VERSION 5.8 ;
BUSBITCHARS "[]" ;
DIVIDERCHAR "/" ;
UNITS
    DATABASE MICRONS 1000 ;
END UNITS

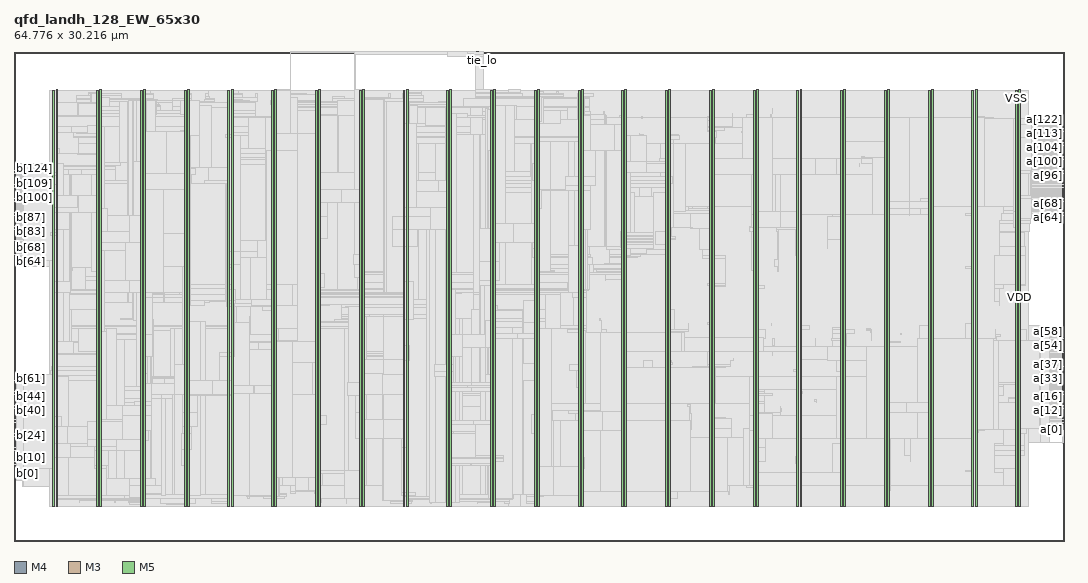
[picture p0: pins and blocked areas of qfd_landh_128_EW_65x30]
MACRO qfd_landh_128_EW_65x30
  FOREIGN qfd_landh_128_EW_65x30 0 0 ;
  CLASS BLOCK ;
  SIZE 64.776 BY 30.216 ;
  PIN a[0]
    DIRECTION INPUT ;
    USE SIGNAL ;
    PORT
      LAYER M4 ;
        RECT  64.692 6.864 64.776 6.888 ;
    END
  END a[0]
  PIN a[100]
    DIRECTION INPUT ;
    USE SIGNAL ;
    PORT
      LAYER M4 ;
        RECT  64.692 23.376 64.776 23.4 ;
    END
  END a[100]
  PIN a[101]
    DIRECTION INPUT ;
    USE SIGNAL ;
    PORT
      LAYER M4 ;
        RECT  64.692 23.472 64.776 23.496 ;
    END
  END a[101]
  PIN a[102]
    DIRECTION INPUT ;
    USE SIGNAL ;
    PORT
      LAYER M4 ;
        RECT  64.692 23.568 64.776 23.592 ;
    END
  END a[102]
  PIN a[103]
    DIRECTION INPUT ;
    USE SIGNAL ;
    PORT
      LAYER M4 ;
        RECT  64.692 23.664 64.776 23.688 ;
    END
  END a[103]
  PIN a[104]
    DIRECTION INPUT ;
    USE SIGNAL ;
    PORT
      LAYER M4 ;
        RECT  64.692 23.76 64.776 23.784 ;
    END
  END a[104]
  PIN a[105]
    DIRECTION INPUT ;
    USE SIGNAL ;
    PORT
      LAYER M4 ;
        RECT  64.692 23.856 64.776 23.88 ;
    END
  END a[105]
  PIN a[106]
    DIRECTION INPUT ;
    USE SIGNAL ;
    PORT
      LAYER M4 ;
        RECT  64.692 23.952 64.776 23.976 ;
    END
  END a[106]
  PIN a[107]
    DIRECTION INPUT ;
    USE SIGNAL ;
    PORT
      LAYER M4 ;
        RECT  64.692 24.048 64.776 24.072 ;
    END
  END a[107]
  PIN a[108]
    DIRECTION INPUT ;
    USE SIGNAL ;
    PORT
      LAYER M4 ;
        RECT  64.692 24.144 64.776 24.168 ;
    END
  END a[108]
  PIN a[109]
    DIRECTION INPUT ;
    USE SIGNAL ;
    PORT
      LAYER M4 ;
        RECT  64.692 24.24 64.776 24.264 ;
    END
  END a[109]
  PIN a[10]
    DIRECTION INPUT ;
    USE SIGNAL ;
    PORT
      LAYER M4 ;
        RECT  64.692 7.824 64.776 7.848 ;
    END
  END a[10]
  PIN a[110]
    DIRECTION INPUT ;
    USE SIGNAL ;
    PORT
      LAYER M4 ;
        RECT  64.692 24.336 64.776 24.36 ;
    END
  END a[110]
  PIN a[111]
    DIRECTION INPUT ;
    USE SIGNAL ;
    PORT
      LAYER M4 ;
        RECT  64.692 24.432 64.776 24.456 ;
    END
  END a[111]
  PIN a[112]
    DIRECTION INPUT ;
    USE SIGNAL ;
    PORT
      LAYER M4 ;
        RECT  64.692 24.528 64.776 24.552 ;
    END
  END a[112]
  PIN a[113]
    DIRECTION INPUT ;
    USE SIGNAL ;
    PORT
      LAYER M4 ;
        RECT  64.692 24.624 64.776 24.648 ;
    END
  END a[113]
  PIN a[114]
    DIRECTION INPUT ;
    USE SIGNAL ;
    PORT
      LAYER M4 ;
        RECT  64.692 24.72 64.776 24.744 ;
    END
  END a[114]
  PIN a[115]
    DIRECTION INPUT ;
    USE SIGNAL ;
    PORT
      LAYER M4 ;
        RECT  64.692 24.816 64.776 24.84 ;
    END
  END a[115]
  PIN a[116]
    DIRECTION INPUT ;
    USE SIGNAL ;
    PORT
      LAYER M4 ;
        RECT  64.692 24.912 64.776 24.936 ;
    END
  END a[116]
  PIN a[117]
    DIRECTION INPUT ;
    USE SIGNAL ;
    PORT
      LAYER M4 ;
        RECT  64.692 25.008 64.776 25.032 ;
    END
  END a[117]
  PIN a[118]
    DIRECTION INPUT ;
    USE SIGNAL ;
    PORT
      LAYER M4 ;
        RECT  64.692 25.104 64.776 25.128 ;
    END
  END a[118]
  PIN a[119]
    DIRECTION INPUT ;
    USE SIGNAL ;
    PORT
      LAYER M4 ;
        RECT  64.692 25.2 64.776 25.224 ;
    END
  END a[119]
  PIN a[11]
    DIRECTION INPUT ;
    USE SIGNAL ;
    PORT
      LAYER M4 ;
        RECT  64.692 7.92 64.776 7.944 ;
    END
  END a[11]
  PIN a[120]
    DIRECTION INPUT ;
    USE SIGNAL ;
    PORT
      LAYER M4 ;
        RECT  64.692 25.296 64.776 25.32 ;
    END
  END a[120]
  PIN a[121]
    DIRECTION INPUT ;
    USE SIGNAL ;
    PORT
      LAYER M4 ;
        RECT  64.692 25.392 64.776 25.416 ;
    END
  END a[121]
  PIN a[122]
    DIRECTION INPUT ;
    USE SIGNAL ;
    PORT
      LAYER M4 ;
        RECT  64.692 25.488 64.776 25.512 ;
    END
  END a[122]
  PIN a[123]
    DIRECTION INPUT ;
    USE SIGNAL ;
    PORT
      LAYER M4 ;
        RECT  64.692 25.584 64.776 25.608 ;
    END
  END a[123]
  PIN a[124]
    DIRECTION INPUT ;
    USE SIGNAL ;
    PORT
      LAYER M4 ;
        RECT  64.692 25.68 64.776 25.704 ;
    END
  END a[124]
  PIN a[125]
    DIRECTION INPUT ;
    USE SIGNAL ;
    PORT
      LAYER M4 ;
        RECT  64.692 25.776 64.776 25.8 ;
    END
  END a[125]
  PIN a[126]
    DIRECTION INPUT ;
    USE SIGNAL ;
    PORT
      LAYER M4 ;
        RECT  64.692 25.872 64.776 25.896 ;
    END
  END a[126]
  PIN a[127]
    DIRECTION INPUT ;
    USE SIGNAL ;
    PORT
      LAYER M4 ;
        RECT  64.692 25.968 64.776 25.992 ;
    END
  END a[127]
  PIN a[12]
    DIRECTION INPUT ;
    USE SIGNAL ;
    PORT
      LAYER M4 ;
        RECT  64.692 8.016 64.776 8.04 ;
    END
  END a[12]
  PIN a[13]
    DIRECTION INPUT ;
    USE SIGNAL ;
    PORT
      LAYER M4 ;
        RECT  64.692 8.112 64.776 8.136 ;
    END
  END a[13]
  PIN a[14]
    DIRECTION INPUT ;
    USE SIGNAL ;
    PORT
      LAYER M4 ;
        RECT  64.692 8.208 64.776 8.232 ;
    END
  END a[14]
  PIN a[15]
    DIRECTION INPUT ;
    USE SIGNAL ;
    PORT
      LAYER M4 ;
        RECT  64.692 8.304 64.776 8.328 ;
    END
  END a[15]
  PIN a[16]
    DIRECTION INPUT ;
    USE SIGNAL ;
    PORT
      LAYER M4 ;
        RECT  64.692 8.4 64.776 8.424 ;
    END
  END a[16]
  PIN a[17]
    DIRECTION INPUT ;
    USE SIGNAL ;
    PORT
      LAYER M4 ;
        RECT  64.692 8.496 64.776 8.52 ;
    END
  END a[17]
  PIN a[18]
    DIRECTION INPUT ;
    USE SIGNAL ;
    PORT
      LAYER M4 ;
        RECT  64.692 8.592 64.776 8.616 ;
    END
  END a[18]
  PIN a[19]
    DIRECTION INPUT ;
    USE SIGNAL ;
    PORT
      LAYER M4 ;
        RECT  64.692 8.688 64.776 8.712 ;
    END
  END a[19]
  PIN a[1]
    DIRECTION INPUT ;
    USE SIGNAL ;
    PORT
      LAYER M4 ;
        RECT  64.692 6.96 64.776 6.984 ;
    END
  END a[1]
  PIN a[20]
    DIRECTION INPUT ;
    USE SIGNAL ;
    PORT
      LAYER M4 ;
        RECT  64.692 8.784 64.776 8.808 ;
    END
  END a[20]
  PIN a[21]
    DIRECTION INPUT ;
    USE SIGNAL ;
    PORT
      LAYER M4 ;
        RECT  64.692 8.88 64.776 8.904 ;
    END
  END a[21]
  PIN a[22]
    DIRECTION INPUT ;
    USE SIGNAL ;
    PORT
      LAYER M4 ;
        RECT  64.692 8.976 64.776 9 ;
    END
  END a[22]
  PIN a[23]
    DIRECTION INPUT ;
    USE SIGNAL ;
    PORT
      LAYER M4 ;
        RECT  64.692 9.072 64.776 9.096 ;
    END
  END a[23]
  PIN a[24]
    DIRECTION INPUT ;
    USE SIGNAL ;
    PORT
      LAYER M4 ;
        RECT  64.692 9.168 64.776 9.192 ;
    END
  END a[24]
  PIN a[25]
    DIRECTION INPUT ;
    USE SIGNAL ;
    PORT
      LAYER M4 ;
        RECT  64.692 9.264 64.776 9.288 ;
    END
  END a[25]
  PIN a[26]
    DIRECTION INPUT ;
    USE SIGNAL ;
    PORT
      LAYER M4 ;
        RECT  64.692 9.36 64.776 9.384 ;
    END
  END a[26]
  PIN a[27]
    DIRECTION INPUT ;
    USE SIGNAL ;
    PORT
      LAYER M4 ;
        RECT  64.692 9.456 64.776 9.48 ;
    END
  END a[27]
  PIN a[28]
    DIRECTION INPUT ;
    USE SIGNAL ;
    PORT
      LAYER M4 ;
        RECT  64.692 9.552 64.776 9.576 ;
    END
  END a[28]
  PIN a[29]
    DIRECTION INPUT ;
    USE SIGNAL ;
    PORT
      LAYER M4 ;
        RECT  64.692 9.648 64.776 9.672 ;
    END
  END a[29]
  PIN a[2]
    DIRECTION INPUT ;
    USE SIGNAL ;
    PORT
      LAYER M4 ;
        RECT  64.692 7.056 64.776 7.08 ;
    END
  END a[2]
  PIN a[30]
    DIRECTION INPUT ;
    USE SIGNAL ;
    PORT
      LAYER M4 ;
        RECT  64.692 9.744 64.776 9.768 ;
    END
  END a[30]
  PIN a[31]
    DIRECTION INPUT ;
    USE SIGNAL ;
    PORT
      LAYER M4 ;
        RECT  64.692 9.84 64.776 9.864 ;
    END
    PORT
      LAYER M4 ;
        RECT  64.716 9.792 64.757 9.912 ;
    END
  END a[31]
  PIN a[32]
    DIRECTION INPUT ;
    USE SIGNAL ;
    PORT
      LAYER M4 ;
        RECT  64.692 9.936 64.776 9.96 ;
    END
  END a[32]
  PIN a[33]
    DIRECTION INPUT ;
    USE SIGNAL ;
    PORT
      LAYER M4 ;
        RECT  64.692 10.032 64.776 10.056 ;
    END
  END a[33]
  PIN a[34]
    DIRECTION INPUT ;
    USE SIGNAL ;
    PORT
      LAYER M4 ;
        RECT  64.692 10.128 64.776 10.152 ;
    END
  END a[34]
  PIN a[35]
    DIRECTION INPUT ;
    USE SIGNAL ;
    PORT
      LAYER M4 ;
        RECT  64.692 10.224 64.776 10.248 ;
    END
  END a[35]
  PIN a[36]
    DIRECTION INPUT ;
    USE SIGNAL ;
    PORT
      LAYER M4 ;
        RECT  64.692 10.32 64.776 10.344 ;
    END
  END a[36]
  PIN a[37]
    DIRECTION INPUT ;
    USE SIGNAL ;
    PORT
      LAYER M4 ;
        RECT  64.692 10.416 64.776 10.44 ;
    END
  END a[37]
  PIN a[38]
    DIRECTION INPUT ;
    USE SIGNAL ;
    PORT
      LAYER M4 ;
        RECT  64.692 10.512 64.776 10.536 ;
    END
  END a[38]
  PIN a[39]
    DIRECTION INPUT ;
    USE SIGNAL ;
    PORT
      LAYER M4 ;
        RECT  64.692 10.608 64.776 10.632 ;
    END
  END a[39]
  PIN a[3]
    DIRECTION INPUT ;
    USE SIGNAL ;
    PORT
      LAYER M4 ;
        RECT  64.692 7.152 64.776 7.176 ;
    END
  END a[3]
  PIN a[40]
    DIRECTION INPUT ;
    USE SIGNAL ;
    PORT
      LAYER M4 ;
        RECT  64.692 10.704 64.776 10.728 ;
    END
  END a[40]
  PIN a[41]
    DIRECTION INPUT ;
    USE SIGNAL ;
    PORT
      LAYER M4 ;
        RECT  64.692 10.8 64.776 10.824 ;
    END
  END a[41]
  PIN a[42]
    DIRECTION INPUT ;
    USE SIGNAL ;
    PORT
      LAYER M4 ;
        RECT  64.692 10.896 64.776 10.92 ;
    END
  END a[42]
  PIN a[43]
    DIRECTION INPUT ;
    USE SIGNAL ;
    PORT
      LAYER M4 ;
        RECT  64.692 10.992 64.776 11.016 ;
    END
  END a[43]
  PIN a[44]
    DIRECTION INPUT ;
    USE SIGNAL ;
    PORT
      LAYER M4 ;
        RECT  64.692 11.088 64.776 11.112 ;
    END
  END a[44]
  PIN a[45]
    DIRECTION INPUT ;
    USE SIGNAL ;
    PORT
      LAYER M4 ;
        RECT  64.692 11.184 64.776 11.208 ;
    END
  END a[45]
  PIN a[46]
    DIRECTION INPUT ;
    USE SIGNAL ;
    PORT
      LAYER M4 ;
        RECT  64.692 11.28 64.776 11.304 ;
    END
  END a[46]
  PIN a[47]
    DIRECTION INPUT ;
    USE SIGNAL ;
    PORT
      LAYER M4 ;
        RECT  64.692 11.376 64.776 11.4 ;
    END
  END a[47]
  PIN a[48]
    DIRECTION INPUT ;
    USE SIGNAL ;
    PORT
      LAYER M4 ;
        RECT  64.692 11.472 64.776 11.496 ;
    END
  END a[48]
  PIN a[49]
    DIRECTION INPUT ;
    USE SIGNAL ;
    PORT
      LAYER M4 ;
        RECT  64.692 11.568 64.776 11.592 ;
    END
  END a[49]
  PIN a[4]
    DIRECTION INPUT ;
    USE SIGNAL ;
    PORT
      LAYER M4 ;
        RECT  64.692 7.248 64.776 7.272 ;
    END
  END a[4]
  PIN a[50]
    DIRECTION INPUT ;
    USE SIGNAL ;
    PORT
      LAYER M4 ;
        RECT  64.692 11.664 64.776 11.688 ;
    END
  END a[50]
  PIN a[51]
    DIRECTION INPUT ;
    USE SIGNAL ;
    PORT
      LAYER M4 ;
        RECT  64.692 11.76 64.776 11.784 ;
    END
  END a[51]
  PIN a[52]
    DIRECTION INPUT ;
    USE SIGNAL ;
    PORT
      LAYER M4 ;
        RECT  64.692 11.856 64.776 11.88 ;
    END
  END a[52]
  PIN a[53]
    DIRECTION INPUT ;
    USE SIGNAL ;
    PORT
      LAYER M4 ;
        RECT  64.692 11.952 64.776 11.976 ;
    END
  END a[53]
  PIN a[54]
    DIRECTION INPUT ;
    USE SIGNAL ;
    PORT
      LAYER M4 ;
        RECT  64.692 12.048 64.776 12.072 ;
    END
  END a[54]
  PIN a[55]
    DIRECTION INPUT ;
    USE SIGNAL ;
    PORT
      LAYER M4 ;
        RECT  64.692 12.144 64.776 12.168 ;
    END
  END a[55]
  PIN a[56]
    DIRECTION INPUT ;
    USE SIGNAL ;
    PORT
      LAYER M4 ;
        RECT  64.692 12.24 64.776 12.264 ;
    END
  END a[56]
  PIN a[57]
    DIRECTION INPUT ;
    USE SIGNAL ;
    PORT
      LAYER M4 ;
        RECT  64.692 12.336 64.776 12.36 ;
    END
  END a[57]
  PIN a[58]
    DIRECTION INPUT ;
    USE SIGNAL ;
    PORT
      LAYER M4 ;
        RECT  64.692 12.432 64.776 12.456 ;
    END
  END a[58]
  PIN a[59]
    DIRECTION INPUT ;
    USE SIGNAL ;
    PORT
      LAYER M4 ;
        RECT  64.692 12.528 64.776 12.552 ;
    END
  END a[59]
  PIN a[5]
    DIRECTION INPUT ;
    USE SIGNAL ;
    PORT
      LAYER M4 ;
        RECT  64.692 7.344 64.776 7.368 ;
    END
  END a[5]
  PIN a[60]
    DIRECTION INPUT ;
    USE SIGNAL ;
    PORT
      LAYER M4 ;
        RECT  64.692 12.624 64.776 12.648 ;
    END
  END a[60]
  PIN a[61]
    DIRECTION INPUT ;
    USE SIGNAL ;
    PORT
      LAYER M4 ;
        RECT  64.692 12.72 64.776 12.744 ;
    END
  END a[61]
  PIN a[62]
    DIRECTION INPUT ;
    USE SIGNAL ;
    PORT
      LAYER M4 ;
        RECT  64.692 12.816 64.776 12.84 ;
    END
  END a[62]
  PIN a[63]
    DIRECTION INPUT ;
    USE SIGNAL ;
    PORT
      LAYER M4 ;
        RECT  64.692 12.912 64.776 12.936 ;
    END
  END a[63]
  PIN a[64]
    DIRECTION INPUT ;
    USE SIGNAL ;
    PORT
      LAYER M4 ;
        RECT  64.692 19.92 64.776 19.944 ;
    END
  END a[64]
  PIN a[65]
    DIRECTION INPUT ;
    USE SIGNAL ;
    PORT
      LAYER M4 ;
        RECT  64.692 20.016 64.776 20.04 ;
    END
  END a[65]
  PIN a[66]
    DIRECTION INPUT ;
    USE SIGNAL ;
    PORT
      LAYER M4 ;
        RECT  64.692 20.112 64.776 20.136 ;
    END
  END a[66]
  PIN a[67]
    DIRECTION INPUT ;
    USE SIGNAL ;
    PORT
      LAYER M4 ;
        RECT  64.692 20.208 64.776 20.232 ;
    END
  END a[67]
  PIN a[68]
    DIRECTION INPUT ;
    USE SIGNAL ;
    PORT
      LAYER M4 ;
        RECT  64.692 20.304 64.776 20.328 ;
    END
  END a[68]
  PIN a[69]
    DIRECTION INPUT ;
    USE SIGNAL ;
    PORT
      LAYER M4 ;
        RECT  64.692 20.4 64.776 20.424 ;
    END
  END a[69]
  PIN a[6]
    DIRECTION INPUT ;
    USE SIGNAL ;
    PORT
      LAYER M4 ;
        RECT  64.692 7.44 64.776 7.464 ;
    END
  END a[6]
  PIN a[70]
    DIRECTION INPUT ;
    USE SIGNAL ;
    PORT
      LAYER M4 ;
        RECT  64.692 20.496 64.776 20.52 ;
    END
  END a[70]
  PIN a[71]
    DIRECTION INPUT ;
    USE SIGNAL ;
    PORT
      LAYER M4 ;
        RECT  64.692 20.592 64.776 20.616 ;
    END
  END a[71]
  PIN a[72]
    DIRECTION INPUT ;
    USE SIGNAL ;
    PORT
      LAYER M4 ;
        RECT  64.692 20.688 64.776 20.712 ;
    END
  END a[72]
  PIN a[73]
    DIRECTION INPUT ;
    USE SIGNAL ;
    PORT
      LAYER M4 ;
        RECT  64.692 20.784 64.776 20.808 ;
    END
  END a[73]
  PIN a[74]
    DIRECTION INPUT ;
    USE SIGNAL ;
    PORT
      LAYER M4 ;
        RECT  64.692 20.88 64.776 20.904 ;
    END
  END a[74]
  PIN a[75]
    DIRECTION INPUT ;
    USE SIGNAL ;
    PORT
      LAYER M4 ;
        RECT  64.692 20.976 64.776 21 ;
    END
  END a[75]
  PIN a[76]
    DIRECTION INPUT ;
    USE SIGNAL ;
    PORT
      LAYER M4 ;
        RECT  64.692 21.072 64.776 21.096 ;
    END
  END a[76]
  PIN a[77]
    DIRECTION INPUT ;
    USE SIGNAL ;
    PORT
      LAYER M4 ;
        RECT  64.692 21.168 64.776 21.192 ;
    END
  END a[77]
  PIN a[78]
    DIRECTION INPUT ;
    USE SIGNAL ;
    PORT
      LAYER M4 ;
        RECT  64.692 21.264 64.776 21.288 ;
    END
  END a[78]
  PIN a[79]
    DIRECTION INPUT ;
    USE SIGNAL ;
    PORT
      LAYER M4 ;
        RECT  64.692 21.36 64.776 21.384 ;
    END
  END a[79]
  PIN a[7]
    DIRECTION INPUT ;
    USE SIGNAL ;
    PORT
      LAYER M4 ;
        RECT  64.692 7.536 64.776 7.56 ;
    END
  END a[7]
  PIN a[80]
    DIRECTION INPUT ;
    USE SIGNAL ;
    PORT
      LAYER M4 ;
        RECT  64.692 21.456 64.776 21.48 ;
    END
  END a[80]
  PIN a[81]
    DIRECTION INPUT ;
    USE SIGNAL ;
    PORT
      LAYER M4 ;
        RECT  64.692 21.552 64.776 21.576 ;
    END
  END a[81]
  PIN a[82]
    DIRECTION INPUT ;
    USE SIGNAL ;
    PORT
      LAYER M4 ;
        RECT  64.692 21.648 64.776 21.672 ;
    END
  END a[82]
  PIN a[83]
    DIRECTION INPUT ;
    USE SIGNAL ;
    PORT
      LAYER M4 ;
        RECT  64.692 21.744 64.776 21.768 ;
    END
  END a[83]
  PIN a[84]
    DIRECTION INPUT ;
    USE SIGNAL ;
    PORT
      LAYER M4 ;
        RECT  64.692 21.84 64.776 21.864 ;
    END
  END a[84]
  PIN a[85]
    DIRECTION INPUT ;
    USE SIGNAL ;
    PORT
      LAYER M4 ;
        RECT  64.692 21.936 64.776 21.96 ;
    END
  END a[85]
  PIN a[86]
    DIRECTION INPUT ;
    USE SIGNAL ;
    PORT
      LAYER M4 ;
        RECT  64.692 22.032 64.776 22.056 ;
    END
  END a[86]
  PIN a[87]
    DIRECTION INPUT ;
    USE SIGNAL ;
    PORT
      LAYER M4 ;
        RECT  64.692 22.128 64.776 22.152 ;
    END
  END a[87]
  PIN a[88]
    DIRECTION INPUT ;
    USE SIGNAL ;
    PORT
      LAYER M4 ;
        RECT  64.692 22.224 64.776 22.248 ;
    END
  END a[88]
  PIN a[89]
    DIRECTION INPUT ;
    USE SIGNAL ;
    PORT
      LAYER M4 ;
        RECT  64.692 22.32 64.776 22.344 ;
    END
  END a[89]
  PIN a[8]
    DIRECTION INPUT ;
    USE SIGNAL ;
    PORT
      LAYER M4 ;
        RECT  64.692 7.632 64.776 7.656 ;
    END
  END a[8]
  PIN a[90]
    DIRECTION INPUT ;
    USE SIGNAL ;
    PORT
      LAYER M4 ;
        RECT  64.692 22.416 64.776 22.44 ;
    END
  END a[90]
  PIN a[91]
    DIRECTION INPUT ;
    USE SIGNAL ;
    PORT
      LAYER M4 ;
        RECT  64.692 22.512 64.776 22.536 ;
    END
  END a[91]
  PIN a[92]
    DIRECTION INPUT ;
    USE SIGNAL ;
    PORT
      LAYER M4 ;
        RECT  64.692 22.608 64.776 22.632 ;
    END
  END a[92]
  PIN a[93]
    DIRECTION INPUT ;
    USE SIGNAL ;
    PORT
      LAYER M4 ;
        RECT  64.692 22.704 64.776 22.728 ;
    END
  END a[93]
  PIN a[94]
    DIRECTION INPUT ;
    USE SIGNAL ;
    PORT
      LAYER M4 ;
        RECT  64.692 22.8 64.776 22.824 ;
    END
  END a[94]
  PIN a[95]
    DIRECTION INPUT ;
    USE SIGNAL ;
    PORT
      LAYER M4 ;
        RECT  64.692 22.896 64.776 22.92 ;
    END
  END a[95]
  PIN a[96]
    DIRECTION INPUT ;
    USE SIGNAL ;
    PORT
      LAYER M4 ;
        RECT  64.692 22.992 64.776 23.016 ;
    END
  END a[96]
  PIN a[97]
    DIRECTION INPUT ;
    USE SIGNAL ;
    PORT
      LAYER M4 ;
        RECT  64.692 23.088 64.776 23.112 ;
    END
  END a[97]
  PIN a[98]
    DIRECTION INPUT ;
    USE SIGNAL ;
    PORT
      LAYER M4 ;
        RECT  64.692 23.184 64.776 23.208 ;
    END
  END a[98]
  PIN a[99]
    DIRECTION INPUT ;
    USE SIGNAL ;
    PORT
      LAYER M4 ;
        RECT  64.692 23.28 64.776 23.304 ;
    END
  END a[99]
  PIN a[9]
    DIRECTION INPUT ;
    USE SIGNAL ;
    PORT
      LAYER M4 ;
        RECT  64.692 7.728 64.776 7.752 ;
    END
  END a[9]
  PIN b[0]
    DIRECTION OUTPUT ;
    USE SIGNAL ;
    PORT
      LAYER M4 ;
        RECT  0 4.176 0.084 4.2 ;
    END
  END b[0]
  PIN b[100]
    DIRECTION OUTPUT ;
    USE SIGNAL ;
    PORT
      LAYER M4 ;
        RECT  0 20.688 0.084 20.712 ;
    END
  END b[100]
  PIN b[101]
    DIRECTION OUTPUT ;
    USE SIGNAL ;
    PORT
      LAYER M4 ;
        RECT  0 20.784 0.084 20.808 ;
    END
  END b[101]
  PIN b[102]
    DIRECTION OUTPUT ;
    USE SIGNAL ;
    PORT
      LAYER M4 ;
        RECT  0 20.88 0.084 20.904 ;
    END
  END b[102]
  PIN b[103]
    DIRECTION OUTPUT ;
    USE SIGNAL ;
    PORT
      LAYER M4 ;
        RECT  0 20.976 0.084 21 ;
    END
  END b[103]
  PIN b[104]
    DIRECTION OUTPUT ;
    USE SIGNAL ;
    PORT
      LAYER M4 ;
        RECT  0 21.072 0.084 21.096 ;
    END
  END b[104]
  PIN b[105]
    DIRECTION OUTPUT ;
    USE SIGNAL ;
    PORT
      LAYER M4 ;
        RECT  0 21.168 0.084 21.192 ;
    END
  END b[105]
  PIN b[106]
    DIRECTION OUTPUT ;
    USE SIGNAL ;
    PORT
      LAYER M4 ;
        RECT  0 21.264 0.084 21.288 ;
    END
  END b[106]
  PIN b[107]
    DIRECTION OUTPUT ;
    USE SIGNAL ;
    PORT
      LAYER M4 ;
        RECT  0 21.36 0.084 21.384 ;
    END
  END b[107]
  PIN b[108]
    DIRECTION OUTPUT ;
    USE SIGNAL ;
    PORT
      LAYER M4 ;
        RECT  0 21.456 0.084 21.48 ;
    END
  END b[108]
  PIN b[109]
    DIRECTION OUTPUT ;
    USE SIGNAL ;
    PORT
      LAYER M4 ;
        RECT  0 21.552 0.084 21.576 ;
    END
  END b[109]
  PIN b[10]
    DIRECTION OUTPUT ;
    USE SIGNAL ;
    PORT
      LAYER M4 ;
        RECT  0 5.136 0.084 5.16 ;
    END
  END b[10]
  PIN b[110]
    DIRECTION OUTPUT ;
    USE SIGNAL ;
    PORT
      LAYER M4 ;
        RECT  0 21.648 0.084 21.672 ;
    END
  END b[110]
  PIN b[111]
    DIRECTION OUTPUT ;
    USE SIGNAL ;
    PORT
      LAYER M4 ;
        RECT  0 21.744 0.084 21.768 ;
    END
  END b[111]
  PIN b[112]
    DIRECTION OUTPUT ;
    USE SIGNAL ;
    PORT
      LAYER M4 ;
        RECT  0 21.84 0.084 21.864 ;
    END
  END b[112]
  PIN b[113]
    DIRECTION OUTPUT ;
    USE SIGNAL ;
    PORT
      LAYER M4 ;
        RECT  0 21.936 0.084 21.96 ;
    END
  END b[113]
  PIN b[114]
    DIRECTION OUTPUT ;
    USE SIGNAL ;
    PORT
      LAYER M4 ;
        RECT  0 22.032 0.084 22.056 ;
    END
  END b[114]
  PIN b[115]
    DIRECTION OUTPUT ;
    USE SIGNAL ;
    PORT
      LAYER M4 ;
        RECT  0 22.128 0.084 22.152 ;
    END
  END b[115]
  PIN b[116]
    DIRECTION OUTPUT ;
    USE SIGNAL ;
    PORT
      LAYER M4 ;
        RECT  0 22.224 0.084 22.248 ;
    END
  END b[116]
  PIN b[117]
    DIRECTION OUTPUT ;
    USE SIGNAL ;
    PORT
      LAYER M4 ;
        RECT  0 22.32 0.084 22.344 ;
    END
  END b[117]
  PIN b[118]
    DIRECTION OUTPUT ;
    USE SIGNAL ;
    PORT
      LAYER M4 ;
        RECT  0 22.416 0.084 22.44 ;
    END
  END b[118]
  PIN b[119]
    DIRECTION OUTPUT ;
    USE SIGNAL ;
    PORT
      LAYER M4 ;
        RECT  0 22.512 0.084 22.536 ;
    END
  END b[119]
  PIN b[11]
    DIRECTION OUTPUT ;
    USE SIGNAL ;
    PORT
      LAYER M4 ;
        RECT  0 5.232 0.084 5.256 ;
    END
  END b[11]
  PIN b[120]
    DIRECTION OUTPUT ;
    USE SIGNAL ;
    PORT
      LAYER M4 ;
        RECT  0 22.608 0.084 22.632 ;
    END
  END b[120]
  PIN b[121]
    DIRECTION OUTPUT ;
    USE SIGNAL ;
    PORT
      LAYER M4 ;
        RECT  0 22.704 0.084 22.728 ;
    END
  END b[121]
  PIN b[122]
    DIRECTION OUTPUT ;
    USE SIGNAL ;
    PORT
      LAYER M4 ;
        RECT  0 22.8 0.084 22.824 ;
    END
  END b[122]
  PIN b[123]
    DIRECTION OUTPUT ;
    USE SIGNAL ;
    PORT
      LAYER M4 ;
        RECT  0 22.896 0.084 22.92 ;
    END
  END b[123]
  PIN b[124]
    DIRECTION OUTPUT ;
    USE SIGNAL ;
    PORT
      LAYER M4 ;
        RECT  0 22.992 0.084 23.016 ;
    END
  END b[124]
  PIN b[125]
    DIRECTION OUTPUT ;
    USE SIGNAL ;
    PORT
      LAYER M4 ;
        RECT  0 23.088 0.084 23.112 ;
    END
  END b[125]
  PIN b[126]
    DIRECTION OUTPUT ;
    USE SIGNAL ;
    PORT
      LAYER M4 ;
        RECT  0 23.184 0.084 23.208 ;
    END
  END b[126]
  PIN b[127]
    DIRECTION OUTPUT ;
    USE SIGNAL ;
    PORT
      LAYER M4 ;
        RECT  0 23.28 0.084 23.304 ;
    END
  END b[127]
  PIN b[12]
    DIRECTION OUTPUT ;
    USE SIGNAL ;
    PORT
      LAYER M4 ;
        RECT  0 5.328 0.084 5.352 ;
    END
  END b[12]
  PIN b[13]
    DIRECTION OUTPUT ;
    USE SIGNAL ;
    PORT
      LAYER M4 ;
        RECT  0 5.424 0.084 5.448 ;
    END
  END b[13]
  PIN b[14]
    DIRECTION OUTPUT ;
    USE SIGNAL ;
    PORT
      LAYER M4 ;
        RECT  0 5.52 0.084 5.544 ;
    END
  END b[14]
  PIN b[15]
    DIRECTION OUTPUT ;
    USE SIGNAL ;
    PORT
      LAYER M4 ;
        RECT  0 5.616 0.084 5.64 ;
    END
  END b[15]
  PIN b[16]
    DIRECTION OUTPUT ;
    USE SIGNAL ;
    PORT
      LAYER M4 ;
        RECT  0 5.712 0.084 5.736 ;
    END
  END b[16]
  PIN b[17]
    DIRECTION OUTPUT ;
    USE SIGNAL ;
    PORT
      LAYER M4 ;
        RECT  0 5.808 0.084 5.832 ;
    END
  END b[17]
  PIN b[18]
    DIRECTION OUTPUT ;
    USE SIGNAL ;
    PORT
      LAYER M4 ;
        RECT  0 5.904 0.084 5.928 ;
    END
  END b[18]
  PIN b[19]
    DIRECTION OUTPUT ;
    USE SIGNAL ;
    PORT
      LAYER M4 ;
        RECT  0 6 0.084 6.024 ;
    END
  END b[19]
  PIN b[1]
    DIRECTION OUTPUT ;
    USE SIGNAL ;
    PORT
      LAYER M4 ;
        RECT  0 4.272 0.084 4.296 ;
    END
  END b[1]
  PIN b[20]
    DIRECTION OUTPUT ;
    USE SIGNAL ;
    PORT
      LAYER M4 ;
        RECT  0 6.096 0.084 6.12 ;
    END
  END b[20]
  PIN b[21]
    DIRECTION OUTPUT ;
    USE SIGNAL ;
    PORT
      LAYER M4 ;
        RECT  0 6.192 0.084 6.216 ;
    END
  END b[21]
  PIN b[22]
    DIRECTION OUTPUT ;
    USE SIGNAL ;
    PORT
      LAYER M4 ;
        RECT  0 6.288 0.084 6.312 ;
    END
  END b[22]
  PIN b[23]
    DIRECTION OUTPUT ;
    USE SIGNAL ;
    PORT
      LAYER M4 ;
        RECT  0 6.384 0.084 6.408 ;
    END
  END b[23]
  PIN b[24]
    DIRECTION OUTPUT ;
    USE SIGNAL ;
    PORT
      LAYER M4 ;
        RECT  0 6.48 0.084 6.504 ;
    END
  END b[24]
  PIN b[25]
    DIRECTION OUTPUT ;
    USE SIGNAL ;
    PORT
      LAYER M4 ;
        RECT  0 6.576 0.084 6.6 ;
    END
  END b[25]
  PIN b[26]
    DIRECTION OUTPUT ;
    USE SIGNAL ;
    PORT
      LAYER M4 ;
        RECT  0 6.672 0.084 6.696 ;
    END
  END b[26]
  PIN b[27]
    DIRECTION OUTPUT ;
    USE SIGNAL ;
    PORT
      LAYER M4 ;
        RECT  0 6.768 0.084 6.792 ;
    END
  END b[27]
  PIN b[28]
    DIRECTION OUTPUT ;
    USE SIGNAL ;
    PORT
      LAYER M4 ;
        RECT  0 6.864 0.084 6.888 ;
    END
  END b[28]
  PIN b[29]
    DIRECTION OUTPUT ;
    USE SIGNAL ;
    PORT
      LAYER M4 ;
        RECT  0 6.96 0.084 6.984 ;
    END
  END b[29]
  PIN b[2]
    DIRECTION OUTPUT ;
    USE SIGNAL ;
    PORT
      LAYER M4 ;
        RECT  0 4.368 0.084 4.392 ;
    END
  END b[2]
  PIN b[30]
    DIRECTION OUTPUT ;
    USE SIGNAL ;
    PORT
      LAYER M4 ;
        RECT  0 7.056 0.084 7.08 ;
    END
  END b[30]
  PIN b[31]
    DIRECTION OUTPUT ;
    USE SIGNAL ;
    PORT
      LAYER M4 ;
        RECT  0 7.152 0.084 7.176 ;
    END
  END b[31]
  PIN b[32]
    DIRECTION OUTPUT ;
    USE SIGNAL ;
    PORT
      LAYER M4 ;
        RECT  0 7.248 0.084 7.272 ;
    END
  END b[32]
  PIN b[33]
    DIRECTION OUTPUT ;
    USE SIGNAL ;
    PORT
      LAYER M4 ;
        RECT  0 7.344 0.084 7.368 ;
    END
  END b[33]
  PIN b[34]
    DIRECTION OUTPUT ;
    USE SIGNAL ;
    PORT
      LAYER M4 ;
        RECT  0 7.44 0.084 7.464 ;
    END
  END b[34]
  PIN b[35]
    DIRECTION OUTPUT ;
    USE SIGNAL ;
    PORT
      LAYER M4 ;
        RECT  0 7.536 0.084 7.56 ;
    END
  END b[35]
  PIN b[36]
    DIRECTION OUTPUT ;
    USE SIGNAL ;
    PORT
      LAYER M4 ;
        RECT  0 7.632 0.084 7.656 ;
    END
  END b[36]
  PIN b[37]
    DIRECTION OUTPUT ;
    USE SIGNAL ;
    PORT
      LAYER M4 ;
        RECT  0 7.728 0.084 7.752 ;
    END
  END b[37]
  PIN b[38]
    DIRECTION OUTPUT ;
    USE SIGNAL ;
    PORT
      LAYER M4 ;
        RECT  0 7.824 0.084 7.848 ;
    END
  END b[38]
  PIN b[39]
    DIRECTION OUTPUT ;
    USE SIGNAL ;
    PORT
      LAYER M4 ;
        RECT  0 7.92 0.084 7.944 ;
    END
  END b[39]
  PIN b[3]
    DIRECTION OUTPUT ;
    USE SIGNAL ;
    PORT
      LAYER M4 ;
        RECT  0 4.464 0.084 4.488 ;
    END
  END b[3]
  PIN b[40]
    DIRECTION OUTPUT ;
    USE SIGNAL ;
    PORT
      LAYER M4 ;
        RECT  0 8.016 0.084 8.04 ;
    END
  END b[40]
  PIN b[41]
    DIRECTION OUTPUT ;
    USE SIGNAL ;
    PORT
      LAYER M4 ;
        RECT  0 8.112 0.084 8.136 ;
    END
  END b[41]
  PIN b[42]
    DIRECTION OUTPUT ;
    USE SIGNAL ;
    PORT
      LAYER M4 ;
        RECT  0 8.208 0.084 8.232 ;
    END
  END b[42]
  PIN b[43]
    DIRECTION OUTPUT ;
    USE SIGNAL ;
    PORT
      LAYER M4 ;
        RECT  0 8.304 0.084 8.328 ;
    END
  END b[43]
  PIN b[44]
    DIRECTION OUTPUT ;
    USE SIGNAL ;
    PORT
      LAYER M4 ;
        RECT  0 8.4 0.084 8.424 ;
    END
  END b[44]
  PIN b[45]
    DIRECTION OUTPUT ;
    USE SIGNAL ;
    PORT
      LAYER M4 ;
        RECT  0 8.496 0.084 8.52 ;
    END
  END b[45]
  PIN b[46]
    DIRECTION OUTPUT ;
    USE SIGNAL ;
    PORT
      LAYER M4 ;
        RECT  0 8.592 0.084 8.616 ;
    END
  END b[46]
  PIN b[47]
    DIRECTION OUTPUT ;
    USE SIGNAL ;
    PORT
      LAYER M4 ;
        RECT  0 8.688 0.084 8.712 ;
    END
  END b[47]
  PIN b[48]
    DIRECTION OUTPUT ;
    USE SIGNAL ;
    PORT
      LAYER M4 ;
        RECT  0 8.784 0.084 8.808 ;
    END
  END b[48]
  PIN b[49]
    DIRECTION OUTPUT ;
    USE SIGNAL ;
    PORT
      LAYER M4 ;
        RECT  0 8.88 0.084 8.904 ;
    END
  END b[49]
  PIN b[4]
    DIRECTION OUTPUT ;
    USE SIGNAL ;
    PORT
      LAYER M4 ;
        RECT  0 4.56 0.084 4.584 ;
    END
  END b[4]
  PIN b[50]
    DIRECTION OUTPUT ;
    USE SIGNAL ;
    PORT
      LAYER M4 ;
        RECT  0 8.976 0.084 9 ;
    END
  END b[50]
  PIN b[51]
    DIRECTION OUTPUT ;
    USE SIGNAL ;
    PORT
      LAYER M4 ;
        RECT  0 9.072 0.084 9.096 ;
    END
  END b[51]
  PIN b[52]
    DIRECTION OUTPUT ;
    USE SIGNAL ;
    PORT
      LAYER M4 ;
        RECT  0 9.168 0.084 9.192 ;
    END
  END b[52]
  PIN b[53]
    DIRECTION OUTPUT ;
    USE SIGNAL ;
    PORT
      LAYER M4 ;
        RECT  0 9.264 0.084 9.288 ;
    END
  END b[53]
  PIN b[54]
    DIRECTION OUTPUT ;
    USE SIGNAL ;
    PORT
      LAYER M4 ;
        RECT  0 9.36 0.084 9.384 ;
    END
  END b[54]
  PIN b[55]
    DIRECTION OUTPUT ;
    USE SIGNAL ;
    PORT
      LAYER M4 ;
        RECT  0 9.456 0.084 9.48 ;
    END
  END b[55]
  PIN b[56]
    DIRECTION OUTPUT ;
    USE SIGNAL ;
    PORT
      LAYER M4 ;
        RECT  0 9.552 0.084 9.576 ;
    END
  END b[56]
  PIN b[57]
    DIRECTION OUTPUT ;
    USE SIGNAL ;
    PORT
      LAYER M4 ;
        RECT  0 9.648 0.084 9.672 ;
    END
  END b[57]
  PIN b[58]
    DIRECTION OUTPUT ;
    USE SIGNAL ;
    PORT
      LAYER M4 ;
        RECT  0 9.744 0.084 9.768 ;
    END
  END b[58]
  PIN b[59]
    DIRECTION OUTPUT ;
    USE SIGNAL ;
    PORT
      LAYER M4 ;
        RECT  0 9.84 0.084 9.864 ;
    END
  END b[59]
  PIN b[5]
    DIRECTION OUTPUT ;
    USE SIGNAL ;
    PORT
      LAYER M4 ;
        RECT  0 4.656 0.084 4.68 ;
    END
  END b[5]
  PIN b[60]
    DIRECTION OUTPUT ;
    USE SIGNAL ;
    PORT
      LAYER M4 ;
        RECT  0 9.936 0.084 9.96 ;
    END
  END b[60]
  PIN b[61]
    DIRECTION OUTPUT ;
    USE SIGNAL ;
    PORT
      LAYER M4 ;
        RECT  0 10.032 0.084 10.056 ;
    END
  END b[61]
  PIN b[62]
    DIRECTION OUTPUT ;
    USE SIGNAL ;
    PORT
      LAYER M4 ;
        RECT  0 10.128 0.084 10.152 ;
    END
  END b[62]
  PIN b[63]
    DIRECTION OUTPUT ;
    USE SIGNAL ;
    PORT
      LAYER M4 ;
        RECT  0 10.224 0.084 10.248 ;
    END
  END b[63]
  PIN b[64]
    DIRECTION OUTPUT ;
    USE SIGNAL ;
    PORT
      LAYER M4 ;
        RECT  0 17.232 0.084 17.256 ;
    END
  END b[64]
  PIN b[65]
    DIRECTION OUTPUT ;
    USE SIGNAL ;
    PORT
      LAYER M4 ;
        RECT  0 17.328 0.084 17.352 ;
    END
  END b[65]
  PIN b[66]
    DIRECTION OUTPUT ;
    USE SIGNAL ;
    PORT
      LAYER M4 ;
        RECT  0 17.424 0.084 17.448 ;
    END
  END b[66]
  PIN b[67]
    DIRECTION OUTPUT ;
    USE SIGNAL ;
    PORT
      LAYER M4 ;
        RECT  0 17.52 0.084 17.544 ;
    END
  END b[67]
  PIN b[68]
    DIRECTION OUTPUT ;
    USE SIGNAL ;
    PORT
      LAYER M4 ;
        RECT  0 17.616 0.084 17.64 ;
    END
  END b[68]
  PIN b[69]
    DIRECTION OUTPUT ;
    USE SIGNAL ;
    PORT
      LAYER M4 ;
        RECT  0 17.712 0.084 17.736 ;
    END
  END b[69]
  PIN b[6]
    DIRECTION OUTPUT ;
    USE SIGNAL ;
    PORT
      LAYER M4 ;
        RECT  0 4.752 0.084 4.776 ;
    END
  END b[6]
  PIN b[70]
    DIRECTION OUTPUT ;
    USE SIGNAL ;
    PORT
      LAYER M4 ;
        RECT  0 17.808 0.084 17.832 ;
    END
  END b[70]
  PIN b[71]
    DIRECTION OUTPUT ;
    USE SIGNAL ;
    PORT
      LAYER M4 ;
        RECT  0 17.904 0.084 17.928 ;
    END
  END b[71]
  PIN b[72]
    DIRECTION OUTPUT ;
    USE SIGNAL ;
    PORT
      LAYER M4 ;
        RECT  0 18 0.084 18.024 ;
    END
  END b[72]
  PIN b[73]
    DIRECTION OUTPUT ;
    USE SIGNAL ;
    PORT
      LAYER M4 ;
        RECT  0 18.096 0.084 18.12 ;
    END
  END b[73]
  PIN b[74]
    DIRECTION OUTPUT ;
    USE SIGNAL ;
    PORT
      LAYER M4 ;
        RECT  0 18.192 0.084 18.216 ;
    END
  END b[74]
  PIN b[75]
    DIRECTION OUTPUT ;
    USE SIGNAL ;
    PORT
      LAYER M4 ;
        RECT  0 18.288 0.084 18.312 ;
    END
  END b[75]
  PIN b[76]
    DIRECTION OUTPUT ;
    USE SIGNAL ;
    PORT
      LAYER M4 ;
        RECT  0 18.384 0.084 18.408 ;
    END
  END b[76]
  PIN b[77]
    DIRECTION OUTPUT ;
    USE SIGNAL ;
    PORT
      LAYER M4 ;
        RECT  0 18.48 0.084 18.504 ;
    END
  END b[77]
  PIN b[78]
    DIRECTION OUTPUT ;
    USE SIGNAL ;
    PORT
      LAYER M4 ;
        RECT  0 18.576 0.084 18.6 ;
    END
  END b[78]
  PIN b[79]
    DIRECTION OUTPUT ;
    USE SIGNAL ;
    PORT
      LAYER M4 ;
        RECT  0 18.672 0.084 18.696 ;
    END
  END b[79]
  PIN b[7]
    DIRECTION OUTPUT ;
    USE SIGNAL ;
    PORT
      LAYER M4 ;
        RECT  0 4.848 0.084 4.872 ;
    END
  END b[7]
  PIN b[80]
    DIRECTION OUTPUT ;
    USE SIGNAL ;
    PORT
      LAYER M4 ;
        RECT  0 18.768 0.084 18.792 ;
    END
  END b[80]
  PIN b[81]
    DIRECTION OUTPUT ;
    USE SIGNAL ;
    PORT
      LAYER M4 ;
        RECT  0 18.864 0.084 18.888 ;
    END
  END b[81]
  PIN b[82]
    DIRECTION OUTPUT ;
    USE SIGNAL ;
    PORT
      LAYER M4 ;
        RECT  0 18.96 0.084 18.984 ;
    END
  END b[82]
  PIN b[83]
    DIRECTION OUTPUT ;
    USE SIGNAL ;
    PORT
      LAYER M4 ;
        RECT  0 19.056 0.084 19.08 ;
    END
  END b[83]
  PIN b[84]
    DIRECTION OUTPUT ;
    USE SIGNAL ;
    PORT
      LAYER M4 ;
        RECT  0 19.152 0.084 19.176 ;
    END
  END b[84]
  PIN b[85]
    DIRECTION OUTPUT ;
    USE SIGNAL ;
    PORT
      LAYER M4 ;
        RECT  0 19.248 0.084 19.272 ;
    END
  END b[85]
  PIN b[86]
    DIRECTION OUTPUT ;
    USE SIGNAL ;
    PORT
      LAYER M4 ;
        RECT  0 19.344 0.084 19.368 ;
    END
  END b[86]
  PIN b[87]
    DIRECTION OUTPUT ;
    USE SIGNAL ;
    PORT
      LAYER M4 ;
        RECT  0 19.44 0.084 19.464 ;
    END
  END b[87]
  PIN b[88]
    DIRECTION OUTPUT ;
    USE SIGNAL ;
    PORT
      LAYER M4 ;
        RECT  0 19.536 0.084 19.56 ;
    END
  END b[88]
  PIN b[89]
    DIRECTION OUTPUT ;
    USE SIGNAL ;
    PORT
      LAYER M4 ;
        RECT  0 19.632 0.084 19.656 ;
    END
  END b[89]
  PIN b[8]
    DIRECTION OUTPUT ;
    USE SIGNAL ;
    PORT
      LAYER M4 ;
        RECT  0 4.944 0.084 4.968 ;
    END
  END b[8]
  PIN b[90]
    DIRECTION OUTPUT ;
    USE SIGNAL ;
    PORT
      LAYER M4 ;
        RECT  0 19.728 0.084 19.752 ;
    END
  END b[90]
  PIN b[91]
    DIRECTION OUTPUT ;
    USE SIGNAL ;
    PORT
      LAYER M4 ;
        RECT  0 19.824 0.084 19.848 ;
    END
  END b[91]
  PIN b[92]
    DIRECTION OUTPUT ;
    USE SIGNAL ;
    PORT
      LAYER M4 ;
        RECT  0 19.92 0.084 19.944 ;
    END
  END b[92]
  PIN b[93]
    DIRECTION OUTPUT ;
    USE SIGNAL ;
    PORT
      LAYER M4 ;
        RECT  0 20.016 0.084 20.04 ;
    END
  END b[93]
  PIN b[94]
    DIRECTION OUTPUT ;
    USE SIGNAL ;
    PORT
      LAYER M4 ;
        RECT  0 20.112 0.084 20.136 ;
    END
  END b[94]
  PIN b[95]
    DIRECTION OUTPUT ;
    USE SIGNAL ;
    PORT
      LAYER M4 ;
        RECT  0 20.208 0.084 20.232 ;
    END
  END b[95]
  PIN b[96]
    DIRECTION OUTPUT ;
    USE SIGNAL ;
    PORT
      LAYER M4 ;
        RECT  0 20.304 0.084 20.328 ;
    END
  END b[96]
  PIN b[97]
    DIRECTION OUTPUT ;
    USE SIGNAL ;
    PORT
      LAYER M4 ;
        RECT  0 20.4 0.084 20.424 ;
    END
  END b[97]
  PIN b[98]
    DIRECTION OUTPUT ;
    USE SIGNAL ;
    PORT
      LAYER M4 ;
        RECT  0 20.496 0.084 20.52 ;
    END
  END b[98]
  PIN b[99]
    DIRECTION OUTPUT ;
    USE SIGNAL ;
    PORT
      LAYER M4 ;
        RECT  0 20.592 0.084 20.616 ;
    END
  END b[99]
  PIN b[9]
    DIRECTION OUTPUT ;
    USE SIGNAL ;
    PORT
      LAYER M4 ;
        RECT  0 5.04 0.084 5.064 ;
    END
  END b[9]
  PIN ck
    DIRECTION INPUT ;
    USE SIGNAL ;
    PORT
      LAYER M3 ;
        RECT  28.332 30.179 28.35 30.216 ;
    END
  END ck
  PIN ckf
    DIRECTION INPUT ;
    USE SIGNAL ;
    PORT
      LAYER M3 ;
        RECT  28.404 30.179 28.422 30.216 ;
    END
  END ckf
  PIN ea
    DIRECTION INPUT ;
    USE SIGNAL ;
    PORT
      LAYER M4 ;
        RECT  64.692 13.008 64.776 13.032 ;
    END
  END ea
  PIN fault
    DIRECTION OUTPUT ;
    USE SIGNAL ;
    PORT
      LAYER M3 ;
        RECT  28.476 30.179 28.494 30.216 ;
    END
  END fault
  PIN k0
    DIRECTION INPUT ;
    USE SIGNAL ;
    PORT
      LAYER M3 ;
        RECT  28.548 30.179 28.566 30.216 ;
    END
  END k0
  PIN k1
    DIRECTION INPUT ;
    USE SIGNAL ;
    PORT
      LAYER M3 ;
        RECT  28.62 30.179 28.638 30.216 ;
    END
  END k1
  PIN k2
    DIRECTION INPUT ;
    USE SIGNAL ;
    PORT
      LAYER M3 ;
        RECT  28.692 30.179 28.71 30.216 ;
    END
  END k2
  PIN rs
    DIRECTION INPUT ;
    USE SIGNAL ;
    PORT
      LAYER M3 ;
        RECT  28.764 30.179 28.782 30.216 ;
    END
  END rs
  PIN tie_hi
    DIRECTION OUTPUT ;
    USE SIGNAL ;
    PORT
      LAYER M3 ;
        RECT  28.836 30.179 28.854 30.216 ;
    END
  END tie_hi
  PIN tie_lo
    DIRECTION OUTPUT ;
    USE SIGNAL ;
    PORT
      LAYER M3 ;
        RECT  28.908 30.179 28.926 30.216 ;
    END
  END tie_lo
  PIN VDD
    DIRECTION INOUT ;
    USE POWER ;
    PORT
      LAYER M5 ;
        RECT  61.992 2.151 62.112 27.833 ;
        RECT  59.292 2.151 59.412 27.833 ;
        RECT  56.592 2.151 56.712 27.833 ;
        RECT  53.892 2.151 54.012 27.833 ;
        RECT  51.192 2.151 51.312 27.833 ;
        RECT  48.492 2.151 48.612 27.833 ;
        RECT  45.792 2.151 45.912 27.833 ;
        RECT  43.092 2.151 43.212 27.833 ;
        RECT  40.392 2.151 40.512 27.833 ;
        RECT  37.692 2.151 37.812 27.833 ;
        RECT  34.992 2.151 35.112 27.833 ;
        RECT  32.292 2.151 32.412 27.833 ;
        RECT  29.592 2.151 29.712 27.833 ;
        RECT  26.892 2.151 27.012 27.833 ;
        RECT  24.192 2.151 24.312 27.833 ;
        RECT  21.492 2.151 21.612 27.833 ;
        RECT  18.792 2.151 18.912 27.833 ;
        RECT  16.092 2.151 16.212 27.833 ;
        RECT  13.392 2.151 13.512 27.833 ;
        RECT  10.692 2.151 10.812 27.833 ;
        RECT  7.992 2.151 8.112 27.833 ;
        RECT  5.292 2.151 5.412 27.833 ;
        RECT  2.592 2.151 2.712 27.833 ;
    END
  END VDD
  PIN VSS
    DIRECTION INOUT ;
    USE GROUND ;
    PORT
      LAYER M5 ;
        RECT  61.8 2.137 61.92 27.819 ;
        RECT  59.1 2.137 59.22 27.819 ;
        RECT  56.4 2.137 56.52 27.819 ;
        RECT  53.7 2.137 53.82 27.819 ;
        RECT  51 2.137 51.12 27.819 ;
        RECT  48.3 2.137 48.42 27.819 ;
        RECT  45.6 2.137 45.72 27.819 ;
        RECT  42.9 2.137 43.02 27.819 ;
        RECT  40.2 2.137 40.32 27.819 ;
        RECT  37.5 2.137 37.62 27.819 ;
        RECT  34.8 2.137 34.92 27.819 ;
        RECT  32.1 2.137 32.22 27.819 ;
        RECT  29.4 2.137 29.52 27.819 ;
        RECT  26.7 2.137 26.82 27.819 ;
        RECT  24 2.137 24.12 27.819 ;
        RECT  21.3 2.137 21.42 27.819 ;
        RECT  18.6 2.137 18.72 27.819 ;
        RECT  15.9 2.137 16.02 27.819 ;
        RECT  13.2 2.137 13.32 27.819 ;
        RECT  10.5 2.137 10.62 27.819 ;
        RECT  7.8 2.137 7.92 27.819 ;
        RECT  5.1 2.137 5.22 27.819 ;
        RECT  2.4 2.137 2.52 27.819 ;
    END
  END VSS
  # OT_OBS_CLOSED layer=M5 d_um=1.536 added=97
  OBS
    LAYER RVTN ;
     RECT  2.16 2.16 62.586 2.295 ;
     RECT  2.16 2.565 62.586 2.835 ;
     RECT  2.16 3.105 62.586 3.375 ;
     RECT  2.16 3.645 62.586 3.915 ;
     RECT  2.16 4.185 62.586 4.455 ;
     RECT  2.16 4.725 62.586 4.995 ;
     RECT  2.16 5.265 62.586 5.535 ;
     RECT  2.16 5.805 62.586 6.075 ;
     RECT  2.16 6.345 62.586 6.615 ;
     RECT  2.16 6.885 62.586 7.155 ;
     RECT  2.16 7.425 62.586 7.695 ;
     RECT  2.16 7.965 62.586 8.235 ;
     RECT  2.16 8.505 62.586 8.775 ;
     RECT  2.16 9.045 62.586 9.315 ;
     RECT  2.16 9.585 62.586 9.855 ;
     RECT  2.16 10.125 62.586 10.395 ;
     RECT  2.16 10.665 62.586 10.935 ;
     RECT  2.16 11.205 62.586 11.475 ;
     RECT  2.16 11.745 62.586 12.015 ;
     RECT  2.16 12.285 62.586 12.555 ;
     RECT  2.16 12.825 62.586 13.095 ;
     RECT  2.16 13.365 62.586 13.635 ;
     RECT  2.16 13.905 62.586 14.175 ;
     RECT  2.16 14.445 62.586 14.715 ;
     RECT  2.16 14.985 62.586 15.255 ;
     RECT  2.16 15.525 62.586 15.795 ;
     RECT  2.16 16.065 62.586 16.335 ;
     RECT  2.16 16.605 62.586 16.875 ;
     RECT  2.16 17.145 62.586 17.415 ;
     RECT  2.16 17.685 62.586 17.955 ;
     RECT  2.16 18.225 62.586 18.495 ;
     RECT  2.16 18.765 62.586 19.035 ;
     RECT  2.16 19.305 62.586 19.575 ;
     RECT  2.16 19.845 62.586 20.115 ;
     RECT  2.16 20.385 62.586 20.655 ;
     RECT  2.16 20.925 62.586 21.195 ;
     RECT  2.16 21.465 62.586 21.735 ;
     RECT  2.16 22.005 62.586 22.275 ;
     RECT  2.16 22.545 62.586 22.815 ;
     RECT  2.16 23.085 62.586 23.355 ;
     RECT  2.16 23.625 62.586 23.895 ;
     RECT  2.16 24.165 62.586 24.435 ;
     RECT  2.16 24.705 62.586 24.975 ;
     RECT  2.16 25.245 62.586 25.515 ;
     RECT  2.16 25.785 62.586 26.055 ;
     RECT  2.16 26.325 62.586 26.595 ;
     RECT  2.16 26.865 62.586 27.135 ;
     RECT  2.16 27.405 62.586 27.675 ;
    LAYER RVTP ;
     RECT  2.16 2.295 62.586 2.565 ;
     RECT  2.16 2.835 62.586 3.105 ;
     RECT  2.16 3.375 62.586 3.645 ;
     RECT  2.16 3.915 62.586 4.185 ;
     RECT  2.16 4.455 62.586 4.725 ;
     RECT  2.16 4.995 62.586 5.265 ;
     RECT  2.16 5.535 62.586 5.805 ;
     RECT  2.16 6.075 62.586 6.345 ;
     RECT  2.16 6.615 62.586 6.885 ;
     RECT  2.16 7.155 62.586 7.425 ;
     RECT  2.16 7.695 62.586 7.965 ;
     RECT  2.16 8.235 62.586 8.505 ;
     RECT  2.16 8.775 62.586 9.045 ;
     RECT  2.16 9.315 62.586 9.585 ;
     RECT  2.16 9.855 62.586 10.125 ;
     RECT  2.16 10.395 62.586 10.665 ;
     RECT  2.16 10.935 62.586 11.205 ;
     RECT  2.16 11.475 62.586 11.745 ;
     RECT  2.16 12.015 62.586 12.285 ;
     RECT  2.16 12.555 62.586 12.825 ;
     RECT  2.16 13.095 62.586 13.365 ;
     RECT  2.16 13.635 62.586 13.905 ;
     RECT  2.16 14.175 62.586 14.445 ;
     RECT  2.16 14.715 62.586 14.985 ;
     RECT  2.16 15.255 62.586 15.525 ;
     RECT  2.16 15.795 62.586 16.065 ;
     RECT  2.16 16.335 62.586 16.605 ;
     RECT  2.16 16.875 62.586 17.145 ;
     RECT  2.16 17.415 62.586 17.685 ;
     RECT  2.16 17.955 62.586 18.225 ;
     RECT  2.16 18.495 62.586 18.765 ;
     RECT  2.16 19.035 62.586 19.305 ;
     RECT  2.16 19.575 62.586 19.845 ;
     RECT  2.16 20.115 62.586 20.385 ;
     RECT  2.16 20.655 62.586 20.925 ;
     RECT  2.16 21.195 62.586 21.465 ;
     RECT  2.16 21.735 62.586 22.005 ;
     RECT  2.16 22.275 62.586 22.545 ;
     RECT  2.16 22.815 62.586 23.085 ;
     RECT  2.16 23.355 62.586 23.625 ;
     RECT  2.16 23.895 62.586 24.165 ;
     RECT  2.16 24.435 62.586 24.705 ;
     RECT  2.16 24.975 62.586 25.245 ;
     RECT  2.16 25.515 62.586 25.785 ;
     RECT  2.16 26.055 62.586 26.325 ;
     RECT  2.16 26.595 62.586 26.865 ;
     RECT  2.16 27.135 62.586 27.405 ;
     RECT  2.16 27.675 62.586 27.81 ;
    LAYER M1 ;
     RECT  2.16 2.151 62.586 27.819 ;
    LAYER M2 ;
     RECT  0.103 3.96 0.139 4.284 ;
     RECT  0.103 6.588 0.203 6.84 ;
     RECT  0.103 19.548 0.203 19.566 ;
     RECT  0.139 3.726 0.535 4.482 ;
     RECT  0.499 17.046 0.535 17.064 ;
     RECT  0.103 20.934 0.535 20.952 ;
     RECT  0.535 16.956 0.635 19.332 ;
     RECT  0.535 7.938 0.679 7.956 ;
     RECT  0.679 7.938 0.779 8.154 ;
     RECT  0.535 22.626 2.155 22.644 ;
     RECT  0.535 3.384 2.16 5.094 ;
     RECT  0.203 6.786 2.16 6.804 ;
     RECT  0.779 7.938 2.16 7.956 ;
     RECT  0.635 16.956 2.16 17.982 ;
     RECT  0.635 18.774 2.16 19.332 ;
     RECT  0.535 20.466 2.16 21.222 ;
     RECT  2.155 22.176 2.16 22.644 ;
     RECT  28.615 30.15 28.967 30.168 ;
     RECT  2.16 2.151 30.487 27.819 ;
     RECT  30.487 2.151 31.271 27.864 ;
     RECT  31.271 2.151 62.586 27.819 ;
     RECT  62.586 19.08 62.663 25.848 ;
     RECT  62.663 19.62 62.699 25.848 ;
     RECT  62.699 19.89 62.807 25.848 ;
     RECT  62.807 19.89 63.311 22.032 ;
     RECT  62.807 22.788 63.311 25.848 ;
     RECT  62.586 6.048 63.347 13.32 ;
     RECT  63.311 19.89 63.347 21.186 ;
     RECT  63.311 22.788 63.347 25.776 ;
     RECT  63.347 6.048 63.887 9.378 ;
     RECT  63.347 10.638 63.887 13.086 ;
     RECT  63.347 19.89 63.887 20.376 ;
     RECT  63.347 21.168 63.887 21.186 ;
     RECT  63.311 22.014 63.887 22.032 ;
     RECT  63.347 22.788 63.887 25.542 ;
     RECT  63.887 6.858 63.923 9.342 ;
     RECT  63.887 11.448 63.923 13.014 ;
     RECT  63.887 22.788 63.923 23.346 ;
     RECT  63.887 25.524 63.923 25.542 ;
     RECT  63.923 7.938 63.959 7.956 ;
     RECT  63.923 9.324 63.959 9.342 ;
     RECT  63.923 11.718 63.959 12.348 ;
     RECT  63.887 20.088 63.959 20.376 ;
     RECT  63.959 20.088 63.995 20.106 ;
     RECT  63.887 6.048 64.679 6.102 ;
     RECT  63.923 6.858 64.679 6.948 ;
     RECT  64.679 6.084 64.751 6.102 ;
     RECT  64.679 6.93 64.751 6.948 ;
     RECT  64.651 8.172 64.751 8.19 ;
     RECT  64.651 9.792 64.751 9.918 ;
     RECT  64.651 11.106 64.751 11.124 ;
     RECT  64.651 22.446 64.751 22.464 ;
     RECT  64.651 24.102 64.751 24.804 ;
    LAYER M3 ;
     RECT  7.815 2.143 7.905 2.191 ;
     RECT  7.776 2.191 7.905 2.227 ;
     RECT  10.515 2.143 10.605 2.227 ;
     RECT  9.9 2.227 10.605 2.263 ;
     RECT  9.432 2.263 10.605 2.299 ;
     RECT  24.015 2.143 24.105 2.299 ;
     RECT  32.115 2.143 32.205 2.299 ;
     RECT  9.324 2.299 11.214 2.335 ;
     RECT  12.204 2.299 12.222 2.335 ;
     RECT  13.215 2.143 13.305 2.335 ;
     RECT  24.015 2.299 24.534 2.335 ;
     RECT  26.715 2.143 26.805 2.347 ;
     RECT  7.128 2.227 7.905 2.371 ;
     RECT  18.615 2.143 18.705 2.371 ;
     RECT  28.584 2.335 28.602 2.371 ;
     RECT  29.415 2.143 29.505 2.371 ;
     RECT  2.415 2.143 2.505 2.413 ;
     RECT  5.115 2.143 5.205 2.413 ;
     RECT  7.056 2.371 7.905 2.413 ;
     RECT  12.204 2.335 13.305 2.413 ;
     RECT  15.915 2.143 16.005 2.413 ;
     RECT  21.315 2.143 21.405 2.413 ;
     RECT  28.584 2.371 29.505 2.413 ;
     RECT  30.24 2.335 30.546 2.413 ;
     RECT  31.644 2.299 32.205 2.413 ;
     RECT  34.815 2.143 34.905 2.413 ;
     RECT  37.515 2.143 37.605 2.413 ;
     RECT  40.215 2.143 40.305 2.413 ;
     RECT  42.915 2.143 43.005 2.413 ;
     RECT  45.615 2.143 45.705 2.413 ;
     RECT  48.315 2.143 48.405 2.413 ;
     RECT  51.015 2.143 51.105 2.413 ;
     RECT  53.715 2.143 53.805 2.413 ;
     RECT  56.415 2.143 56.505 2.413 ;
     RECT  59.115 2.143 59.205 2.413 ;
     RECT  61.815 2.143 61.905 2.413 ;
     RECT  23.256 2.335 24.534 2.461 ;
     RECT  26.715 2.347 27.486 2.461 ;
     RECT  28.584 2.413 30.546 2.461 ;
     RECT  23.256 2.461 24.57 2.488 ;
     RECT  4.032 2.371 4.05 2.497 ;
     RECT  5.115 2.413 5.397 2.497 ;
     RECT  6.228 2.371 6.246 2.497 ;
     RECT  7.056 2.413 8.097 2.497 ;
     RECT  22.716 2.488 24.57 2.525 ;
     RECT  22.896 2.525 24.57 2.533 ;
     RECT  25.668 2.335 25.758 2.533 ;
     RECT  26.715 2.461 30.546 2.533 ;
     RECT  2.415 2.413 2.697 2.569 ;
     RECT  4.032 2.497 8.097 2.569 ;
     RECT  22.896 2.533 30.546 2.587 ;
     RECT  2.415 2.569 8.097 2.605 ;
     RECT  9.036 2.335 11.214 2.605 ;
     RECT  15.915 2.413 16.197 2.605 ;
     RECT  20.52 2.335 20.538 2.605 ;
     RECT  22.896 2.587 30.726 2.605 ;
     RECT  20.448 2.605 20.538 2.635 ;
     RECT  21.315 2.413 21.597 2.635 ;
     RECT  2.415 2.605 11.394 2.641 ;
     RECT  12.204 2.413 13.497 2.641 ;
     RECT  14.4 2.605 14.418 2.641 ;
     RECT  15.588 2.605 16.197 2.641 ;
     RECT  20.448 2.635 21.597 2.641 ;
     RECT  40.215 2.413 40.497 2.641 ;
     RECT  15.372 2.641 16.686 2.731 ;
     RECT  14.4 2.641 14.526 2.767 ;
     RECT  15.372 2.731 16.794 2.767 ;
     RECT  31.644 2.413 32.397 2.767 ;
     RECT  18.615 2.371 18.954 2.803 ;
     RECT  19.692 2.641 21.597 2.803 ;
     RECT  2.415 2.641 13.497 2.839 ;
     RECT  14.328 2.767 16.794 2.839 ;
     RECT  18.615 2.803 21.597 2.875 ;
     RECT  2.415 2.839 16.794 2.903 ;
     RECT  18.612 2.875 21.597 2.911 ;
     RECT  31.644 2.767 32.67 2.911 ;
     RECT  33.66 2.869 33.678 2.911 ;
     RECT  22.896 2.605 30.798 3.001 ;
     RECT  31.644 2.911 32.814 3.001 ;
     RECT  17.064 2.911 17.37 3.037 ;
     RECT  22.896 3.001 32.814 3.037 ;
     RECT  33.588 2.911 33.678 3.037 ;
     RECT  44.1 2.875 44.118 3.067 ;
     RECT  17.064 3.037 17.586 3.073 ;
     RECT  18.54 2.911 21.597 3.073 ;
     RECT  37.515 2.413 37.797 3.073 ;
     RECT  53.715 2.413 53.997 3.145 ;
     RECT  37.515 3.073 38.286 3.271 ;
     RECT  22.896 3.037 33.678 3.293 ;
     RECT  37.515 3.271 38.79 3.299 ;
     RECT  34.815 2.413 35.097 3.307 ;
     RECT  45.615 2.413 45.897 3.307 ;
     RECT  22.896 3.293 33.642 3.335 ;
     RECT  38.772 3.299 38.79 3.371 ;
     RECT  34.488 3.307 35.097 3.379 ;
     RECT  22.896 3.335 30.51 3.415 ;
     RECT  34.452 3.379 35.097 3.415 ;
     RECT  22.572 3.415 30.51 3.451 ;
     RECT  36.072 3.181 36.09 3.451 ;
     RECT  35.928 3.451 36.09 3.569 ;
     RECT  31.32 3.335 33.642 3.605 ;
     RECT  22.5 3.451 30.51 3.613 ;
     RECT  51.015 2.413 51.297 3.613 ;
     RECT  45.18 3.307 45.897 3.649 ;
     RECT  2.415 2.903 16.254 3.713 ;
     RECT  0.54 3.379 0.558 3.721 ;
     RECT  6.228 3.713 16.254 3.721 ;
     RECT  17.064 3.073 21.597 3.721 ;
     RECT  35.928 3.569 35.982 3.725 ;
     RECT  35.928 3.725 35.946 3.749 ;
     RECT  31.716 3.605 33.642 3.839 ;
     RECT  31.788 3.839 33.642 3.875 ;
     RECT  0.144 3.721 0.558 3.955 ;
     RECT  46.944 3.955 46.962 4.109 ;
     RECT  22.356 3.613 30.51 4.117 ;
     RECT  31.824 3.875 33.642 4.117 ;
     RECT  34.452 3.415 35.19 4.117 ;
     RECT  61.02 3.403 61.038 4.225 ;
     RECT  59.115 2.413 59.397 4.261 ;
     RECT  58.716 4.261 59.397 4.379 ;
     RECT  44.964 3.649 45.897 4.415 ;
     RECT  37.515 3.299 37.797 4.423 ;
     RECT  2.415 3.713 5.454 4.495 ;
     RECT  6.228 3.721 21.597 4.495 ;
     RECT  37.44 4.423 37.797 4.495 ;
     RECT  60.516 4.225 61.038 4.495 ;
     RECT  61.815 2.413 62.097 4.495 ;
     RECT  2.415 4.495 21.597 4.523 ;
     RECT  22.356 4.117 30.582 4.531 ;
     RECT  31.824 4.117 35.19 4.531 ;
     RECT  2.415 4.523 16.218 4.541 ;
     RECT  17.064 4.523 21.597 4.559 ;
     RECT  0.108 3.955 0.558 4.589 ;
     RECT  31.824 4.531 35.946 4.621 ;
     RECT  37.188 4.495 37.797 4.621 ;
     RECT  37.188 4.621 37.89 4.765 ;
     RECT  48.315 2.413 48.597 4.765 ;
     RECT  2.415 4.541 3.006 4.801 ;
     RECT  3.852 4.541 16.218 4.919 ;
     RECT  22.356 4.531 30.942 4.927 ;
     RECT  31.68 4.621 35.946 4.927 ;
     RECT  36.864 4.765 37.89 4.927 ;
     RECT  45.18 4.415 45.897 4.927 ;
     RECT  10.152 4.919 16.218 4.991 ;
     RECT  10.26 4.991 16.218 5.027 ;
     RECT  0.144 4.589 0.558 5.069 ;
     RECT  40.215 2.641 40.914 5.071 ;
     RECT  22.356 4.927 37.89 5.099 ;
     RECT  38.736 4.963 38.754 5.099 ;
     RECT  0.54 5.069 0.558 5.165 ;
     RECT  33.84 5.099 37.89 5.189 ;
     RECT  48.204 4.765 48.597 5.189 ;
     RECT  60.516 4.495 62.097 5.269 ;
     RECT  2.304 4.801 3.006 5.305 ;
     RECT  3.852 4.919 9.378 5.305 ;
     RECT  37.476 5.189 37.89 5.305 ;
     RECT  55.296 4.927 55.314 5.305 ;
     RECT  17.1 4.559 21.597 5.333 ;
     RECT  43.992 3.067 44.118 5.341 ;
     RECT  43.992 5.341 44.442 5.495 ;
     RECT  39.888 5.071 40.914 5.575 ;
     RECT  60.516 5.269 62.334 5.575 ;
     RECT  22.356 5.099 33.102 5.603 ;
     RECT  17.676 5.333 21.597 5.701 ;
     RECT  45.18 4.927 46.386 5.755 ;
     RECT  39.78 5.575 40.914 5.773 ;
     RECT  10.26 5.027 16.197 5.845 ;
     RECT  33.84 5.189 36.342 5.873 ;
     RECT  2.304 5.305 9.378 5.881 ;
     RECT  10.116 5.845 16.197 5.881 ;
     RECT  39.78 5.773 41.634 5.881 ;
     RECT  60.516 5.575 62.37 5.909 ;
     RECT  33.912 5.873 36.342 5.971 ;
     RECT  39.096 5.881 41.634 5.999 ;
     RECT  50.472 3.613 51.297 5.999 ;
     RECT  60.516 5.909 61.074 5.999 ;
     RECT  64.656 6.043 64.674 6.079 ;
     RECT  37.476 5.305 38.214 6.151 ;
     RECT  17.676 5.701 21.87 6.277 ;
     RECT  2.304 5.881 16.197 6.313 ;
     RECT  17.532 6.277 21.87 6.331 ;
     RECT  22.68 5.603 33.102 6.331 ;
     RECT  33.912 5.971 36.486 6.349 ;
     RECT  37.476 6.151 38.322 6.349 ;
     RECT  0.18 6.331 0.198 6.379 ;
     RECT  2.304 6.313 16.65 6.421 ;
     RECT  17.532 6.331 33.102 6.421 ;
     RECT  39.78 5.999 40.497 6.449 ;
     RECT  2.304 6.421 33.102 6.509 ;
     RECT  33.912 6.349 38.322 6.511 ;
     RECT  41.616 5.999 41.634 6.539 ;
     RECT  52.38 6.421 52.398 6.539 ;
     RECT  54.936 5.305 55.314 6.539 ;
     RECT  61.02 5.999 61.074 6.539 ;
     RECT  53.715 3.145 54.054 6.583 ;
     RECT  58.14 6.331 58.158 6.583 ;
     RECT  59.115 4.379 59.397 6.583 ;
     RECT  45.144 5.755 46.386 6.655 ;
     RECT  61.815 5.909 62.37 6.655 ;
     RECT  53.64 6.583 54.054 6.691 ;
     RECT  54.936 6.539 54.954 6.691 ;
     RECT  58.14 6.583 59.397 6.691 ;
     RECT  4.032 6.509 33.102 6.719 ;
     RECT  0.108 6.379 0.198 6.781 ;
     RECT  4.032 6.719 16.686 6.809 ;
     RECT  17.532 6.719 33.102 6.809 ;
     RECT  33.912 6.511 39.042 6.809 ;
     RECT  58.14 6.691 59.49 6.809 ;
     RECT  58.716 6.809 59.49 6.817 ;
     RECT  41.688 6.619 41.706 6.853 ;
     RECT  63.864 6.385 63.882 6.853 ;
     RECT  64.656 6.079 64.746 6.853 ;
     RECT  33.912 6.809 38.934 6.881 ;
     RECT  0.108 6.781 0.558 6.893 ;
     RECT  53.64 6.691 54.954 6.893 ;
     RECT  45 6.655 46.386 6.941 ;
     RECT  52.236 6.655 52.254 6.941 ;
     RECT  63.864 6.853 64.746 6.953 ;
     RECT  42.915 2.413 43.197 6.961 ;
     RECT  44.244 5.495 44.262 6.961 ;
     RECT  45.615 6.941 46.386 7.051 ;
     RECT  4.032 6.809 16.65 7.079 ;
     RECT  33.912 6.881 38.142 7.079 ;
     RECT  0.108 6.893 0.198 7.085 ;
     RECT  33.912 7.079 33.93 7.115 ;
     RECT  0.18 7.085 0.198 7.133 ;
     RECT  53.64 6.893 54.846 7.181 ;
     RECT  51.015 5.999 51.297 7.195 ;
     RECT  63.864 6.953 64.638 7.195 ;
     RECT  2.304 6.509 3.258 7.231 ;
     RECT  4.032 7.079 8.298 7.231 ;
     RECT  38.916 6.881 38.934 7.259 ;
     RECT  51.015 7.195 51.966 7.349 ;
     RECT  54.72 7.181 54.846 7.373 ;
     RECT  51.015 7.349 51.822 7.385 ;
     RECT  45.615 7.051 46.782 7.393 ;
     RECT  34.668 7.079 38.142 7.421 ;
     RECT  61.02 6.539 61.038 7.429 ;
     RECT  61.815 6.655 62.442 7.429 ;
     RECT  18.144 6.809 33.102 7.465 ;
     RECT  42.915 6.961 44.262 7.529 ;
     RECT  2.304 7.231 8.298 7.565 ;
     RECT  18.144 7.465 33.246 7.619 ;
     RECT  42.915 7.529 43.902 7.619 ;
     RECT  2.34 7.565 8.298 7.661 ;
     RECT  55.044 7.723 55.206 7.735 ;
     RECT  9.144 7.079 16.65 7.765 ;
     RECT  17.46 7.723 17.694 7.765 ;
     RECT  61.02 7.429 62.442 7.771 ;
     RECT  63.288 7.195 64.638 7.771 ;
     RECT  34.668 7.421 37.797 7.861 ;
     RECT  41.688 6.853 41.778 7.889 ;
     RECT  61.02 7.771 64.638 7.889 ;
     RECT  45.615 7.393 47.286 7.925 ;
     RECT  55.044 7.735 55.422 7.949 ;
     RECT  58.716 6.817 59.85 7.961 ;
     RECT  2.412 7.661 8.298 7.963 ;
     RECT  47.268 7.925 47.286 8.005 ;
     RECT  0.54 7.933 0.558 8.011 ;
     RECT  18.432 7.619 33.246 8.041 ;
     RECT  34.236 7.861 37.797 8.041 ;
     RECT  53.64 7.181 53.997 8.041 ;
     RECT  0.54 8.011 0.666 8.107 ;
     RECT  0.54 8.107 0.702 8.131 ;
     RECT  2.412 7.963 8.334 8.131 ;
     RECT  9.144 7.765 17.694 8.131 ;
     RECT  59.115 7.961 59.85 8.131 ;
     RECT  61.38 7.889 64.638 8.155 ;
     RECT  2.412 8.131 17.694 8.159 ;
     RECT  47.268 8.005 47.322 8.159 ;
     RECT  55.26 7.949 55.422 8.159 ;
     RECT  0.54 8.131 0.774 8.189 ;
     RECT  59.115 8.131 60.174 8.195 ;
     RECT  61.38 8.155 64.746 8.195 ;
     RECT  51.015 7.385 51.297 8.203 ;
     RECT  0.54 8.189 0.666 8.237 ;
     RECT  60.156 8.195 60.174 8.237 ;
     RECT  61.38 8.195 64.674 8.237 ;
     RECT  55.26 8.159 55.278 8.24 ;
     RECT  47.268 8.159 47.286 8.303 ;
     RECT  41.688 7.889 41.706 8.311 ;
     RECT  53.604 8.041 53.997 8.311 ;
     RECT  2.412 8.159 2.697 8.395 ;
     RECT  3.42 8.159 17.694 8.429 ;
     RECT  41.544 8.311 41.706 8.429 ;
     RECT  50.868 8.203 51.297 8.443 ;
     RECT  57.744 8.437 57.762 8.443 ;
     RECT  41.544 8.429 41.562 8.465 ;
     RECT  57.564 8.443 57.762 8.477 ;
     RECT  45.615 7.925 46.278 8.491 ;
     RECT  4.248 8.429 17.694 8.537 ;
     RECT  57.564 8.477 57.582 8.537 ;
     RECT  4.248 8.537 8.334 8.573 ;
     RECT  50.724 8.443 51.297 8.573 ;
     RECT  45.144 8.491 46.278 8.581 ;
     RECT  49.5 8.545 49.518 8.581 ;
     RECT  2.376 8.395 2.697 8.683 ;
     RECT  49.392 8.581 49.518 8.699 ;
     RECT  9.072 8.537 17.694 8.735 ;
     RECT  49.392 8.699 49.41 8.735 ;
     RECT  0.144 8.587 0.162 8.765 ;
     RECT  4.248 8.573 8.298 8.813 ;
     RECT  61.38 8.237 64.638 8.813 ;
     RECT  61.38 8.813 63.954 8.843 ;
     RECT  18.432 8.041 37.797 8.969 ;
     RECT  44.496 8.581 46.278 8.969 ;
     RECT  54.792 8.743 54.81 8.969 ;
     RECT  44.964 8.969 46.278 8.977 ;
     RECT  60.624 8.473 60.642 8.977 ;
     RECT  9.072 8.735 17.118 9.041 ;
     RECT  2.304 8.683 2.697 9.067 ;
     RECT  3.42 8.429 3.474 9.067 ;
     RECT  44.964 8.977 46.782 9.077 ;
     RECT  18.432 8.969 33.138 9.113 ;
     RECT  48.315 5.189 48.597 9.121 ;
     RECT  44.964 9.077 46.278 9.239 ;
     RECT  48.315 9.121 48.654 9.239 ;
     RECT  53.28 8.311 53.997 9.239 ;
     RECT  2.304 9.067 3.474 9.259 ;
     RECT  4.248 8.813 8.154 9.259 ;
     RECT  38.772 9.211 38.79 9.341 ;
     RECT  18.432 9.113 33.03 9.391 ;
     RECT  60.624 8.977 61.074 9.509 ;
     RECT  61.815 8.843 63.954 9.581 ;
     RECT  2.304 9.259 8.154 9.589 ;
     RECT  9.288 9.041 17.118 9.661 ;
     RECT  17.856 9.391 33.03 9.661 ;
     RECT  60.696 9.509 61.074 9.661 ;
     RECT  61.815 9.581 63.342 9.661 ;
     RECT  9.288 9.661 33.03 9.689 ;
     RECT  64.656 9.739 64.674 9.787 ;
     RECT  45.108 9.239 46.278 9.821 ;
     RECT  34.236 8.969 37.797 9.895 ;
     RECT  0.144 9.499 0.162 9.917 ;
     RECT  2.304 9.589 8.514 9.923 ;
     RECT  64.656 9.787 64.746 9.923 ;
     RECT  64.656 9.923 64.674 9.965 ;
     RECT  7.416 9.923 8.514 10.021 ;
     RECT  9.288 9.689 17.334 10.021 ;
     RECT  45.615 9.821 46.278 10.049 ;
     RECT  60.696 9.661 63.342 10.049 ;
     RECT  18.324 9.689 33.03 10.057 ;
     RECT  33.984 9.895 37.797 10.057 ;
     RECT  59.115 8.195 59.397 10.057 ;
     RECT  7.416 10.021 17.334 10.109 ;
     RECT  0.324 10.027 0.342 10.157 ;
     RECT  46.764 10.057 46.782 10.157 ;
     RECT  42.915 7.619 43.197 10.171 ;
     RECT  2.304 9.923 6.642 10.193 ;
     RECT  2.304 10.193 6.354 10.219 ;
     RECT  58.716 10.057 59.397 10.229 ;
     RECT  7.416 10.109 17.118 10.319 ;
     RECT  61.272 10.049 63.342 10.319 ;
     RECT  48.315 9.239 48.597 10.471 ;
     RECT  51.015 8.573 51.297 10.471 ;
     RECT  53.715 9.239 53.997 10.471 ;
     RECT  2.268 10.219 6.354 10.499 ;
     RECT  61.38 10.319 63.342 10.507 ;
     RECT  42.915 10.171 43.254 10.561 ;
     RECT  48.06 10.471 48.597 10.589 ;
     RECT  61.38 10.507 63.882 10.589 ;
     RECT  42.3 10.561 43.254 10.597 ;
     RECT  53.64 10.471 53.997 10.597 ;
     RECT  38.772 10.561 38.79 10.661 ;
     RECT  53.424 10.597 53.997 10.669 ;
     RECT  18.324 10.057 37.797 10.685 ;
     RECT  61.56 10.589 63.882 10.685 ;
     RECT  53.352 10.669 53.997 10.699 ;
     RECT  41.832 10.597 43.254 10.705 ;
     RECT  41.832 10.705 43.902 10.741 ;
     RECT  2.304 10.499 6.354 10.769 ;
     RECT  29.088 10.685 37.797 10.769 ;
     RECT  41.832 10.741 44.226 10.769 ;
     RECT  42.804 10.769 44.226 10.859 ;
     RECT  52.632 10.699 53.997 10.859 ;
     RECT  40.215 6.449 40.497 10.867 ;
     RECT  52.632 10.859 52.65 10.895 ;
     RECT  40.215 10.867 40.626 11.003 ;
     RECT  59.112 10.229 59.397 11.101 ;
     RECT  64.656 11.083 64.674 11.101 ;
     RECT  7.416 10.319 17.046 11.129 ;
     RECT  38.808 10.669 39.366 11.129 ;
     RECT  64.656 11.101 64.746 11.129 ;
     RECT  50.724 10.471 51.297 11.131 ;
     RECT  44.208 10.859 44.226 11.137 ;
     RECT  40.215 11.003 40.554 11.165 ;
     RECT  44.208 11.137 44.406 11.165 ;
     RECT  55.116 11.011 55.134 11.165 ;
     RECT  64.728 11.129 64.746 11.165 ;
     RECT  54.756 11.173 54.774 11.179 ;
     RECT  15.876 11.129 17.046 11.209 ;
     RECT  44.388 11.165 44.406 11.237 ;
     RECT  54.72 11.179 54.774 11.273 ;
     RECT  58.716 11.101 59.742 11.273 ;
     RECT  61.56 10.685 62.334 11.399 ;
     RECT  18.324 10.685 28.35 11.407 ;
     RECT  15.876 11.209 17.082 11.419 ;
     RECT  18.324 11.407 28.674 11.419 ;
     RECT  48.276 10.589 48.597 11.435 ;
     RECT  50.184 11.131 51.297 11.435 ;
     RECT  63.288 10.685 63.882 11.443 ;
     RECT  2.415 10.769 6.354 11.479 ;
     RECT  7.416 11.129 15.066 11.479 ;
     RECT  15.876 11.419 28.674 11.551 ;
     RECT  29.415 10.769 37.797 11.551 ;
     RECT  2.415 11.479 15.066 11.579 ;
     RECT  15.876 11.551 37.797 11.669 ;
     RECT  34.632 11.669 37.797 11.705 ;
     RECT  63.288 11.443 63.918 11.713 ;
     RECT  49.32 11.515 49.338 11.749 ;
     RECT  61.815 11.399 62.334 11.755 ;
     RECT  63.288 11.713 63.954 11.755 ;
     RECT  46.764 11.443 46.782 11.785 ;
     RECT  50.472 11.435 51.297 11.785 ;
     RECT  40.215 11.165 40.497 11.821 ;
     RECT  52.344 11.785 52.362 11.821 ;
     RECT  54.72 11.273 54.738 11.837 ;
     RECT  61.815 11.755 63.954 11.885 ;
     RECT  37.515 11.705 37.797 11.911 ;
     RECT  15.876 11.669 33.894 11.939 ;
     RECT  34.632 11.705 36.306 11.939 ;
     RECT  49.32 11.749 49.482 11.939 ;
     RECT  42.804 10.859 43.197 11.947 ;
     RECT  49.32 11.939 49.446 11.975 ;
     RECT  52.344 11.821 52.506 11.975 ;
     RECT  46.764 11.785 46.818 12.091 ;
     RECT  53.715 10.859 53.997 12.217 ;
     RECT  39.924 11.821 40.497 12.245 ;
     RECT  42.588 11.947 43.197 12.245 ;
     RECT  3.672 11.579 15.066 12.253 ;
     RECT  15.876 11.939 17.118 12.253 ;
     RECT  61.815 11.885 62.514 12.281 ;
     RECT  42.696 12.245 43.197 12.317 ;
     RECT  53.715 12.217 54.666 12.317 ;
     RECT  56.415 2.413 56.697 12.325 ;
     RECT  3.672 12.253 17.118 12.331 ;
     RECT  60.624 11.707 60.642 12.331 ;
     RECT  50.472 11.785 51.354 12.361 ;
     RECT  40.215 12.245 40.497 12.451 ;
     RECT  55.872 12.325 56.697 12.475 ;
     RECT  18.108 11.939 33.894 12.479 ;
     RECT  42.768 12.317 43.197 12.479 ;
     RECT  46.764 12.091 46.926 12.479 ;
     RECT  50.436 12.361 51.354 12.479 ;
     RECT  22.788 12.479 33.894 12.487 ;
     RECT  34.632 11.939 36.234 12.487 ;
     RECT  46.764 12.479 46.818 12.515 ;
     RECT  49.428 11.975 49.446 12.515 ;
     RECT  55.764 12.475 56.697 12.515 ;
     RECT  60.3 12.331 60.642 12.515 ;
     RECT  37.515 11.911 37.818 12.523 ;
     RECT  45.615 10.049 45.897 12.523 ;
     RECT  22.788 12.487 36.234 12.551 ;
     RECT  63.288 11.885 63.954 12.557 ;
     RECT  60.552 12.515 60.642 12.631 ;
     RECT  37.515 12.523 37.89 12.653 ;
     RECT  38.772 11.707 38.79 12.653 ;
     RECT  40.215 12.451 41.022 12.721 ;
     RECT  60.552 12.631 60.858 12.749 ;
     RECT  3.42 12.331 17.118 12.757 ;
     RECT  18.108 12.479 22.05 12.757 ;
     RECT  23.148 12.551 36.234 12.785 ;
     RECT  50.472 12.479 51.354 12.785 ;
     RECT  3.42 12.757 22.05 12.821 ;
     RECT  54.72 12.721 54.738 12.821 ;
     RECT  36.216 12.785 36.234 12.829 ;
     RECT  50.508 12.785 51.354 12.829 ;
     RECT  52.884 12.361 52.902 12.865 ;
     RECT  40.215 12.721 41.382 12.901 ;
     RECT  52.848 12.865 52.902 12.991 ;
     RECT  36.216 12.829 36.558 13.019 ;
     RECT  50.508 12.829 51.858 13.019 ;
     RECT  60.552 12.749 60.57 13.019 ;
     RECT  61.815 12.281 62.442 13.019 ;
     RECT  63.288 12.557 63.918 13.019 ;
     RECT  36.216 13.019 36.45 13.055 ;
     RECT  40.215 12.901 41.634 13.055 ;
     RECT  45.615 12.523 46.35 13.055 ;
     RECT  52.596 12.991 52.902 13.055 ;
     RECT  63.288 13.019 63.882 13.055 ;
     RECT  48.315 11.435 48.597 13.063 ;
     RECT  23.328 12.785 35.334 13.085 ;
     RECT  33.66 13.085 35.334 13.091 ;
     RECT  52.596 13.055 52.866 13.091 ;
     RECT  63.324 13.055 63.882 13.091 ;
     RECT  52.848 13.091 52.866 13.127 ;
     RECT  50.508 13.019 51.297 13.199 ;
     RECT  3.42 12.821 21.597 13.229 ;
     RECT  55.872 12.515 56.697 13.289 ;
     RECT  2.415 11.579 2.697 13.297 ;
     RECT  3.42 13.229 13.698 13.297 ;
     RECT  33.696 13.091 35.298 13.325 ;
     RECT  48.315 13.063 49.05 13.325 ;
     RECT  63.324 13.091 63.342 13.325 ;
     RECT  42.915 12.479 43.197 13.369 ;
     RECT  41.616 13.055 41.634 13.397 ;
     RECT  46.728 13.297 46.746 13.397 ;
     RECT  58.716 11.273 59.397 13.433 ;
     RECT  14.472 13.229 21.597 13.469 ;
     RECT  42.768 13.369 43.197 13.469 ;
     RECT  14.508 13.469 21.597 13.559 ;
     RECT  23.328 13.085 32.814 13.567 ;
     RECT  14.508 13.559 18.897 13.595 ;
     RECT  36.216 13.055 36.234 13.595 ;
     RECT  19.764 13.559 21.597 13.667 ;
     RECT  20.196 13.667 21.597 13.711 ;
     RECT  14.508 13.595 17.694 13.739 ;
     RECT  22.824 13.567 32.814 13.739 ;
     RECT  36.144 13.603 36.162 13.739 ;
     RECT  14.508 13.739 17.226 13.865 ;
     RECT  20.196 13.711 21.906 13.865 ;
     RECT  14.652 13.865 17.226 13.937 ;
     RECT  20.232 13.865 21.906 13.981 ;
     RECT  22.824 13.739 27.234 13.981 ;
     RECT  14.868 13.937 17.226 14.009 ;
     RECT  14.976 14.009 17.226 14.099 ;
     RECT  15.228 14.099 17.226 14.252 ;
     RECT  40.215 13.055 40.77 14.279 ;
     RECT  28.224 13.739 32.814 14.285 ;
     RECT  20.232 13.981 27.234 14.429 ;
     RECT  15.372 14.252 17.226 14.491 ;
     RECT  18.432 13.595 18.897 14.521 ;
     RECT  18.324 14.521 19.494 14.611 ;
     RECT  20.232 14.429 27.198 14.611 ;
     RECT  15.372 14.491 17.262 14.755 ;
     RECT  60.804 14.521 60.822 14.755 ;
     RECT  15.372 14.755 17.514 15.025 ;
     RECT  18.324 14.611 27.198 15.025 ;
     RECT  34.488 13.325 35.298 15.025 ;
     RECT  14.616 14.875 14.634 15.061 ;
     RECT  15.372 15.025 27.198 15.061 ;
     RECT  2.415 13.297 13.698 15.179 ;
     RECT  14.616 15.061 27.198 15.187 ;
     RECT  28.332 14.285 32.814 15.187 ;
     RECT  33.696 13.325 33.714 15.187 ;
     RECT  2.415 15.179 9.27 15.215 ;
     RECT  3.456 15.215 9.27 15.287 ;
     RECT  14.616 15.187 27.234 15.295 ;
     RECT  14.616 15.295 27.594 15.307 ;
     RECT  28.332 15.187 33.714 15.307 ;
     RECT  14.616 15.307 33.714 15.331 ;
     RECT  34.452 15.025 35.298 15.331 ;
     RECT  9.252 15.287 9.27 15.389 ;
     RECT  14.616 15.331 35.298 15.457 ;
     RECT  3.456 15.287 8.514 15.485 ;
     RECT  14.616 15.457 35.442 15.499 ;
     RECT  14.616 15.499 35.514 15.529 ;
     RECT  10.188 15.179 13.698 15.601 ;
     RECT  14.508 15.529 35.514 15.601 ;
     RECT  45.615 13.055 45.897 15.601 ;
     RECT  60.516 14.755 60.822 15.601 ;
     RECT  42.915 13.469 43.197 15.727 ;
     RECT  45.615 15.601 46.314 15.755 ;
     RECT  42.915 15.727 43.902 15.763 ;
     RECT  61.815 13.019 62.097 15.763 ;
     RECT  60.516 15.601 61.074 15.799 ;
     RECT  61.815 15.763 62.406 15.799 ;
     RECT  42.804 15.763 43.902 15.863 ;
     RECT  10.188 15.601 35.514 15.961 ;
     RECT  3.492 15.485 3.51 16.025 ;
     RECT  4.428 15.485 8.514 16.061 ;
     RECT  36.468 16.069 36.486 16.141 ;
     RECT  37.515 12.653 37.797 16.141 ;
     RECT  4.428 16.061 8.406 16.295 ;
     RECT  9.54 15.961 35.514 16.411 ;
     RECT  36.468 16.141 37.797 16.411 ;
     RECT  9.288 16.411 37.797 16.589 ;
     RECT  45.615 15.755 45.897 16.681 ;
     RECT  28.476 16.589 37.797 16.799 ;
     RECT  59.115 13.433 59.397 16.807 ;
     RECT  47.124 16.645 47.142 16.843 ;
     RECT  3.6 16.681 3.618 16.891 ;
     RECT  58.716 16.807 59.397 16.907 ;
     RECT  3.42 16.891 3.618 16.915 ;
     RECT  4.428 16.295 6.858 16.915 ;
     RECT  47.088 16.843 47.142 16.915 ;
     RECT  2.415 15.215 2.697 16.951 ;
     RECT  3.42 16.915 6.858 16.951 ;
     RECT  7.815 16.295 8.406 16.987 ;
     RECT  9.288 16.589 27.666 16.987 ;
     RECT  0.54 16.951 0.558 17.041 ;
     RECT  28.512 16.799 37.797 17.069 ;
     RECT  36.432 17.069 37.797 17.105 ;
     RECT  7.815 16.987 27.666 17.117 ;
     RECT  2.415 16.951 6.858 17.311 ;
     RECT  46.944 16.915 47.142 17.375 ;
     RECT  42.915 15.863 43.902 17.455 ;
     RECT  2.304 17.311 6.858 17.467 ;
     RECT  28.512 17.069 35.694 17.483 ;
     RECT  36.72 17.105 37.797 17.491 ;
     RECT  9.144 17.117 27.666 17.519 ;
     RECT  28.512 17.483 35.586 17.549 ;
     RECT  36.72 17.491 38.466 17.581 ;
     RECT  42.444 17.455 43.902 17.609 ;
     RECT  60.516 15.799 62.406 17.609 ;
     RECT  48.315 13.325 48.597 17.617 ;
     RECT  0.504 17.041 0.558 17.645 ;
     RECT  2.304 17.467 7.038 17.653 ;
     RECT  7.815 17.117 8.406 17.653 ;
     RECT  15.84 17.519 27.666 17.681 ;
     RECT  29.415 17.549 35.586 17.681 ;
     RECT  36.72 17.581 38.646 17.689 ;
     RECT  40.215 14.279 40.497 17.689 ;
     RECT  15.915 17.681 27.666 17.761 ;
     RECT  28.512 17.549 28.638 17.761 ;
     RECT  2.304 17.653 8.406 17.851 ;
     RECT  9.144 17.519 14.994 17.851 ;
     RECT  15.915 17.761 28.638 17.879 ;
     RECT  42.444 17.609 43.197 17.959 ;
     RECT  36.72 17.689 40.497 17.995 ;
     RECT  60.768 17.609 62.406 18.149 ;
     RECT  20.592 17.879 28.638 18.301 ;
     RECT  29.415 17.681 35.514 18.301 ;
     RECT  36.54 17.995 40.497 18.301 ;
     RECT  36.432 18.301 40.497 18.427 ;
     RECT  20.592 18.301 35.514 18.499 ;
     RECT  36.252 18.427 40.497 18.499 ;
     RECT  0.54 17.645 0.558 18.523 ;
     RECT  20.592 18.499 40.497 18.571 ;
     RECT  50.184 18.031 50.202 18.571 ;
     RECT  51.015 13.199 51.297 18.571 ;
     RECT  0.54 18.523 0.63 18.599 ;
     RECT  2.304 17.851 14.994 18.661 ;
     RECT  15.915 17.879 19.782 18.661 ;
     RECT  20.592 18.571 40.806 18.661 ;
     RECT  2.304 18.661 40.806 18.689 ;
     RECT  2.304 18.689 8.262 18.725 ;
     RECT  9.108 18.689 40.806 18.797 ;
     RECT  9.108 18.797 40.59 18.869 ;
     RECT  60.768 18.149 62.334 19.003 ;
     RECT  9.504 18.869 40.59 19.031 ;
     RECT  45.504 16.681 45.897 19.075 ;
     RECT  47.124 17.375 47.142 19.075 ;
     RECT  60.768 19.003 62.37 19.075 ;
     RECT  47.016 19.075 47.142 19.201 ;
     RECT  48.204 17.617 48.597 19.201 ;
     RECT  0.54 18.599 0.558 19.243 ;
     RECT  42.3 17.959 43.197 19.273 ;
     RECT  2.304 18.725 8.19 19.288 ;
     RECT  2.304 19.288 2.826 19.301 ;
     RECT  9.648 19.031 40.59 19.301 ;
     RECT  45.396 19.075 45.897 19.373 ;
     RECT  47.016 19.201 48.597 19.373 ;
     RECT  9.648 19.301 17.694 19.499 ;
     RECT  18.615 19.301 40.59 19.543 ;
     RECT  0.108 19.243 0.558 19.565 ;
     RECT  3.852 19.288 8.19 19.579 ;
     RECT  0.108 19.565 0.234 19.58 ;
     RECT  60.768 19.075 62.658 19.615 ;
     RECT  18.615 19.543 40.626 19.643 ;
     RECT  48.204 19.373 48.597 19.643 ;
     RECT  3.852 19.579 8.226 19.769 ;
     RECT  60.768 19.615 62.694 19.769 ;
     RECT  6.768 19.769 8.226 19.885 ;
     RECT  6.768 19.885 8.298 19.913 ;
     RECT  50.184 18.571 51.297 20.039 ;
     RECT  9.936 19.499 17.694 20.047 ;
     RECT  2.304 19.301 2.697 20.048 ;
     RECT  9.936 20.047 17.766 20.075 ;
     RECT  18.615 19.643 28.602 20.075 ;
     RECT  18.615 20.075 28.53 20.083 ;
     RECT  59.115 16.907 59.397 20.083 ;
     RECT  63.864 19.885 63.882 20.083 ;
     RECT  18.54 20.083 28.53 20.147 ;
     RECT  55.224 20.107 55.242 20.149 ;
     RECT  56.415 13.289 56.697 20.149 ;
     RECT  12.78 20.075 17.766 20.155 ;
     RECT  55.224 20.149 56.697 20.155 ;
     RECT  58.716 20.083 59.397 20.183 ;
     RECT  3.852 19.769 5.994 20.191 ;
     RECT  29.376 19.643 40.626 20.191 ;
     RECT  41.724 19.273 43.197 20.191 ;
     RECT  60.948 19.769 62.694 20.219 ;
     RECT  2.412 20.048 2.697 20.281 ;
     RECT  50.472 20.039 51.297 20.309 ;
     RECT  45.615 19.373 45.897 20.317 ;
     RECT  46.656 20.011 46.782 20.317 ;
     RECT  55.116 20.155 56.697 20.333 ;
     RECT  2.412 20.281 2.862 20.347 ;
     RECT  6.84 19.913 8.298 20.395 ;
     RECT  61.02 20.219 62.694 20.395 ;
     RECT  63.864 20.083 63.99 20.395 ;
     RECT  9.936 20.075 11.862 20.417 ;
     RECT  29.376 20.191 43.197 20.417 ;
     RECT  9.144 19.849 9.162 20.425 ;
     RECT  9.936 20.417 11.682 20.425 ;
     RECT  12.78 20.155 17.802 20.453 ;
     RECT  0.144 19.58 0.234 20.461 ;
     RECT  41.616 20.417 43.197 20.489 ;
     RECT  55.116 20.333 55.674 20.525 ;
     RECT  2.412 20.347 2.97 20.539 ;
     RECT  3.744 20.191 5.994 20.539 ;
     RECT  15.408 20.453 17.802 20.623 ;
     RECT  18.54 20.147 27.774 20.623 ;
     RECT  2.412 20.539 5.994 20.731 ;
     RECT  6.84 20.395 8.334 20.731 ;
     RECT  9.144 20.425 11.682 20.849 ;
     RECT  29.376 20.417 40.77 20.849 ;
     RECT  45.615 20.317 46.782 20.849 ;
     RECT  15.408 20.623 27.774 20.893 ;
     RECT  28.512 20.147 28.53 20.893 ;
     RECT  0.144 20.461 0.558 20.929 ;
     RECT  46.764 20.849 46.782 20.957 ;
     RECT  2.412 20.731 8.334 20.971 ;
     RECT  2.304 20.971 8.334 21.091 ;
     RECT  9.144 20.849 11.322 21.091 ;
     RECT  53.715 12.317 53.997 21.091 ;
     RECT  15.408 20.893 28.53 21.119 ;
     RECT  41.616 20.489 41.85 21.119 ;
     RECT  55.656 20.525 55.674 21.119 ;
     RECT  39.348 20.849 40.77 21.163 ;
     RECT  41.616 21.119 41.742 21.163 ;
     RECT  53.352 21.091 53.997 21.163 ;
     RECT  53.208 21.163 53.997 21.2 ;
     RECT  2.304 21.091 11.322 21.211 ;
     RECT  15.84 21.119 28.53 21.235 ;
     RECT  29.376 20.849 38.61 21.235 ;
     RECT  42.768 20.489 43.197 21.271 ;
     RECT  42.768 21.271 43.686 21.299 ;
     RECT  42.915 21.299 43.686 21.389 ;
     RECT  12.78 20.453 14.67 21.397 ;
     RECT  53.715 21.2 53.997 21.397 ;
     RECT  12.204 21.397 14.67 21.433 ;
     RECT  61.02 20.395 63.99 21.505 ;
     RECT  60.948 21.505 63.99 21.533 ;
     RECT  60.948 21.533 62.838 21.541 ;
     RECT  2.268 21.211 11.322 21.659 ;
     RECT  60.588 21.541 62.838 21.659 ;
     RECT  12.204 21.433 15.066 21.667 ;
     RECT  0.108 20.929 0.558 21.773 ;
     RECT  15.84 21.235 38.61 21.811 ;
     RECT  39.348 21.163 41.742 21.811 ;
     RECT  53.715 21.397 54.27 21.929 ;
     RECT  51.015 20.309 51.297 21.973 ;
     RECT  52.92 21.973 52.938 21.979 ;
     RECT  51.015 21.973 51.822 22.027 ;
     RECT  52.668 21.979 52.938 22.027 ;
     RECT  63.864 21.533 63.99 22.037 ;
     RECT  11.736 21.667 15.066 22.045 ;
     RECT  15.84 21.811 41.742 22.045 ;
     RECT  51.015 22.027 52.938 22.073 ;
     RECT  2.268 21.659 3.366 22.123 ;
     RECT  60.732 21.659 62.838 22.157 ;
     RECT  2.16 22.123 3.366 22.199 ;
     RECT  51.015 22.073 51.75 22.199 ;
     RECT  4.14 21.659 8.37 22.235 ;
     RECT  11.736 22.045 41.742 22.235 ;
     RECT  28.44 22.235 41.742 22.253 ;
     RECT  51.015 22.199 51.606 22.349 ;
     RECT  42.915 21.389 43.197 22.351 ;
     RECT  52.668 22.073 52.938 22.351 ;
     RECT  60.732 22.157 62.802 22.379 ;
     RECT  63.972 22.037 63.99 22.411 ;
     RECT  63.972 22.411 64.674 22.441 ;
     RECT  49.608 20.389 49.626 22.469 ;
     RECT  63.972 22.441 64.746 22.469 ;
     RECT  64.728 22.469 64.746 22.493 ;
     RECT  28.584 22.253 41.742 22.505 ;
     RECT  52.668 22.351 52.974 22.505 ;
     RECT  7.02 22.235 8.37 22.513 ;
     RECT  51.015 22.349 51.297 22.513 ;
     RECT  7.02 22.513 8.406 22.549 ;
     RECT  9.144 21.659 10.962 22.549 ;
     RECT  45.615 20.849 45.897 22.549 ;
     RECT  46.764 22.507 46.782 22.549 ;
     RECT  52.956 22.505 52.974 22.585 ;
     RECT  53.715 21.929 53.997 22.585 ;
     RECT  7.02 22.549 10.962 22.621 ;
     RECT  59.115 20.183 59.397 22.621 ;
     RECT  45.615 22.549 46.782 22.637 ;
     RECT  63.972 22.469 63.99 22.783 ;
     RECT  28.728 22.505 41.742 22.855 ;
     RECT  2.304 22.199 3.366 22.891 ;
     RECT  4.14 22.235 6.246 22.891 ;
     RECT  28.728 22.855 41.922 22.891 ;
     RECT  42.768 22.351 43.197 22.891 ;
     RECT  0.54 21.773 0.558 22.925 ;
     RECT  52.956 22.585 53.997 22.987 ;
     RECT  54.72 22.507 54.738 22.987 ;
     RECT  7.02 22.621 11.178 23.009 ;
     RECT  28.728 22.891 43.197 23.009 ;
     RECT  42.588 23.009 43.197 23.081 ;
     RECT  2.304 22.891 6.246 23.117 ;
     RECT  58.716 22.621 59.397 23.131 ;
     RECT  28.728 23.009 41.454 23.153 ;
     RECT  2.415 23.117 6.246 23.161 ;
     RECT  7.416 23.009 11.178 23.161 ;
     RECT  12.024 22.235 27.63 23.161 ;
     RECT  61.815 22.379 62.802 23.161 ;
     RECT  63.9 22.783 63.99 23.161 ;
     RECT  52.956 22.987 54.738 23.165 ;
     RECT  58.716 23.131 59.454 23.189 ;
     RECT  45.615 22.637 46.206 23.279 ;
     RECT  52.164 23.089 52.182 23.279 ;
     RECT  52.956 23.165 54.702 23.279 ;
     RECT  60.732 22.379 60.75 23.279 ;
     RECT  52.956 23.279 52.974 23.287 ;
     RECT  0.324 23.179 0.342 23.309 ;
     RECT  61.815 23.161 63.99 23.309 ;
     RECT  61.815 23.309 63.918 23.351 ;
     RECT  42.624 23.081 43.197 23.459 ;
     RECT  7.416 23.161 27.63 23.521 ;
     RECT  52.308 23.287 52.974 23.597 ;
     RECT  7.416 23.521 27.918 23.629 ;
     RECT  28.728 23.153 40.698 23.629 ;
     RECT  53.712 23.279 54.702 23.645 ;
     RECT  45.615 23.279 45.897 23.665 ;
     RECT  52.308 23.597 52.47 23.693 ;
     RECT  56.415 20.333 56.697 23.701 ;
     RECT  52.452 23.693 52.47 23.729 ;
     RECT  41.436 23.153 41.454 23.819 ;
     RECT  56.052 23.701 56.697 23.819 ;
     RECT  58.716 23.189 59.418 23.819 ;
     RECT  45.324 23.665 45.897 23.855 ;
     RECT  2.415 23.161 6.57 23.891 ;
     RECT  3.96 23.891 6.57 23.899 ;
     RECT  7.416 23.629 40.698 23.899 ;
     RECT  58.716 23.819 59.397 23.899 ;
     RECT  42.768 23.459 43.197 23.927 ;
     RECT  45.54 23.855 45.897 23.927 ;
     RECT  50.724 22.513 51.297 23.927 ;
     RECT  53.715 23.645 54.702 23.927 ;
     RECT  61.815 23.351 63.882 24.061 ;
     RECT  61.488 24.061 63.882 24.088 ;
     RECT  58.14 23.899 59.397 24.097 ;
     RECT  60.408 24.061 60.426 24.097 ;
     RECT  64.728 24.088 64.746 24.097 ;
     RECT  61.38 24.088 63.882 24.125 ;
     RECT  57.924 24.097 59.397 24.173 ;
     RECT  61.488 24.125 63.882 24.173 ;
     RECT  46.764 24.169 46.782 24.205 ;
     RECT  2.415 23.891 2.826 24.233 ;
     RECT  46.656 24.205 46.782 24.241 ;
     RECT  60.3 24.097 60.426 24.269 ;
     RECT  46.656 24.241 46.818 24.359 ;
     RECT  58.14 24.173 59.397 24.359 ;
     RECT  61.815 24.173 63.882 24.431 ;
     RECT  3.96 23.899 40.698 24.503 ;
     RECT  63.288 24.431 63.882 24.503 ;
     RECT  42.915 23.927 43.197 24.511 ;
     RECT  56.415 23.819 56.697 24.571 ;
     RECT  55.872 24.571 56.697 24.619 ;
     RECT  46.656 24.359 46.782 24.664 ;
     RECT  55.692 24.619 56.697 24.665 ;
     RECT  53.715 23.927 53.997 24.667 ;
     RECT  54.72 24.097 54.738 24.667 ;
     RECT  46.62 24.664 46.782 24.701 ;
     RECT  49.428 22.585 49.446 24.701 ;
     RECT  53.715 24.667 54.846 24.701 ;
     RECT  40.215 24.503 40.698 24.781 ;
     RECT  54.828 24.701 54.846 24.797 ;
     RECT  64.656 24.097 64.746 24.809 ;
     RECT  64.656 24.809 64.674 24.845 ;
     RECT  42.915 24.511 43.254 24.871 ;
     RECT  3.96 24.503 37.797 24.907 ;
     RECT  3.672 24.907 37.797 24.971 ;
     RECT  38.592 24.503 39.006 25.037 ;
     RECT  40.215 24.781 41.058 25.043 ;
     RECT  45.615 23.927 45.897 25.051 ;
     RECT  38.592 25.037 38.862 25.079 ;
     RECT  40.215 25.043 41.022 25.079 ;
     RECT  54.9 25.003 54.918 25.141 ;
     RECT  38.592 25.079 38.61 25.169 ;
     RECT  45.072 25.051 45.897 25.177 ;
     RECT  51.015 23.927 51.297 25.177 ;
     RECT  3.672 24.971 28.134 25.195 ;
     RECT  63.324 24.503 63.882 25.195 ;
     RECT  54.9 25.141 55.026 25.205 ;
     RECT  46.764 24.701 46.782 25.213 ;
     RECT  55.008 25.205 55.026 25.229 ;
     RECT  44.892 25.177 45.897 25.277 ;
     RECT  42.915 24.871 43.326 25.285 ;
     RECT  61.815 24.431 62.442 25.291 ;
     RECT  63.324 25.195 63.918 25.291 ;
     RECT  46.764 25.213 47.214 25.313 ;
     RECT  50.652 25.177 51.297 25.313 ;
     RECT  42.804 25.285 43.326 25.321 ;
     RECT  53.715 24.701 54.054 25.435 ;
     RECT  42.804 25.321 43.83 25.483 ;
     RECT  55.296 25.435 55.494 25.519 ;
     RECT  56.415 24.665 56.697 25.519 ;
     RECT  58.716 24.359 59.397 25.547 ;
     RECT  61.815 25.291 63.918 25.547 ;
     RECT  2.415 24.233 2.697 25.555 ;
     RECT  3.564 25.195 28.134 25.555 ;
     RECT  45.216 25.277 45.897 25.555 ;
     RECT  46.764 25.313 46.782 25.555 ;
     RECT  2.415 25.555 28.134 25.583 ;
     RECT  42.804 25.483 44.442 25.583 ;
     RECT  45.216 25.555 46.782 25.613 ;
     RECT  53.715 25.435 54.09 25.613 ;
     RECT  50.724 25.313 51.297 25.619 ;
     RECT  55.296 25.519 56.697 25.619 ;
     RECT  58.752 25.547 59.397 25.619 ;
     RECT  53.715 25.613 54.054 25.709 ;
     RECT  55.656 25.619 56.697 25.717 ;
     RECT  55.656 25.717 57.006 25.745 ;
     RECT  55.764 25.745 57.006 25.753 ;
     RECT  45.216 25.613 46.71 25.757 ;
     RECT  55.764 25.753 57.078 25.757 ;
     RECT  48.315 19.643 48.597 25.816 ;
     RECT  56.415 25.757 57.078 25.819 ;
     RECT  48.315 25.816 49.23 25.853 ;
     RECT  56.415 25.819 57.15 25.889 ;
     RECT  42.804 25.583 43.197 25.951 ;
     RECT  44.316 25.583 44.442 25.979 ;
     RECT  61.815 25.547 63.342 25.997 ;
     RECT  28.872 24.971 37.797 26.015 ;
     RECT  61.815 25.997 62.73 26.093 ;
     RECT  59.115 25.619 59.397 26.107 ;
     RECT  60.408 24.269 60.426 26.107 ;
     RECT  49.356 25.861 49.374 26.123 ;
     RECT  59.115 26.107 60.426 26.123 ;
     RECT  2.415 25.583 21.597 26.159 ;
     RECT  38.736 26.059 38.754 26.159 ;
     RECT  42.768 25.951 43.197 26.159 ;
     RECT  59.115 26.123 59.886 26.159 ;
     RECT  28.872 26.015 36.558 26.249 ;
     RECT  37.332 26.015 37.797 26.249 ;
     RECT  45.216 25.757 45.897 26.285 ;
     RECT  46.692 25.757 46.71 26.285 ;
     RECT  36.396 26.249 36.45 26.333 ;
     RECT  2.415 26.159 14.886 26.357 ;
     RECT  44.316 25.979 44.334 26.393 ;
     RECT  28.872 26.249 35.586 26.519 ;
     RECT  36.396 26.333 36.414 26.519 ;
     RECT  3.672 26.357 14.886 26.555 ;
     RECT  46.8 26.401 46.818 26.699 ;
     RECT  15.915 26.159 21.597 26.761 ;
     RECT  22.392 25.583 28.134 26.761 ;
     RECT  28.872 26.519 35.478 26.761 ;
     RECT  2.415 26.357 2.862 26.789 ;
     RECT  3.672 26.555 9.054 26.789 ;
     RECT  15.915 26.761 35.478 26.789 ;
     RECT  3.672 26.789 9.018 26.861 ;
     RECT  15.915 26.789 26.997 26.905 ;
     RECT  3.672 26.861 8.946 26.933 ;
     RECT  3.672 26.933 8.91 27.059 ;
     RECT  9.792 26.555 14.886 27.059 ;
     RECT  15.804 26.905 26.997 27.059 ;
     RECT  13.176 27.059 14.886 27.067 ;
     RECT  9.792 27.059 12.366 27.095 ;
     RECT  13.176 27.067 14.922 27.095 ;
     RECT  15.804 27.059 25.254 27.095 ;
     RECT  26.208 27.059 26.997 27.095 ;
     RECT  13.215 27.095 14.922 27.139 ;
     RECT  15.804 27.095 18.897 27.203 ;
     RECT  3.852 27.059 8.874 27.239 ;
     RECT  11.736 27.095 12.366 27.239 ;
     RECT  3.852 27.239 8.586 27.329 ;
     RECT  9.792 27.095 10.962 27.329 ;
     RECT  11.808 27.239 12.366 27.329 ;
     RECT  19.656 27.095 25.254 27.329 ;
     RECT  27.756 26.789 35.478 27.329 ;
     RECT  13.215 27.139 15.03 27.365 ;
     RECT  21.204 27.329 23.238 27.365 ;
     RECT  28.476 27.329 35.478 27.365 ;
     RECT  28.476 27.365 33.93 27.401 ;
     RECT  11.808 27.329 12.078 27.437 ;
     RECT  19.656 27.329 20.394 27.437 ;
     RECT  34.776 27.365 35.478 27.445 ;
     RECT  3.852 27.329 6.642 27.473 ;
     RECT  23.976 27.329 25.254 27.509 ;
     RECT  2.415 26.789 2.697 27.557 ;
     RECT  7.815 27.329 8.586 27.557 ;
     RECT  10.515 27.329 10.962 27.557 ;
     RECT  13.215 27.365 14.094 27.557 ;
     RECT  15.915 27.203 18.897 27.557 ;
     RECT  21.315 27.365 21.597 27.557 ;
     RECT  26.715 27.095 26.997 27.557 ;
     RECT  32.115 27.401 33.93 27.557 ;
     RECT  37.515 26.249 37.797 27.557 ;
     RECT  40.215 25.079 40.497 27.557 ;
     RECT  42.915 26.159 43.197 27.557 ;
     RECT  45.615 26.285 45.897 27.557 ;
     RECT  48.315 25.853 48.597 27.557 ;
     RECT  51.015 25.619 51.297 27.557 ;
     RECT  53.715 25.709 53.997 27.557 ;
     RECT  56.415 25.889 56.697 27.557 ;
     RECT  59.115 26.159 59.397 27.557 ;
     RECT  61.815 26.093 62.097 27.557 ;
     RECT  4.572 27.473 6.642 27.599 ;
     RECT  10.707 27.557 10.962 27.599 ;
     RECT  11.808 27.437 12.006 27.599 ;
     RECT  14.868 27.365 15.03 27.599 ;
     RECT  16.056 27.557 18.018 27.599 ;
     RECT  23.076 27.365 23.238 27.599 ;
     RECT  23.976 27.509 25.146 27.599 ;
     RECT  28.476 27.401 31.374 27.599 ;
     RECT  32.307 27.557 33.93 27.599 ;
     RECT  34.776 27.445 35.73 27.599 ;
     RECT  4.608 27.599 5.886 27.635 ;
     RECT  8.007 27.557 8.586 27.635 ;
     RECT  10.707 27.599 10.854 27.635 ;
     RECT  13.407 27.557 14.094 27.635 ;
     RECT  14.868 27.599 14.886 27.635 ;
     RECT  17.46 27.599 17.478 27.635 ;
     RECT  23.076 27.599 23.094 27.635 ;
     RECT  4.608 27.635 5.397 27.671 ;
     RECT  24.207 27.599 25.146 27.671 ;
     RECT  28.476 27.599 31.266 27.671 ;
     RECT  33.48 27.599 33.606 27.707 ;
     RECT  11.988 27.599 12.006 27.743 ;
     RECT  16.056 27.599 16.197 27.743 ;
     RECT  32.307 27.599 32.67 27.743 ;
     RECT  33.48 27.707 33.498 27.743 ;
     RECT  8.007 27.635 8.406 27.779 ;
     RECT  13.407 27.635 13.842 27.779 ;
     RECT  25.128 27.671 25.146 27.779 ;
     RECT  2.607 27.557 2.697 27.827 ;
     RECT  5.307 27.671 5.397 27.827 ;
     RECT  8.007 27.779 8.097 27.827 ;
     RECT  10.707 27.635 10.797 27.827 ;
     RECT  13.407 27.779 13.497 27.827 ;
     RECT  16.107 27.743 16.197 27.827 ;
     RECT  18.807 27.557 18.897 27.827 ;
     RECT  21.507 27.557 21.597 27.827 ;
     RECT  24.207 27.671 24.297 27.827 ;
     RECT  26.907 27.557 26.997 27.827 ;
     RECT  28.476 27.671 29.697 27.827 ;
     RECT  32.307 27.743 32.397 27.827 ;
     RECT  35.007 27.599 35.097 27.827 ;
     RECT  37.707 27.557 37.797 27.827 ;
     RECT  40.407 27.557 40.497 27.827 ;
     RECT  43.107 27.557 43.197 27.827 ;
     RECT  45.807 27.557 45.897 27.827 ;
     RECT  48.507 27.557 48.597 27.827 ;
     RECT  51.207 27.557 51.297 27.827 ;
     RECT  53.907 27.557 53.997 27.827 ;
     RECT  56.607 27.557 56.697 27.827 ;
     RECT  59.307 27.557 59.397 27.827 ;
     RECT  62.007 27.557 62.097 27.827 ;
     RECT  30.492 27.671 30.51 27.869 ;
     RECT  31.248 27.671 31.266 27.869 ;
     RECT  28.476 27.827 28.962 29.899 ;
     RECT  26.784 29.899 26.802 30.029 ;
     RECT  28.404 29.899 28.962 30.043 ;
     RECT  27.936 30.043 28.962 30.173 ;
     RECT  28.332 30.173 28.962 30.179 ;
     RECT  28.35 30.179 28.404 30.18 ;
     RECT  28.422 30.179 28.476 30.18 ;
     RECT  28.494 30.179 28.548 30.18 ;
     RECT  28.566 30.179 28.62 30.18 ;
     RECT  28.638 30.179 28.692 30.18 ;
     RECT  28.71 30.179 28.764 30.18 ;
     RECT  28.782 30.179 28.836 30.18 ;
     RECT  28.854 30.179 28.908 30.18 ;
     RECT  28.926 30.179 28.962 30.18 ;
     RECT  28.35 30.18 28.404 30.204 ;
     RECT  28.422 30.18 28.476 30.204 ;
     RECT  28.494 30.18 28.548 30.204 ;
     RECT  28.566 30.18 28.62 30.204 ;
     RECT  28.638 30.18 28.692 30.204 ;
     RECT  28.71 30.18 28.764 30.204 ;
     RECT  28.782 30.18 28.836 30.204 ;
     RECT  28.854 30.18 28.908 30.204 ;
    LAYER M4 ;
     RECT  0.084 4.176 0.137 4.2 ;
     RECT  0.06 4.2 0.137 4.272 ;
     RECT  0.084 4.272 0.137 4.296 ;
     RECT  0.06 4.296 0.137 4.368 ;
     RECT  0.084 4.368 0.137 4.392 ;
     RECT  0.06 4.392 0.137 4.464 ;
     RECT  0.084 4.464 0.137 4.488 ;
     RECT  0.06 4.488 0.137 4.56 ;
     RECT  0.084 4.56 0.137 4.584 ;
     RECT  0.06 4.584 0.137 4.656 ;
     RECT  0.084 4.656 0.137 4.68 ;
     RECT  0.06 4.68 0.137 4.752 ;
     RECT  0.084 4.752 0.137 4.776 ;
     RECT  0.06 4.776 0.137 4.848 ;
     RECT  0.084 4.848 0.137 4.872 ;
     RECT  0.06 4.872 0.137 4.944 ;
     RECT  0.084 4.944 0.137 4.968 ;
     RECT  0.06 4.968 0.137 5.04 ;
     RECT  0.084 5.04 0.137 5.064 ;
     RECT  0.06 5.064 0.137 5.136 ;
     RECT  0.084 5.136 0.137 5.16 ;
     RECT  0.06 5.16 0.137 5.232 ;
     RECT  0.084 5.232 0.137 5.256 ;
     RECT  0.06 5.256 0.137 5.328 ;
     RECT  0.084 5.328 0.137 5.352 ;
     RECT  0.06 5.352 0.137 5.424 ;
     RECT  0.084 5.424 0.137 5.448 ;
     RECT  0.06 5.448 0.137 5.52 ;
     RECT  0.084 5.52 0.137 5.544 ;
     RECT  0.06 5.544 0.137 5.616 ;
     RECT  0.084 5.616 0.137 5.64 ;
     RECT  0.06 5.64 0.137 5.712 ;
     RECT  0.084 5.712 0.137 5.736 ;
     RECT  0.06 5.736 0.137 5.808 ;
     RECT  0.084 5.808 0.137 5.832 ;
     RECT  0.06 5.832 0.137 5.904 ;
     RECT  0.084 5.904 0.137 5.928 ;
     RECT  0.06 5.928 0.137 6 ;
     RECT  0.084 6 0.137 6.024 ;
     RECT  0.06 6.024 0.137 6.096 ;
     RECT  0.084 6.096 0.137 6.12 ;
     RECT  0.06 6.12 0.137 6.192 ;
     RECT  0.084 6.192 0.137 6.216 ;
     RECT  0.06 6.216 0.137 6.288 ;
     RECT  0.084 6.288 0.137 6.312 ;
     RECT  0.06 6.312 0.137 6.384 ;
     RECT  0.084 6.384 0.137 6.408 ;
     RECT  0.06 6.408 0.137 6.48 ;
     RECT  0.084 6.48 0.137 6.504 ;
     RECT  0.06 6.504 0.137 6.576 ;
     RECT  0.084 6.576 0.137 6.6 ;
     RECT  0.06 6.6 0.137 6.672 ;
     RECT  0.084 6.672 0.137 6.696 ;
     RECT  0.06 6.696 0.137 6.768 ;
     RECT  0.084 6.768 0.137 6.792 ;
     RECT  0.06 6.792 0.137 6.864 ;
     RECT  0.084 6.864 0.137 6.888 ;
     RECT  0.06 6.888 0.137 6.96 ;
     RECT  0.084 6.96 0.137 6.984 ;
     RECT  0.06 6.984 0.137 7.056 ;
     RECT  0.084 7.056 0.137 7.08 ;
     RECT  0.06 7.08 0.137 7.152 ;
     RECT  0.084 7.152 0.137 7.176 ;
     RECT  0.06 7.176 0.137 7.248 ;
     RECT  0.084 7.248 0.137 7.272 ;
     RECT  0.06 7.272 0.137 7.344 ;
     RECT  0.084 7.344 0.137 7.368 ;
     RECT  0.06 7.368 0.137 7.44 ;
     RECT  0.084 7.44 0.137 7.464 ;
     RECT  0.06 7.464 0.137 7.536 ;
     RECT  0.084 7.536 0.137 7.56 ;
     RECT  0.06 7.56 0.137 7.632 ;
     RECT  0.084 7.632 0.137 7.656 ;
     RECT  0.06 7.656 0.137 7.728 ;
     RECT  0.084 7.728 0.137 7.752 ;
     RECT  0.06 7.752 0.137 7.824 ;
     RECT  0.084 7.824 0.137 7.848 ;
     RECT  0.06 7.848 0.137 7.92 ;
     RECT  0.084 7.92 0.137 7.944 ;
     RECT  0.06 7.944 0.137 8.016 ;
     RECT  0.084 8.016 0.137 8.04 ;
     RECT  0.06 8.04 0.137 8.112 ;
     RECT  0.084 8.112 0.137 8.136 ;
     RECT  0.06 8.136 0.137 8.208 ;
     RECT  0.084 8.208 0.137 8.232 ;
     RECT  0.06 8.232 0.137 8.304 ;
     RECT  0.084 8.304 0.137 8.328 ;
     RECT  0.06 8.328 0.137 8.4 ;
     RECT  0.084 8.4 0.137 8.424 ;
     RECT  0.06 8.424 0.137 8.496 ;
     RECT  0.084 8.496 0.137 8.52 ;
     RECT  0.06 8.52 0.137 8.592 ;
     RECT  0.084 8.592 0.137 8.616 ;
     RECT  0.06 8.616 0.137 8.688 ;
     RECT  0.084 8.688 0.137 8.712 ;
     RECT  0.06 8.712 0.137 8.784 ;
     RECT  0.084 8.784 0.137 8.808 ;
     RECT  0.06 8.808 0.137 8.88 ;
     RECT  0.084 8.88 0.137 8.904 ;
     RECT  0.06 8.904 0.137 8.976 ;
     RECT  0.084 8.976 0.137 9 ;
     RECT  0.06 9 0.137 9.072 ;
     RECT  0.084 9.072 0.137 9.096 ;
     RECT  0.06 9.096 0.137 9.168 ;
     RECT  0.084 9.168 0.137 9.192 ;
     RECT  0.06 9.192 0.137 9.264 ;
     RECT  0.084 9.264 0.137 9.288 ;
     RECT  0.06 9.288 0.137 9.36 ;
     RECT  0.084 9.36 0.137 9.384 ;
     RECT  0.06 9.384 0.137 9.456 ;
     RECT  0.084 9.456 0.137 9.48 ;
     RECT  0.06 9.48 0.137 9.552 ;
     RECT  0.084 9.552 0.137 9.576 ;
     RECT  0.06 9.576 0.137 9.648 ;
     RECT  0.084 9.648 0.137 9.672 ;
     RECT  0.06 9.672 0.137 9.744 ;
     RECT  0.084 9.744 0.137 9.768 ;
     RECT  0.06 9.768 0.137 9.84 ;
     RECT  0.084 9.84 0.137 9.864 ;
     RECT  0.06 9.864 0.137 9.936 ;
     RECT  0.084 9.936 0.137 9.96 ;
     RECT  0.06 9.96 0.137 10.032 ;
     RECT  0.084 10.032 0.137 10.056 ;
     RECT  0.06 10.056 0.137 10.128 ;
     RECT  0.084 10.128 0.137 10.152 ;
     RECT  0.06 10.152 0.137 10.224 ;
     RECT  0.084 10.224 0.137 10.248 ;
     RECT  0.137 4.272 0.569 10.248 ;
     RECT  0.084 17.232 0.569 17.256 ;
     RECT  0.06 17.256 0.569 17.328 ;
     RECT  0.084 17.328 0.569 17.352 ;
     RECT  0.06 17.352 0.569 17.424 ;
     RECT  0.084 17.424 0.569 17.448 ;
     RECT  0.06 17.448 0.569 17.52 ;
     RECT  0.084 17.52 0.569 17.544 ;
     RECT  0.06 17.544 0.569 17.616 ;
     RECT  0.084 17.616 0.569 17.64 ;
     RECT  0.06 17.64 0.569 17.712 ;
     RECT  0.084 17.712 0.569 17.736 ;
     RECT  0.06 17.736 0.569 17.808 ;
     RECT  0.084 17.808 0.569 17.832 ;
     RECT  0.06 17.832 0.569 17.904 ;
     RECT  0.084 17.904 0.569 17.928 ;
     RECT  0.06 17.928 0.569 18 ;
     RECT  0.084 18 0.569 18.024 ;
     RECT  0.06 18.024 0.569 18.096 ;
     RECT  0.084 18.096 0.569 18.12 ;
     RECT  0.06 18.12 0.569 18.192 ;
     RECT  0.084 18.192 0.569 18.216 ;
     RECT  0.06 18.216 0.569 18.288 ;
     RECT  0.084 18.288 0.569 18.312 ;
     RECT  0.06 18.312 0.569 18.384 ;
     RECT  0.084 18.384 0.569 18.408 ;
     RECT  0.06 18.408 0.569 18.48 ;
     RECT  0.084 18.48 0.569 18.504 ;
     RECT  0.06 18.504 0.569 18.576 ;
     RECT  0.084 18.576 0.569 18.6 ;
     RECT  0.06 18.6 0.569 18.672 ;
     RECT  0.084 18.672 0.569 18.696 ;
     RECT  0.06 18.696 0.569 18.768 ;
     RECT  0.084 18.768 0.569 18.792 ;
     RECT  0.06 18.792 0.569 18.864 ;
     RECT  0.084 18.864 0.569 18.888 ;
     RECT  0.06 18.888 0.569 18.96 ;
     RECT  0.084 18.96 0.569 18.984 ;
     RECT  0.06 18.984 0.569 19.056 ;
     RECT  0.084 19.056 0.569 19.08 ;
     RECT  0.06 19.08 0.569 19.152 ;
     RECT  0.084 19.152 0.569 19.176 ;
     RECT  0.06 19.176 0.569 19.248 ;
     RECT  0.084 19.248 0.569 19.272 ;
     RECT  0.06 19.272 0.569 19.344 ;
     RECT  0.084 19.344 0.569 19.368 ;
     RECT  0.06 19.368 0.569 19.44 ;
     RECT  0.084 19.44 0.569 19.464 ;
     RECT  0.06 19.464 0.569 19.536 ;
     RECT  0.084 19.536 0.569 19.56 ;
     RECT  0.06 19.56 0.569 19.632 ;
     RECT  0.084 19.632 0.569 19.656 ;
     RECT  0.06 19.656 0.569 19.728 ;
     RECT  0.084 19.728 0.569 19.752 ;
     RECT  0.06 19.752 0.569 19.824 ;
     RECT  0.084 19.824 0.569 19.848 ;
     RECT  0.06 19.848 0.569 19.92 ;
     RECT  0.084 19.92 0.569 19.944 ;
     RECT  0.06 19.944 0.569 20.016 ;
     RECT  0.084 20.016 0.569 20.04 ;
     RECT  0.06 20.04 0.569 20.112 ;
     RECT  0.084 20.112 0.569 20.136 ;
     RECT  0.06 20.136 0.569 20.208 ;
     RECT  0.084 20.208 0.569 20.232 ;
     RECT  0.06 20.232 0.569 20.304 ;
     RECT  0.084 20.304 0.569 20.328 ;
     RECT  0.06 20.328 0.569 20.4 ;
     RECT  0.084 20.4 0.569 20.424 ;
     RECT  0.06 20.424 0.569 20.496 ;
     RECT  0.084 20.496 0.569 20.52 ;
     RECT  0.06 20.52 0.569 20.592 ;
     RECT  0.084 20.592 0.569 20.616 ;
     RECT  0.06 20.616 0.569 20.688 ;
     RECT  0.084 20.688 0.569 20.712 ;
     RECT  0.06 20.712 0.569 20.784 ;
     RECT  0.084 20.784 0.569 20.808 ;
     RECT  0.06 20.808 0.569 20.88 ;
     RECT  0.084 20.88 0.569 20.904 ;
     RECT  0.06 20.904 0.569 20.976 ;
     RECT  0.084 20.976 0.569 21 ;
     RECT  0.06 21 0.569 21.072 ;
     RECT  0.084 21.072 0.569 21.096 ;
     RECT  0.06 21.096 0.569 21.168 ;
     RECT  0.084 21.168 0.569 21.192 ;
     RECT  0.06 21.192 0.569 21.264 ;
     RECT  0.084 21.264 0.569 21.288 ;
     RECT  0.06 21.288 0.569 21.36 ;
     RECT  0.084 21.36 0.569 21.384 ;
     RECT  0.06 21.384 0.569 21.456 ;
     RECT  0.084 21.456 0.569 21.48 ;
     RECT  0.06 21.48 0.569 21.552 ;
     RECT  0.084 21.552 0.569 21.576 ;
     RECT  0.06 21.576 0.569 21.648 ;
     RECT  0.084 21.648 0.569 21.672 ;
     RECT  0.06 21.672 0.569 21.744 ;
     RECT  0.084 21.744 0.569 21.768 ;
     RECT  0.06 21.768 0.569 21.84 ;
     RECT  0.084 21.84 0.569 21.864 ;
     RECT  0.06 21.864 0.569 21.936 ;
     RECT  0.084 21.936 0.569 21.96 ;
     RECT  0.06 21.96 0.569 22.032 ;
     RECT  0.084 22.032 0.569 22.056 ;
     RECT  0.06 22.056 0.569 22.128 ;
     RECT  0.084 22.128 0.569 22.152 ;
     RECT  0.06 22.152 0.569 22.224 ;
     RECT  0.084 22.224 0.569 22.248 ;
     RECT  0.06 22.248 0.569 22.32 ;
     RECT  0.084 22.32 0.569 22.344 ;
     RECT  0.06 22.344 0.569 22.416 ;
     RECT  0.084 22.416 0.569 22.44 ;
     RECT  0.06 22.44 0.569 22.512 ;
     RECT  0.084 22.512 0.569 22.536 ;
     RECT  0.06 22.536 0.569 22.608 ;
     RECT  0.084 22.608 0.569 22.632 ;
     RECT  0.06 22.632 0.569 22.704 ;
     RECT  0.084 22.704 0.569 22.728 ;
     RECT  0.06 22.728 0.569 22.8 ;
     RECT  0.084 22.8 0.569 22.824 ;
     RECT  0.06 22.824 0.569 22.896 ;
     RECT  0.084 22.896 0.569 22.92 ;
     RECT  0.06 22.92 0.569 22.992 ;
     RECT  0.084 22.992 0.569 23.016 ;
     RECT  0.06 23.016 0.569 23.088 ;
     RECT  0.084 23.088 0.569 23.112 ;
     RECT  0.06 23.112 0.569 23.184 ;
     RECT  0.084 23.184 0.569 23.208 ;
     RECT  0.06 23.208 0.569 23.28 ;
     RECT  0.084 23.28 0.569 23.304 ;
     RECT  0.569 4.464 2.408 10.248 ;
     RECT  0.569 17.328 2.408 23.304 ;
     RECT  2.408 2.148 2.512 27.552 ;
     RECT  2.512 2.418 2.6 27.552 ;
     RECT  2.6 2.418 2.704 27.822 ;
     RECT  2.704 12.336 3.053 23.304 ;
     RECT  2.704 2.832 3.377 10.152 ;
     RECT  3.053 12.336 3.413 22.584 ;
     RECT  3.413 15.312 3.491 22.584 ;
     RECT  3.413 12.336 3.521 14.28 ;
     RECT  3.491 15.456 3.532 22.584 ;
     RECT  2.704 25.2 3.877 25.224 ;
     RECT  3.521 12.336 3.949 13.08 ;
     RECT  2.704 26.256 4.025 27.048 ;
     RECT  3.877 25.152 4.525 25.224 ;
     RECT  4.025 26.784 4.741 27.048 ;
     RECT  3.532 16.896 4.777 22.584 ;
     RECT  3.377 2.832 5.108 9.912 ;
     RECT  3.949 11.712 5.108 13.08 ;
     RECT  3.521 14.256 5.108 14.28 ;
     RECT  3.532 15.456 5.108 15.48 ;
     RECT  4.777 16.656 5.108 22.584 ;
     RECT  3.913 23.856 5.108 23.88 ;
     RECT  4.525 25.152 5.108 25.656 ;
     RECT  4.741 26.784 5.108 27.624 ;
     RECT  5.108 2.148 5.212 27.624 ;
     RECT  5.212 2.418 5.3 27.624 ;
     RECT  5.3 2.418 5.404 27.822 ;
     RECT  5.404 14.688 5.573 25.56 ;
     RECT  5.404 2.832 5.699 13.08 ;
     RECT  5.404 26.784 5.897 27.384 ;
     RECT  5.699 3.312 6.329 13.08 ;
     RECT  5.573 23.376 6.505 25.56 ;
     RECT  5.897 26.784 6.505 27.096 ;
     RECT  6.329 3.312 6.793 12.456 ;
     RECT  6.793 2.64 6.797 12.456 ;
     RECT  5.573 14.688 7.009 22.056 ;
     RECT  6.505 23.376 7.009 27.096 ;
     RECT  7.009 14.688 7.045 27.096 ;
     RECT  6.577 13.68 7.297 13.704 ;
     RECT  7.045 14.688 7.297 27.192 ;
     RECT  7.297 13.68 7.369 27.192 ;
     RECT  6.797 9.552 7.549 12.456 ;
     RECT  7.369 13.632 7.549 27.192 ;
     RECT  6.797 2.64 7.808 8.568 ;
     RECT  7.549 9.552 7.808 27.192 ;
     RECT  7.808 2.148 7.912 27.552 ;
     RECT  7.912 2.418 8 27.552 ;
     RECT  8 2.418 8.104 27.822 ;
     RECT  8.104 16.608 8.165 27.192 ;
     RECT  8.165 16.608 8.237 22.056 ;
     RECT  8.104 3.408 8.417 15 ;
     RECT  8.417 3.408 8.497 13.656 ;
     RECT  8.497 10.128 8.633 13.656 ;
     RECT  8.165 23.04 8.741 27.192 ;
     RECT  8.741 26.304 8.813 27.192 ;
     RECT  8.497 3.408 9.097 8.808 ;
     RECT  8.417 14.736 9.197 15 ;
     RECT  9.197 14.736 9.281 15.384 ;
     RECT  9.097 2.784 9.353 8.808 ;
     RECT  8.237 20.304 9.356 22.056 ;
     RECT  8.741 23.04 9.356 25.224 ;
     RECT  8.633 10.128 9.673 12.984 ;
     RECT  9.353 2.88 9.781 8.808 ;
     RECT  8.813 27.072 9.781 27.192 ;
     RECT  9.781 2.88 9.877 9.096 ;
     RECT  9.673 10.128 9.877 13.08 ;
     RECT  9.877 2.88 9.925 13.08 ;
     RECT  8.237 16.608 9.925 19.32 ;
     RECT  9.356 20.304 9.925 25.224 ;
     RECT  9.925 16.608 10.249 25.224 ;
     RECT  9.781 26.784 10.285 27.192 ;
     RECT  10.249 16.608 10.501 25.32 ;
     RECT  10.285 26.304 10.501 27.192 ;
     RECT  9.925 2.88 10.508 13.128 ;
     RECT  9.281 14.736 10.508 15 ;
     RECT  10.501 16.608 10.508 27.192 ;
     RECT  10.508 2.148 10.612 27.552 ;
     RECT  10.612 2.418 10.7 27.552 ;
     RECT  10.7 2.418 10.804 27.822 ;
     RECT  10.804 14.544 10.865 27.192 ;
     RECT  10.865 15.84 10.901 27.192 ;
     RECT  10.901 23.04 11.459 27.192 ;
     RECT  10.804 2.784 11.477 13.56 ;
     RECT  10.865 14.544 11.765 14.808 ;
     RECT  11.477 2.88 11.837 13.56 ;
     RECT  11.765 14.736 12.053 14.808 ;
     RECT  11.459 23.04 12.197 26.856 ;
     RECT  12.053 14.784 12.337 14.808 ;
     RECT  12.337 14.784 13.021 14.856 ;
     RECT  10.901 15.84 13.021 22.056 ;
     RECT  13.021 14.784 13.093 22.056 ;
     RECT  11.837 2.88 13.208 13.08 ;
     RECT  13.093 14.496 13.208 22.056 ;
     RECT  12.197 23.04 13.208 26.76 ;
     RECT  13.208 2.148 13.312 27.552 ;
     RECT  13.312 2.418 13.4 27.552 ;
     RECT  13.4 2.418 13.504 27.822 ;
     RECT  13.504 14.496 13.997 25.032 ;
     RECT  13.997 14.496 14.003 23.208 ;
     RECT  13.504 27.168 14.105 27.24 ;
     RECT  13.997 24.192 14.497 25.032 ;
     RECT  13.504 26.112 14.497 26.136 ;
     RECT  13.504 2.784 14.537 13.464 ;
     RECT  14.105 27.168 14.537 27.192 ;
     RECT  14.537 12.768 14.569 13.464 ;
     RECT  14.003 14.496 14.569 17.496 ;
     RECT  14.003 18.528 15.5 23.208 ;
     RECT  14.497 24.192 15.5 26.136 ;
     RECT  14.537 2.784 15.908 11.784 ;
     RECT  14.569 12.768 15.908 17.496 ;
     RECT  15.5 18.528 15.908 26.136 ;
     RECT  15.908 2.148 16.012 27.552 ;
     RECT  16.012 2.418 16.1 27.552 ;
     RECT  16.1 2.418 16.204 27.822 ;
     RECT  16.204 2.784 16.355 14.568 ;
     RECT  16.355 3.408 16.553 14.568 ;
     RECT  16.204 18.528 16.697 27.384 ;
     RECT  16.553 7.728 17.173 14.568 ;
     RECT  16.204 15.552 17.173 17.496 ;
     RECT  17.173 7.728 17.305 17.496 ;
     RECT  16.697 18.528 17.305 19.32 ;
     RECT  16.553 3.408 17.377 6.696 ;
     RECT  16.697 20.304 17.489 27.384 ;
     RECT  17.305 7.728 17.507 19.32 ;
     RECT  17.377 3.12 18.169 6.696 ;
     RECT  17.507 7.728 18.169 13.656 ;
     RECT  18.169 3.12 18.608 13.656 ;
     RECT  17.507 15.36 18.608 19.32 ;
     RECT  17.489 20.304 18.608 26.568 ;
     RECT  18.608 2.148 18.712 27.552 ;
     RECT  18.712 2.418 18.8 27.552 ;
     RECT  18.8 2.418 18.904 27.822 ;
     RECT  18.904 15.504 19.969 26.328 ;
     RECT  18.904 2.832 20.389 13.08 ;
     RECT  20.389 2.64 20.653 13.08 ;
     RECT  20.473 14.448 20.653 14.472 ;
     RECT  17.029 30.144 21.013 30.168 ;
     RECT  20.653 2.64 21.308 14.472 ;
     RECT  19.969 15.504 21.308 27.192 ;
     RECT  21.308 2.148 21.412 27.552 ;
     RECT  21.412 2.418 21.5 27.552 ;
     RECT  21.5 2.418 21.604 27.822 ;
     RECT  21.604 3.408 21.737 13.848 ;
     RECT  21.737 3.408 22.705 10.728 ;
     RECT  22.705 2.496 22.777 10.728 ;
     RECT  21.737 11.712 22.777 13.848 ;
     RECT  21.604 15.312 22.813 15.528 ;
     RECT  21.604 16.608 22.813 27.24 ;
     RECT  22.813 15.312 22.853 27.24 ;
     RECT  22.853 15.312 22.994 27.144 ;
     RECT  22.777 2.496 24.008 13.848 ;
     RECT  22.994 15.312 24.008 27.096 ;
     RECT  24.008 2.148 24.112 27.552 ;
     RECT  24.112 2.418 24.2 27.552 ;
     RECT  24.2 2.418 24.304 27.822 ;
     RECT  24.304 25.728 24.401 27.096 ;
     RECT  24.401 25.728 24.869 26.856 ;
     RECT  24.304 14.88 24.977 24.504 ;
     RECT  24.869 25.728 25.405 26.76 ;
     RECT  24.304 2.736 25.477 13.704 ;
     RECT  24.977 14.88 25.477 21.528 ;
     RECT  25.477 2.736 25.657 21.528 ;
     RECT  25.657 2.352 25.981 21.528 ;
     RECT  24.977 22.704 25.981 24.504 ;
     RECT  25.981 2.352 26.593 24.504 ;
     RECT  25.405 25.632 26.593 26.76 ;
     RECT  26.593 2.352 26.708 26.76 ;
     RECT  21.013 30 26.773 30.168 ;
     RECT  26.708 2.148 26.812 27.552 ;
     RECT  26.812 2.352 26.9 27.552 ;
     RECT  26.9 2.352 27.004 27.822 ;
     RECT  27.004 2.352 27.245 15.528 ;
     RECT  27.004 16.56 27.317 26.376 ;
     RECT  27.245 2.352 27.497 13.704 ;
     RECT  27.497 2.88 27.677 13.704 ;
     RECT  26.773 29.904 27.965 30.168 ;
     RECT  27.317 26.112 28.001 26.376 ;
     RECT  27.677 9.264 28.213 13.704 ;
     RECT  27.245 15.312 28.321 15.528 ;
     RECT  27.317 16.56 28.321 25.08 ;
     RECT  27.965 29.904 28.361 30.072 ;
     RECT  28.361 29.904 28.433 29.928 ;
     RECT  28.213 9.264 28.717 14.28 ;
     RECT  28.321 15.312 28.717 25.08 ;
     RECT  27.677 2.88 28.789 8.28 ;
     RECT  28.717 9.264 28.789 25.08 ;
     RECT  28.789 2.88 29.077 25.08 ;
     RECT  28.001 26.112 29.077 26.232 ;
     RECT  29.077 2.88 29.113 26.568 ;
     RECT  29.113 2.88 29.185 26.664 ;
     RECT  29.185 2.88 29.293 26.808 ;
     RECT  29.293 2.592 29.408 26.808 ;
     RECT  29.408 2.148 29.512 27.552 ;
     RECT  29.512 2.418 29.6 27.552 ;
     RECT  29.6 2.418 29.704 27.822 ;
     RECT  29.704 14.208 29.837 14.52 ;
     RECT  29.704 15.84 30.305 26.856 ;
     RECT  29.704 2.592 30.737 13.176 ;
     RECT  30.305 22.8 30.881 26.856 ;
     RECT  30.881 26.016 31.025 26.856 ;
     RECT  30.737 2.88 31.388 13.176 ;
     RECT  29.837 14.208 31.388 14.232 ;
     RECT  31.388 2.88 31.429 14.232 ;
     RECT  30.881 22.8 31.849 24.504 ;
     RECT  30.305 15.84 31.921 21.528 ;
     RECT  31.849 22.56 31.921 24.504 ;
     RECT  31.429 2.88 32.108 14.856 ;
     RECT  31.921 15.84 32.108 24.504 ;
     RECT  31.025 26.016 32.108 26.808 ;
     RECT  32.108 2.148 32.212 27.552 ;
     RECT  32.212 2.418 32.3 27.552 ;
     RECT  32.3 2.418 32.404 27.822 ;
     RECT  32.404 25.776 32.681 27.384 ;
     RECT  32.404 16.656 33.113 24.648 ;
     RECT  32.404 2.832 33.149 13.08 ;
     RECT  33.149 2.832 33.299 7.416 ;
     RECT  33.113 16.656 33.329 16.68 ;
     RECT  33.299 2.88 33.689 7.416 ;
     RECT  32.681 25.776 33.689 26.568 ;
     RECT  33.689 26.016 34.153 26.568 ;
     RECT  34.153 15.456 34.213 15.864 ;
     RECT  33.113 17.664 34.213 24.648 ;
     RECT  34.213 15.36 34.585 15.864 ;
     RECT  34.213 16.944 34.585 24.648 ;
     RECT  34.153 26.016 34.765 26.76 ;
     RECT  33.149 8.496 34.801 13.08 ;
     RECT  33.689 3.072 34.808 7.416 ;
     RECT  34.801 8.496 34.808 13.32 ;
     RECT  34.585 15.36 34.808 24.648 ;
     RECT  34.765 26.016 34.808 27.384 ;
     RECT  34.808 2.148 34.912 27.552 ;
     RECT  34.912 2.418 35 27.552 ;
     RECT  35 2.418 35.104 27.822 ;
     RECT  35.104 27.36 35.219 27.384 ;
     RECT  35.104 8.496 35.237 12.984 ;
     RECT  35.104 15.504 35.26 26.328 ;
     RECT  35.26 15.504 35.381 25.032 ;
     RECT  35.381 15.504 35.489 17.064 ;
     RECT  35.489 15.504 35.525 15.528 ;
     RECT  35.489 16.56 35.777 17.064 ;
     RECT  35.777 16.56 35.921 16.728 ;
     RECT  35.104 3.072 36.205 7.416 ;
     RECT  35.237 8.496 36.205 12.888 ;
     RECT  35.381 18.144 36.457 25.032 ;
     RECT  35.26 26.016 36.457 26.328 ;
     RECT  36.457 18.144 36.461 26.328 ;
     RECT  36.461 18.144 36.533 26.232 ;
     RECT  35.921 16.608 37.465 16.728 ;
     RECT  36.533 18.144 37.465 26.136 ;
     RECT  36.205 3.072 37.508 12.888 ;
     RECT  37.465 16.608 37.508 26.136 ;
     RECT  37.508 2.148 37.612 27.552 ;
     RECT  37.612 2.418 37.7 27.552 ;
     RECT  37.7 2.418 37.804 27.822 ;
     RECT  37.804 17.616 38.009 18.024 ;
     RECT  37.804 19.056 38.009 25.032 ;
     RECT  38.009 22.512 38.045 25.032 ;
     RECT  38.009 19.056 38.261 21.528 ;
     RECT  38.261 19.056 38.297 21.432 ;
     RECT  38.045 22.8 39.013 25.032 ;
     RECT  38.009 17.712 39.017 18.024 ;
     RECT  39.013 22.752 39.017 25.032 ;
     RECT  39.017 18 39.445 18.024 ;
     RECT  38.297 19.056 39.445 21.24 ;
     RECT  39.017 22.752 39.877 24.504 ;
     RECT  37.804 3.072 40.208 7.416 ;
     RECT  37.804 8.496 40.208 10.68 ;
     RECT  37.804 11.712 40.208 12.888 ;
     RECT  39.445 18 40.208 21.528 ;
     RECT  39.877 22.512 40.208 24.504 ;
     RECT  37.804 26.112 40.208 26.136 ;
     RECT  40.208 2.148 40.312 27.552 ;
     RECT  40.312 2.418 40.4 27.552 ;
     RECT  40.4 2.418 40.504 27.822 ;
     RECT  40.504 19.344 40.709 24.504 ;
     RECT  40.504 11.712 41.177 12.888 ;
     RECT  41.177 11.712 41.393 12.84 ;
     RECT  40.709 20.352 41.429 24.504 ;
     RECT  40.504 3.072 41.717 7.416 ;
     RECT  40.709 19.344 41.861 19.368 ;
     RECT  41.717 3.072 42.908 6.36 ;
     RECT  40.504 8.496 42.908 10.68 ;
     RECT  41.393 11.712 42.908 12.552 ;
     RECT  41.429 20.64 42.908 24.504 ;
     RECT  40.504 26.112 42.908 26.136 ;
     RECT  42.908 2.148 43.012 27.552 ;
     RECT  43.012 2.418 43.1 27.552 ;
     RECT  43.1 2.418 43.204 27.822 ;
     RECT  43.204 8.496 43.265 10.2 ;
     RECT  43.204 3.072 44.021 6.36 ;
     RECT  43.204 26.112 44.305 26.136 ;
     RECT  43.204 23.568 44.953 24.504 ;
     RECT  44.305 25.488 44.953 26.136 ;
     RECT  44.021 3.408 44.989 6.36 ;
     RECT  44.989 3.408 45.349 6.936 ;
     RECT  43.265 8.496 45.349 10.152 ;
     RECT  45.385 19.344 45.493 19.368 ;
     RECT  43.204 20.64 45.493 22.584 ;
     RECT  45.349 3.408 45.608 10.152 ;
     RECT  43.204 11.712 45.608 12.552 ;
     RECT  45.493 19.344 45.608 22.584 ;
     RECT  44.953 23.568 45.608 26.136 ;
     RECT  45.608 2.148 45.712 27.552 ;
     RECT  45.712 2.418 45.8 27.552 ;
     RECT  45.8 2.418 45.904 27.822 ;
     RECT  45.904 11.712 46.217 12.552 ;
     RECT  45.904 6.336 46.793 7.896 ;
     RECT  45.904 20.016 46.793 26.136 ;
     RECT  46.793 20.016 47.005 22.584 ;
     RECT  47.005 19.344 47.315 22.584 ;
     RECT  46.217 11.712 48.265 11.976 ;
     RECT  45.904 3.408 48.308 4.248 ;
     RECT  46.793 6.336 48.308 7.752 ;
     RECT  45.904 9.36 48.308 10.152 ;
     RECT  48.265 11.184 48.308 11.976 ;
     RECT  47.315 20.112 48.308 22.584 ;
     RECT  46.793 23.568 48.308 26.136 ;
     RECT  48.308 2.148 48.412 27.552 ;
     RECT  48.412 2.418 48.5 27.552 ;
     RECT  48.5 2.418 48.604 27.822 ;
     RECT  48.604 11.184 50.173 11.976 ;
     RECT  48.604 6.336 50.713 7.752 ;
     RECT  48.604 9.36 50.713 10.152 ;
     RECT  48.604 3.408 51.008 4.248 ;
     RECT  50.713 6.336 51.008 10.152 ;
     RECT  50.173 11.136 51.008 11.976 ;
     RECT  48.604 20.112 51.008 22.584 ;
     RECT  48.604 23.568 51.008 26.136 ;
     RECT  51.008 2.148 51.112 27.552 ;
     RECT  51.112 2.418 51.2 27.552 ;
     RECT  51.2 2.418 51.304 27.822 ;
     RECT  51.304 23.568 52.297 23.592 ;
     RECT  51.304 6.336 52.621 10.152 ;
     RECT  51.304 11.136 52.621 11.976 ;
     RECT  51.304 20.112 52.981 22.584 ;
     RECT  52.297 23.568 52.981 23.688 ;
     RECT  51.304 3.408 53.708 3.432 ;
     RECT  52.621 6.336 53.708 11.976 ;
     RECT  52.981 20.112 53.708 23.688 ;
     RECT  51.304 24.672 53.708 26.136 ;
     RECT  53.708 2.148 53.812 27.552 ;
     RECT  53.812 2.418 53.9 27.552 ;
     RECT  53.9 2.418 54.004 27.822 ;
     RECT  54.004 20.112 55.253 26.136 ;
     RECT  54.004 6.336 55.753 11.976 ;
     RECT  54.004 3.408 56.408 3.432 ;
     RECT  55.753 6.336 56.408 12.504 ;
     RECT  55.253 20.16 56.408 26.136 ;
     RECT  56.408 2.148 56.512 27.552 ;
     RECT  56.512 2.418 56.6 27.552 ;
     RECT  56.6 2.418 56.704 27.822 ;
     RECT  56.704 3.408 59.108 3.432 ;
     RECT  56.704 6.336 59.108 12.504 ;
     RECT  56.704 20.64 59.108 26.136 ;
     RECT  59.108 2.148 59.212 27.552 ;
     RECT  59.212 2.418 59.3 27.552 ;
     RECT  59.3 2.418 59.404 27.822 ;
     RECT  59.404 20.64 59.897 26.136 ;
     RECT  59.404 6.864 60.437 12.504 ;
     RECT  60.437 6.864 60.725 12.36 ;
     RECT  59.897 20.64 61.669 26.088 ;
     RECT  59.404 3.408 61.808 3.432 ;
     RECT  60.725 6.864 61.808 8.52 ;
     RECT  60.725 9.792 61.808 12.36 ;
     RECT  61.669 19.344 61.808 26.088 ;
     RECT  61.808 2.148 61.912 27.552 ;
     RECT  61.912 2.418 62 27.552 ;
     RECT  62 2.418 62.104 27.822 ;
     RECT  62.104 19.92 62.741 26.088 ;
     RECT  62.104 6.96 63.277 12.36 ;
     RECT  63.277 6.96 63.313 12.936 ;
     RECT  63.313 6.96 63.853 13.032 ;
     RECT  63.853 6.864 64.692 6.888 ;
     RECT  63.853 6.888 64.716 6.96 ;
     RECT  63.853 6.96 64.692 6.984 ;
     RECT  63.853 6.984 64.716 7.056 ;
     RECT  63.853 7.056 64.692 7.08 ;
     RECT  63.853 7.08 64.716 7.152 ;
     RECT  63.853 7.152 64.692 7.176 ;
     RECT  63.853 7.176 64.716 7.248 ;
     RECT  63.853 7.248 64.692 7.272 ;
     RECT  63.853 7.272 64.716 7.344 ;
     RECT  63.853 7.344 64.692 7.368 ;
     RECT  63.853 7.368 64.716 7.44 ;
     RECT  63.853 7.44 64.692 7.464 ;
     RECT  63.853 7.464 64.716 7.536 ;
     RECT  63.853 7.536 64.692 7.56 ;
     RECT  63.853 7.56 64.716 7.632 ;
     RECT  63.853 7.632 64.692 7.656 ;
     RECT  63.853 7.656 64.716 7.728 ;
     RECT  63.853 7.728 64.692 7.752 ;
     RECT  63.853 7.752 64.716 7.824 ;
     RECT  63.853 7.824 64.692 7.848 ;
     RECT  63.853 7.848 64.716 7.92 ;
     RECT  63.853 7.92 64.692 7.944 ;
     RECT  63.853 7.944 64.716 8.016 ;
     RECT  63.853 8.016 64.692 8.04 ;
     RECT  63.853 8.04 64.716 8.112 ;
     RECT  63.853 8.112 64.692 8.136 ;
     RECT  63.853 8.136 64.716 8.208 ;
     RECT  63.853 8.208 64.692 8.232 ;
     RECT  63.853 8.232 64.716 8.304 ;
     RECT  63.853 8.304 64.692 8.328 ;
     RECT  63.853 8.328 64.716 8.4 ;
     RECT  63.853 8.4 64.692 8.424 ;
     RECT  63.853 8.424 64.716 8.496 ;
     RECT  63.853 8.496 64.692 8.52 ;
     RECT  63.853 8.52 64.716 8.592 ;
     RECT  63.853 8.592 64.692 8.616 ;
     RECT  63.853 8.616 64.716 8.688 ;
     RECT  63.853 8.688 64.692 8.712 ;
     RECT  63.853 8.712 64.716 8.784 ;
     RECT  63.853 8.784 64.692 8.808 ;
     RECT  63.853 8.808 64.716 8.88 ;
     RECT  63.853 8.88 64.692 8.904 ;
     RECT  63.853 8.904 64.716 8.976 ;
     RECT  63.853 8.976 64.692 9 ;
     RECT  63.853 9 64.716 9.072 ;
     RECT  63.853 9.072 64.692 9.096 ;
     RECT  63.853 9.096 64.716 9.168 ;
     RECT  63.853 9.168 64.692 9.192 ;
     RECT  63.853 9.192 64.716 9.264 ;
     RECT  63.853 9.264 64.692 9.288 ;
     RECT  63.853 9.288 64.716 9.36 ;
     RECT  63.853 9.36 64.692 9.384 ;
     RECT  63.853 9.384 64.716 9.456 ;
     RECT  63.853 9.456 64.692 9.48 ;
     RECT  63.853 9.48 64.716 9.552 ;
     RECT  63.853 9.552 64.692 9.576 ;
     RECT  63.853 9.576 64.716 9.648 ;
     RECT  63.853 9.648 64.692 9.672 ;
     RECT  63.853 9.672 64.716 9.744 ;
     RECT  63.853 9.744 64.692 9.768 ;
     RECT  63.853 9.768 64.716 9.84 ;
     RECT  63.853 9.84 64.692 9.864 ;
     RECT  63.853 9.864 64.716 9.936 ;
     RECT  63.853 9.936 64.692 9.96 ;
     RECT  63.853 9.96 64.716 10.032 ;
     RECT  63.853 10.032 64.692 10.056 ;
     RECT  63.853 10.056 64.716 10.128 ;
     RECT  63.853 10.128 64.692 10.152 ;
     RECT  63.853 10.152 64.716 10.224 ;
     RECT  63.853 10.224 64.692 10.248 ;
     RECT  63.853 10.248 64.716 10.32 ;
     RECT  63.853 10.32 64.692 10.344 ;
     RECT  63.853 10.344 64.716 10.416 ;
     RECT  63.853 10.416 64.692 10.44 ;
     RECT  63.853 10.44 64.716 10.512 ;
     RECT  63.853 10.512 64.692 10.536 ;
     RECT  63.853 10.536 64.716 10.608 ;
     RECT  63.853 10.608 64.692 10.632 ;
     RECT  63.853 10.632 64.716 10.704 ;
     RECT  63.853 10.704 64.692 10.728 ;
     RECT  63.853 10.728 64.716 10.8 ;
     RECT  63.853 10.8 64.692 10.824 ;
     RECT  63.853 10.824 64.716 10.896 ;
     RECT  63.853 10.896 64.692 10.92 ;
     RECT  63.853 10.92 64.716 10.992 ;
     RECT  63.853 10.992 64.692 11.016 ;
     RECT  63.853 11.016 64.716 11.088 ;
     RECT  63.853 11.088 64.692 11.112 ;
     RECT  63.853 11.112 64.716 11.184 ;
     RECT  63.853 11.184 64.692 11.208 ;
     RECT  63.853 11.208 64.716 11.28 ;
     RECT  63.853 11.28 64.692 11.304 ;
     RECT  63.853 11.304 64.716 11.376 ;
     RECT  63.853 11.376 64.692 11.4 ;
     RECT  63.853 11.4 64.716 11.472 ;
     RECT  63.853 11.472 64.692 11.496 ;
     RECT  63.853 11.496 64.716 11.568 ;
     RECT  63.853 11.568 64.692 11.592 ;
     RECT  63.853 11.592 64.716 11.664 ;
     RECT  63.853 11.664 64.692 11.688 ;
     RECT  63.853 11.688 64.716 11.76 ;
     RECT  63.853 11.76 64.692 11.784 ;
     RECT  63.853 11.784 64.716 11.856 ;
     RECT  63.853 11.856 64.692 11.88 ;
     RECT  63.853 11.88 64.716 11.952 ;
     RECT  63.853 11.952 64.692 11.976 ;
     RECT  63.853 11.976 64.716 12.048 ;
     RECT  63.853 12.048 64.692 12.072 ;
     RECT  63.853 12.072 64.716 12.144 ;
     RECT  63.853 12.144 64.692 12.168 ;
     RECT  63.853 12.168 64.716 12.24 ;
     RECT  63.853 12.24 64.692 12.264 ;
     RECT  63.853 12.264 64.716 12.336 ;
     RECT  63.853 12.336 64.692 12.36 ;
     RECT  63.853 12.36 64.716 12.432 ;
     RECT  63.853 12.432 64.692 12.456 ;
     RECT  63.853 12.456 64.716 12.528 ;
     RECT  63.853 12.528 64.692 12.552 ;
     RECT  63.853 12.552 64.716 12.624 ;
     RECT  63.853 12.624 64.692 12.648 ;
     RECT  63.853 12.648 64.716 12.72 ;
     RECT  63.853 12.72 64.692 12.744 ;
     RECT  63.853 12.744 64.716 12.816 ;
     RECT  63.853 12.816 64.692 12.84 ;
     RECT  63.853 12.84 64.716 12.912 ;
     RECT  63.853 12.912 64.692 12.936 ;
     RECT  63.853 12.936 64.716 13.008 ;
     RECT  63.853 13.008 64.692 13.032 ;
     RECT  62.741 19.92 64.692 19.944 ;
     RECT  62.741 19.944 64.716 20.016 ;
     RECT  62.741 20.016 64.692 20.04 ;
     RECT  62.741 20.04 64.716 20.112 ;
     RECT  62.741 20.112 64.692 20.136 ;
     RECT  62.741 20.136 64.716 20.208 ;
     RECT  62.741 20.208 64.692 20.232 ;
     RECT  62.741 20.232 64.716 20.304 ;
     RECT  62.741 20.304 64.692 20.328 ;
     RECT  62.741 20.328 64.716 20.4 ;
     RECT  62.741 20.4 64.692 20.424 ;
     RECT  62.741 20.424 64.716 20.496 ;
     RECT  62.741 20.496 64.692 20.52 ;
     RECT  62.741 20.52 64.716 20.592 ;
     RECT  62.741 20.592 64.692 20.616 ;
     RECT  62.741 20.616 64.716 20.688 ;
     RECT  62.741 20.688 64.692 20.712 ;
     RECT  62.741 20.712 64.716 20.784 ;
     RECT  62.741 20.784 64.692 20.808 ;
     RECT  62.741 20.808 64.716 20.88 ;
     RECT  62.741 20.88 64.692 20.904 ;
     RECT  62.741 20.904 64.716 20.976 ;
     RECT  62.741 20.976 64.692 21 ;
     RECT  62.741 21 64.716 21.072 ;
     RECT  62.741 21.072 64.692 21.096 ;
     RECT  62.741 21.096 64.716 21.168 ;
     RECT  62.741 21.168 64.692 21.192 ;
     RECT  62.741 21.192 64.716 21.264 ;
     RECT  62.741 21.264 64.692 21.288 ;
     RECT  62.741 21.288 64.716 21.36 ;
     RECT  62.741 21.36 64.692 21.384 ;
     RECT  62.741 21.384 64.716 21.456 ;
     RECT  62.741 21.456 64.692 21.48 ;
     RECT  62.741 21.48 64.716 21.552 ;
     RECT  62.741 21.552 64.692 21.576 ;
     RECT  62.741 21.576 64.716 21.648 ;
     RECT  62.741 21.648 64.692 21.672 ;
     RECT  62.741 21.672 64.716 21.744 ;
     RECT  62.741 21.744 64.692 21.768 ;
     RECT  62.741 21.768 64.716 21.84 ;
     RECT  62.741 21.84 64.692 21.864 ;
     RECT  62.741 21.864 64.716 21.936 ;
     RECT  62.741 21.936 64.692 21.96 ;
     RECT  62.741 21.96 64.716 22.032 ;
     RECT  62.741 22.032 64.692 22.056 ;
     RECT  62.741 22.056 64.716 22.128 ;
     RECT  62.741 22.128 64.692 22.152 ;
     RECT  62.741 22.152 64.716 22.224 ;
     RECT  62.741 22.224 64.692 22.248 ;
     RECT  62.741 22.248 64.716 22.32 ;
     RECT  62.741 22.32 64.692 22.344 ;
     RECT  62.741 22.344 64.716 22.416 ;
     RECT  62.741 22.416 64.692 22.44 ;
     RECT  62.741 22.44 64.716 22.512 ;
     RECT  62.741 22.512 64.692 22.536 ;
     RECT  62.741 22.536 64.716 22.608 ;
     RECT  62.741 22.608 64.692 22.632 ;
     RECT  62.741 22.632 64.716 22.704 ;
     RECT  62.741 22.704 64.692 22.728 ;
     RECT  62.741 22.728 64.716 22.8 ;
     RECT  62.741 22.8 64.692 22.824 ;
     RECT  62.741 22.824 64.716 22.896 ;
     RECT  62.741 22.896 64.692 22.92 ;
     RECT  62.741 22.92 64.716 22.992 ;
     RECT  62.741 22.992 64.692 23.016 ;
     RECT  62.741 23.016 64.716 23.088 ;
     RECT  62.741 23.088 64.692 23.112 ;
     RECT  62.741 23.112 64.716 23.184 ;
     RECT  62.741 23.184 64.692 23.208 ;
     RECT  62.741 23.208 64.716 23.28 ;
     RECT  62.741 23.28 64.692 23.304 ;
     RECT  62.741 23.304 64.716 23.376 ;
     RECT  62.741 23.376 64.692 23.4 ;
     RECT  62.741 23.4 64.716 23.472 ;
     RECT  62.741 23.472 64.692 23.496 ;
     RECT  62.741 23.496 64.716 23.568 ;
     RECT  62.741 23.568 64.692 23.592 ;
     RECT  62.741 23.592 64.716 23.664 ;
     RECT  62.741 23.664 64.692 23.688 ;
     RECT  62.741 23.688 64.716 23.76 ;
     RECT  62.741 23.76 64.692 23.784 ;
     RECT  62.741 23.784 64.716 23.856 ;
     RECT  62.741 23.856 64.692 23.88 ;
     RECT  62.741 23.88 64.716 23.952 ;
     RECT  62.741 23.952 64.692 23.976 ;
     RECT  62.741 23.976 64.716 24.048 ;
     RECT  62.741 24.048 64.692 24.072 ;
     RECT  62.741 24.072 64.716 24.144 ;
     RECT  62.741 24.144 64.692 24.168 ;
     RECT  62.741 24.168 64.716 24.24 ;
     RECT  62.741 24.24 64.692 24.264 ;
     RECT  62.741 24.264 64.716 24.336 ;
     RECT  62.741 24.336 64.692 24.36 ;
     RECT  62.741 24.36 64.716 24.432 ;
     RECT  62.741 24.432 64.692 24.456 ;
     RECT  62.741 24.456 64.716 24.528 ;
     RECT  62.741 24.528 64.692 24.552 ;
     RECT  62.741 24.552 64.716 24.624 ;
     RECT  62.741 24.624 64.692 24.648 ;
     RECT  62.741 24.648 64.716 24.72 ;
     RECT  62.741 24.72 64.692 24.744 ;
     RECT  62.741 24.744 64.716 24.816 ;
     RECT  62.741 24.816 64.692 24.84 ;
     RECT  62.741 24.84 64.716 24.912 ;
     RECT  62.741 24.912 64.692 24.936 ;
     RECT  62.741 24.936 64.716 25.008 ;
     RECT  62.741 25.008 64.692 25.032 ;
     RECT  62.741 25.032 64.716 25.104 ;
     RECT  62.741 25.104 64.692 25.128 ;
     RECT  62.741 25.128 64.716 25.2 ;
     RECT  62.741 25.2 64.692 25.224 ;
     RECT  62.741 25.224 64.716 25.296 ;
     RECT  62.741 25.296 64.692 25.32 ;
     RECT  62.741 25.32 64.716 25.392 ;
     RECT  62.741 25.392 64.692 25.416 ;
     RECT  62.741 25.416 64.716 25.488 ;
     RECT  62.741 25.488 64.692 25.512 ;
     RECT  62.741 25.512 64.716 25.584 ;
     RECT  62.741 25.584 64.692 25.608 ;
     RECT  62.741 25.608 64.716 25.68 ;
     RECT  62.741 25.68 64.692 25.704 ;
     RECT  62.741 25.704 64.716 25.776 ;
     RECT  62.741 25.776 64.692 25.8 ;
     RECT  62.741 25.8 64.716 25.872 ;
     RECT  62.741 25.872 64.692 25.896 ;
     RECT  62.741 25.896 64.716 25.968 ;
     RECT  62.741 25.968 64.692 25.992 ;
     RECT  64.716 8.16 64.757 8.184 ;
     RECT  64.716 11.136 64.757 11.16 ;
     RECT  64.716 22.464 64.757 22.488 ;
     RECT  64.716 24.096 64.757 24.144 ;
     RECT  64.716 24.168 64.757 24.24 ;
     RECT  64.716 24.264 64.757 24.336 ;
     RECT  64.716 24.36 64.757 24.432 ;
     RECT  64.716 24.456 64.757 24.528 ;
     RECT  64.716 24.552 64.757 24.624 ;
     RECT  64.716 24.648 64.757 24.72 ;
     RECT  64.716 24.744 64.757 24.792 ;
    LAYER M5 ;
     RECT  2.4 2.137 2.52 2.151 ;
     RECT  5.1 2.137 5.22 2.151 ;
     RECT  7.8 2.137 7.92 2.151 ;
     RECT  10.5 2.137 10.62 2.151 ;
     RECT  13.2 2.137 13.32 2.151 ;
     RECT  15.9 2.137 16.02 2.151 ;
     RECT  18.6 2.137 18.72 2.151 ;
     RECT  21.3 2.137 21.42 2.151 ;
     RECT  24 2.137 24.12 2.151 ;
     RECT  26.7 2.137 26.82 2.151 ;
     RECT  29.4 2.137 29.52 2.151 ;
     RECT  32.1 2.137 32.22 2.151 ;
     RECT  34.8 2.137 34.92 2.151 ;
     RECT  37.5 2.137 37.62 2.151 ;
     RECT  40.2 2.137 40.32 2.151 ;
     RECT  42.9 2.137 43.02 2.151 ;
     RECT  45.6 2.137 45.72 2.151 ;
     RECT  48.3 2.137 48.42 2.151 ;
     RECT  51 2.137 51.12 2.151 ;
     RECT  53.7 2.137 53.82 2.151 ;
     RECT  56.4 2.137 56.52 2.151 ;
     RECT  59.1 2.137 59.22 2.151 ;
     RECT  61.8 2.137 61.92 2.151 ;
     RECT  21.3 2.151 21.612 2.629 ;
     RECT  7.8 2.151 8.112 2.677 ;
     RECT  24 2.151 24.312 2.725 ;
     RECT  15.9 2.151 16.212 2.773 ;
     RECT  5.1 2.151 5.412 2.821 ;
     RECT  24 2.725 24.744 2.821 ;
     RECT  32.1 2.151 32.412 2.821 ;
     RECT  23.904 2.821 24.744 2.963 ;
     RECT  7.152 2.677 8.112 3.397 ;
     RECT  18.6 2.151 18.912 3.397 ;
     RECT  7.152 3.397 8.76 3.875 ;
     RECT  15.9 2.773 16.344 3.925 ;
     RECT  18.6 3.397 19.032 4.163 ;
     RECT  20.4 2.629 21.612 4.355 ;
     RECT  5.1 2.821 5.688 4.501 ;
     RECT  34.8 2.151 35.112 4.501 ;
     RECT  32.1 2.821 33.288 4.595 ;
     RECT  4.944 4.501 5.688 4.645 ;
     RECT  10.5 2.151 10.812 4.645 ;
     RECT  28.176 4.645 28.2 4.787 ;
     RECT  29.4 2.151 29.712 4.885 ;
     RECT  29.4 4.885 30.216 5.077 ;
     RECT  2.4 2.151 2.712 5.125 ;
     RECT  29.28 5.077 30.216 5.125 ;
     RECT  34.8 4.501 35.208 5.171 ;
     RECT  28.464 5.125 30.216 5.267 ;
     RECT  4.944 4.645 5.832 5.605 ;
     RECT  10.32 4.645 10.812 5.653 ;
     RECT  23.904 2.963 24.312 5.747 ;
     RECT  4.944 5.605 6.312 5.845 ;
     RECT  2.4 5.125 3.48 5.987 ;
     RECT  7.8 3.875 8.112 6.229 ;
     RECT  4.56 5.845 6.312 6.277 ;
     RECT  21.3 4.355 21.612 6.325 ;
     RECT  10.32 5.653 10.92 6.611 ;
     RECT  26.7 2.151 27.012 6.613 ;
     RECT  32.1 4.595 32.412 6.661 ;
     RECT  26.7 6.613 27.144 6.755 ;
     RECT  7.8 6.229 8.28 6.805 ;
     RECT  45.6 2.151 45.912 6.805 ;
     RECT  10.368 6.611 10.92 7.045 ;
     RECT  2.4 5.987 3.288 7.091 ;
     RECT  18.6 4.163 18.912 7.189 ;
     RECT  28.464 5.267 29.712 7.189 ;
     RECT  4.56 6.277 6.696 7.379 ;
     RECT  28.32 7.189 29.712 7.427 ;
     RECT  22.8 6.325 22.824 7.475 ;
     RECT  5.1 7.379 6.696 7.523 ;
     RECT  2.4 7.091 2.904 7.667 ;
     RECT  18.6 7.189 19.272 7.763 ;
     RECT  45.36 6.805 45.912 7.763 ;
     RECT  6.672 7.523 6.696 7.765 ;
     RECT  7.8 6.805 8.472 7.765 ;
     RECT  31.92 6.661 32.412 7.811 ;
     RECT  10.368 7.045 11.304 7.907 ;
     RECT  21.072 6.325 21.612 7.907 ;
     RECT  36.288 6.805 36.312 8.003 ;
     RECT  6.672 7.765 8.472 8.339 ;
     RECT  55.056 7.909 55.08 8.531 ;
     RECT  7.44 8.339 8.472 8.579 ;
     RECT  13.2 2.151 13.512 8.965 ;
     RECT  21.3 7.907 21.612 8.965 ;
     RECT  10.368 7.907 10.812 9.061 ;
     RECT  12.384 8.965 13.512 9.061 ;
     RECT  18.6 7.763 18.912 9.061 ;
     RECT  29.088 7.427 29.712 9.253 ;
     RECT  28.224 9.253 29.712 9.445 ;
     RECT  34.8 5.171 35.112 9.493 ;
     RECT  14.784 9.109 14.808 9.587 ;
     RECT  27.984 9.445 29.712 9.587 ;
     RECT  7.8 8.579 8.472 9.731 ;
     RECT  20.544 8.965 21.612 9.779 ;
     RECT  28.224 9.587 29.712 9.779 ;
     RECT  12.24 9.061 13.512 9.923 ;
     RECT  32.1 7.811 32.412 9.925 ;
     RECT  0.144 9.781 0.168 10.163 ;
     RECT  26.7 6.755 27.012 10.165 ;
     RECT  29.088 9.779 29.712 10.259 ;
     RECT  22.704 9.061 22.728 10.261 ;
     RECT  7.8 9.731 8.232 10.307 ;
     RECT  22.704 10.261 22.824 10.307 ;
     RECT  25.92 10.165 27.012 10.453 ;
     RECT  34.704 9.493 35.112 10.549 ;
     RECT  9.888 9.061 10.812 10.883 ;
     RECT  25.92 10.453 27.144 10.883 ;
     RECT  34.272 10.549 35.112 10.883 ;
     RECT  31.344 9.925 32.412 10.931 ;
     RECT  18.432 9.061 18.912 11.027 ;
     RECT  24 5.747 24.312 11.125 ;
     RECT  22.8 10.307 22.824 11.171 ;
     RECT  7.8 10.307 8.112 11.365 ;
     RECT  12.672 9.923 13.512 11.365 ;
     RECT  26.7 10.883 27.144 11.365 ;
     RECT  12.672 11.365 13.608 11.651 ;
     RECT  29.28 10.259 29.712 11.941 ;
     RECT  24 11.125 24.408 12.035 ;
     RECT  15.9 3.925 17.16 12.325 ;
     RECT  15.9 12.325 17.496 12.371 ;
     RECT  7.8 11.365 8.568 12.755 ;
     RECT  26.7 11.365 27.672 12.755 ;
     RECT  31.056 12.517 31.08 12.803 ;
     RECT  34.8 10.883 35.112 12.853 ;
     RECT  5.1 7.523 5.688 12.899 ;
     RECT  34.176 12.853 35.112 13.043 ;
     RECT  15.9 12.371 16.344 13.091 ;
     RECT  32.1 10.931 32.412 13.477 ;
     RECT  29.088 11.941 29.712 13.621 ;
     RECT  24 12.035 24.312 13.669 ;
     RECT  15.9 13.091 16.212 14.197 ;
     RECT  13.2 11.651 13.608 14.485 ;
     RECT  15.36 14.197 16.212 14.485 ;
     RECT  14.64 14.485 16.212 14.531 ;
     RECT  17.472 12.371 17.496 14.533 ;
     RECT  13.104 14.485 13.608 14.629 ;
     RECT  13.104 14.629 13.656 14.867 ;
     RECT  31.44 13.477 32.412 14.867 ;
     RECT  14.64 14.531 14.664 14.915 ;
     RECT  7.8 12.755 8.52 15.011 ;
     RECT  2.4 7.667 2.712 15.301 ;
     RECT  7.8 15.011 8.112 15.301 ;
     RECT  34.8 13.043 35.112 15.349 ;
     RECT  13.2 14.867 13.656 15.491 ;
     RECT  21.3 9.779 21.612 15.493 ;
     RECT  15.9 14.531 16.212 15.541 ;
     RECT  18.6 11.027 18.912 15.637 ;
     RECT  29.04 13.621 29.712 15.733 ;
     RECT  13.2 15.491 13.512 15.829 ;
     RECT  15.552 15.541 16.212 15.829 ;
     RECT  17.184 14.533 17.496 15.829 ;
     RECT  2.4 15.301 3.48 16.019 ;
     RECT  24 13.669 24.648 16.019 ;
     RECT  7.104 15.301 8.112 16.069 ;
     RECT  28.704 15.733 29.712 16.069 ;
     RECT  21.168 15.493 21.612 16.261 ;
     RECT  18.6 15.637 19.176 16.499 ;
     RECT  13.104 15.829 13.512 16.883 ;
     RECT  9.216 15.349 9.24 16.933 ;
     RECT  10.368 10.883 10.812 16.933 ;
     RECT  13.2 16.883 13.512 17.029 ;
     RECT  21.024 16.261 21.612 17.077 ;
     RECT  28.704 16.069 29.976 17.219 ;
     RECT  32.1 14.867 32.412 17.509 ;
     RECT  20.928 17.077 21.612 17.699 ;
     RECT  13.2 17.029 13.992 17.843 ;
     RECT  5.1 12.899 5.592 17.891 ;
     RECT  31.968 17.509 32.412 18.035 ;
     RECT  37.5 2.151 37.812 18.133 ;
     RECT  24 16.019 24.312 18.181 ;
     RECT  34.224 15.349 35.112 18.227 ;
     RECT  40.2 2.151 40.512 18.277 ;
     RECT  6.864 16.069 8.112 18.419 ;
     RECT  18.6 16.499 18.912 18.661 ;
     RECT  2.4 16.019 2.712 18.853 ;
     RECT  9.216 16.933 10.812 18.995 ;
     RECT  2.256 18.853 2.712 19.043 ;
     RECT  37.392 18.133 37.812 19.091 ;
     RECT  39.552 18.277 40.512 19.091 ;
     RECT  5.1 17.891 5.412 19.093 ;
     RECT  23.328 18.181 24.888 19.189 ;
     RECT  2.4 19.043 2.712 19.237 ;
     RECT  34.8 18.227 35.112 19.237 ;
     RECT  28.704 17.219 29.712 19.283 ;
     RECT  45.6 7.763 45.912 19.333 ;
     RECT  61.8 2.151 62.112 19.333 ;
     RECT  30.816 18.421 30.84 19.571 ;
     RECT  18.6 18.661 19.368 20.003 ;
     RECT  23.328 19.189 25.704 20.003 ;
     RECT  7.104 18.419 8.112 20.051 ;
     RECT  45.504 19.333 45.912 20.147 ;
     RECT  56.4 2.151 56.712 20.149 ;
     RECT  2.4 19.237 3.432 20.245 ;
     RECT  47.28 19.333 47.304 20.339 ;
     RECT  61.68 19.333 62.112 20.339 ;
     RECT  5.1 19.093 5.784 20.483 ;
     RECT  32.1 18.035 32.412 20.485 ;
     RECT  55.92 20.149 56.712 20.485 ;
     RECT  2.4 20.245 3.96 20.579 ;
     RECT  24 20.003 25.704 20.579 ;
     RECT  21.024 17.699 21.612 20.869 ;
     RECT  55.248 20.485 56.712 20.963 ;
     RECT  61.8 20.339 62.112 21.109 ;
     RECT  55.92 20.963 56.712 21.155 ;
     RECT  3.936 20.579 3.96 21.299 ;
     RECT  61.8 21.109 62.76 21.299 ;
     RECT  26.7 12.755 27.012 21.541 ;
     RECT  34.8 19.237 35.592 21.637 ;
     RECT  9.216 18.995 9.24 21.683 ;
     RECT  20.208 20.869 21.612 21.683 ;
     RECT  32.1 20.485 32.568 21.683 ;
     RECT  34.032 21.637 35.592 21.925 ;
     RECT  2.4 20.579 2.712 21.973 ;
     RECT  40.2 19.091 40.512 22.069 ;
     RECT  32.1 21.683 32.412 22.213 ;
     RECT  26.208 21.541 27.012 22.259 ;
     RECT  34.032 21.925 35.88 22.499 ;
     RECT  40.2 22.069 40.632 22.499 ;
     RECT  2.304 21.973 2.712 22.549 ;
     RECT  61.8 21.299 62.616 22.645 ;
     RECT  2.208 22.549 2.712 22.739 ;
     RECT  61.8 22.645 62.712 22.835 ;
     RECT  0.144 23.125 0.168 23.315 ;
     RECT  31.968 22.213 32.412 23.315 ;
     RECT  39.024 22.741 39.048 23.317 ;
     RECT  40.2 22.499 40.512 23.317 ;
     RECT  7.392 20.051 8.112 23.411 ;
     RECT  39.024 23.317 40.512 23.411 ;
     RECT  39.84 23.411 40.512 23.603 ;
     RECT  15.552 15.829 17.496 24.083 ;
     RECT  34.8 22.499 35.88 24.083 ;
     RECT  29.4 19.283 29.712 24.085 ;
     RECT  37.5 19.091 37.812 24.085 ;
     RECT  13.2 17.843 13.512 24.901 ;
     RECT  61.8 22.835 62.112 24.901 ;
     RECT  10.5 18.995 10.812 25.045 ;
     RECT  13.056 24.901 13.512 25.091 ;
     RECT  15.9 24.083 17.496 25.139 ;
     RECT  9.408 22.645 9.432 25.235 ;
     RECT  37.056 24.085 37.812 25.715 ;
     RECT  61.8 24.901 62.76 25.715 ;
     RECT  24 20.579 24.84 25.763 ;
     RECT  32.1 23.315 32.412 25.861 ;
     RECT  19.968 22.741 19.992 26.243 ;
     RECT  34.8 24.083 35.592 26.243 ;
     RECT  29.184 24.085 29.712 26.627 ;
     RECT  3.936 26.245 3.96 27.013 ;
     RECT  5.1 20.483 5.412 27.013 ;
     RECT  3.936 27.013 5.412 27.059 ;
     RECT  10.5 25.045 11.448 27.203 ;
     RECT  32.1 25.861 32.52 27.395 ;
     RECT  34.8 26.243 35.208 27.395 ;
     RECT  4.752 27.059 5.412 27.635 ;
     RECT  2.4 22.739 2.712 27.819 ;
     RECT  5.1 27.635 5.412 27.819 ;
     RECT  7.8 23.411 8.112 27.819 ;
     RECT  10.5 27.203 10.812 27.819 ;
     RECT  13.2 25.091 13.512 27.819 ;
     RECT  15.9 25.139 17.064 27.819 ;
     RECT  18.6 20.003 18.912 27.819 ;
     RECT  24 25.763 24.312 27.819 ;
     RECT  26.7 22.259 27.012 27.819 ;
     RECT  29.4 26.627 29.712 27.819 ;
     RECT  32.1 27.395 32.412 27.819 ;
     RECT  34.8 27.395 35.112 27.819 ;
     RECT  37.5 25.715 37.812 27.819 ;
     RECT  40.2 23.603 40.512 27.819 ;
     RECT  42.9 2.151 43.212 27.819 ;
     RECT  45.6 20.147 45.912 27.819 ;
     RECT  48.3 2.151 48.612 27.819 ;
     RECT  51 2.151 51.312 27.819 ;
     RECT  53.7 2.151 54.012 27.819 ;
     RECT  56.4 21.155 56.712 27.819 ;
     RECT  59.1 2.151 59.412 27.819 ;
     RECT  61.8 25.715 62.112 27.819 ;
     RECT  2.592 27.819 2.712 27.833 ;
     RECT  5.292 27.819 5.412 27.833 ;
     RECT  7.992 27.819 8.112 27.833 ;
     RECT  10.692 27.819 10.812 27.833 ;
     RECT  13.392 27.819 13.512 27.833 ;
     RECT  16.092 27.819 17.064 27.833 ;
     RECT  18.792 27.819 18.912 27.833 ;
     RECT  21.024 21.683 21.612 27.833 ;
     RECT  24.192 27.819 24.312 27.833 ;
     RECT  26.892 27.819 27.012 27.833 ;
     RECT  29.592 27.819 29.712 27.833 ;
     RECT  32.292 27.819 32.412 27.833 ;
     RECT  34.992 27.819 35.112 27.833 ;
     RECT  37.692 27.819 37.812 27.833 ;
     RECT  40.392 27.819 40.512 27.833 ;
     RECT  43.092 27.819 43.212 27.833 ;
     RECT  45.792 27.819 45.912 27.833 ;
     RECT  48.492 27.819 48.612 27.833 ;
     RECT  51.192 27.819 51.312 27.833 ;
     RECT  53.892 27.819 54.012 27.833 ;
     RECT  56.592 27.819 56.712 27.833 ;
     RECT  59.292 27.819 59.412 27.833 ;
     RECT  61.992 27.819 62.112 27.833 ;
     RECT  21.024 27.833 21.048 30.035 ;
     RECT  17.04 27.833 17.064 30.179 ;
     RECT  18.912 2.629 20.4 3.397 ;
     RECT  5.688 2.821 7.152 3.875 ;
     RECT  33.288 2.821 34.8 4.595 ;
     RECT  19.032 3.397 20.4 4.163 ;
     RECT  5.688 3.875 5.832 4.645 ;
     RECT  17.16 3.925 18.6 9.061 ;
     RECT  18.912 4.163 20.4 4.355 ;
     RECT  27.012 4.645 28.176 4.787 ;
     RECT  28.2 4.645 29.4 4.787 ;
     RECT  27.012 4.787 29.4 5.077 ;
     RECT  27.012 5.077 29.28 5.125 ;
     RECT  3.48 5.125 4.944 5.845 ;
     RECT  27.012 5.125 28.464 6.613 ;
     RECT  6.312 5.605 7.8 6.277 ;
     RECT  23.904 5.747 24 6.325 ;
     RECT  3.48 5.845 4.56 5.987 ;
     RECT  3.288 5.987 4.56 7.091 ;
     RECT  6.696 6.277 7.8 7.765 ;
     RECT  21.612 6.325 22.8 7.475 ;
     RECT  22.824 6.325 24 7.475 ;
     RECT  27.144 6.613 28.464 6.755 ;
     RECT  27.012 6.755 28.464 7.189 ;
     RECT  35.112 6.805 36.288 8.003 ;
     RECT  36.312 6.805 37.5 8.003 ;
     RECT  27.012 7.189 28.32 7.427 ;
     RECT  5.688 7.523 6.672 8.339 ;
     RECT  10.812 7.907 11.304 8.965 ;
     RECT  21.072 7.907 21.3 8.965 ;
     RECT  54.012 7.909 55.056 8.531 ;
     RECT  55.08 7.909 56.4 8.531 ;
     RECT  10.812 8.965 12.384 9.061 ;
     RECT  8.472 9.061 9.888 9.731 ;
     RECT  10.812 9.061 12.24 9.923 ;
     RECT  17.16 9.061 18.432 11.027 ;
     RECT  21.612 9.061 22.704 10.307 ;
     RECT  22.728 9.061 24 10.261 ;
     RECT  13.512 9.109 14.784 9.587 ;
     RECT  14.808 9.109 15.9 9.587 ;
     RECT  27.012 9.253 28.224 9.445 ;
     RECT  27.012 9.445 27.984 9.587 ;
     RECT  27.012 9.587 28.224 9.779 ;
     RECT  27.012 9.779 27.144 10.453 ;
     RECT  22.824 10.261 24 11.171 ;
     RECT  8.112 10.307 8.232 11.365 ;
     RECT  21.612 10.307 22.8 11.171 ;
     RECT  17.16 11.027 18.6 12.325 ;
     RECT  27.672 11.941 29.088 12.755 ;
     RECT  17.496 12.325 18.6 25.139 ;
     RECT  16.344 12.371 17.472 13.091 ;
     RECT  29.712 12.517 31.056 12.803 ;
     RECT  31.08 12.517 32.1 12.803 ;
     RECT  29.04 12.755 29.088 13.621 ;
     RECT  31.44 12.803 32.1 13.477 ;
     RECT  16.212 13.091 17.472 14.533 ;
     RECT  13.608 14.485 14.64 14.629 ;
     RECT  14.664 14.531 15.9 14.915 ;
     RECT  16.212 14.533 17.184 15.829 ;
     RECT  13.656 14.629 14.64 14.915 ;
     RECT  13.104 14.867 13.2 15.829 ;
     RECT  15.552 14.915 15.9 15.541 ;
     RECT  8.112 15.011 8.52 15.349 ;
     RECT  5.592 15.301 7.104 16.069 ;
     RECT  8.112 15.349 9.216 21.683 ;
     RECT  9.24 15.349 10.368 16.933 ;
     RECT  5.592 16.069 6.864 17.891 ;
     RECT  29.712 17.219 29.976 18.421 ;
     RECT  5.412 17.891 6.864 18.419 ;
     RECT  31.968 18.035 32.1 18.421 ;
     RECT  5.412 18.419 7.104 19.093 ;
     RECT  29.712 18.421 30.816 19.571 ;
     RECT  30.84 18.421 32.1 19.571 ;
     RECT  9.24 18.995 10.5 21.683 ;
     RECT  5.784 19.093 7.104 20.051 ;
     RECT  25.704 19.189 26.7 20.579 ;
     RECT  45.912 19.333 47.28 20.339 ;
     RECT  47.304 19.333 48.3 20.339 ;
     RECT  18.912 20.003 19.368 20.869 ;
     RECT  3.96 20.245 5.1 21.299 ;
     RECT  54.012 20.485 55.248 20.963 ;
     RECT  2.712 20.579 3.936 21.299 ;
     RECT  24.84 20.579 26.7 21.541 ;
     RECT  18.912 20.869 20.208 21.683 ;
     RECT  62.616 21.299 62.712 22.645 ;
     RECT  24.84 21.541 26.208 22.259 ;
     RECT  32.568 21.637 34.032 21.683 ;
     RECT  8.112 21.683 10.5 22.645 ;
     RECT  18.912 21.683 21.024 22.741 ;
     RECT  8.112 22.645 9.408 25.235 ;
     RECT  9.432 22.645 10.5 25.235 ;
     RECT  18.912 22.741 19.968 26.243 ;
     RECT  19.992 22.741 21.024 26.243 ;
     RECT  37.812 22.741 39.024 23.411 ;
     RECT  39.048 22.741 40.2 23.317 ;
     RECT  35.592 24.083 35.88 24.085 ;
     RECT  35.592 24.085 37.056 25.715 ;
     RECT  2.712 26.245 3.936 27.059 ;
     RECT  3.96 26.245 5.1 27.013 ;
  END
END qfd_landh_128_EW_65x30
END LIBRARY
